VERSION 5.8 ;
BUSBITCHARS "[]" ;
DIVIDERCHAR "/" ;
UNITS
    DATABASE MICRONS 1000 ;
END UNITS

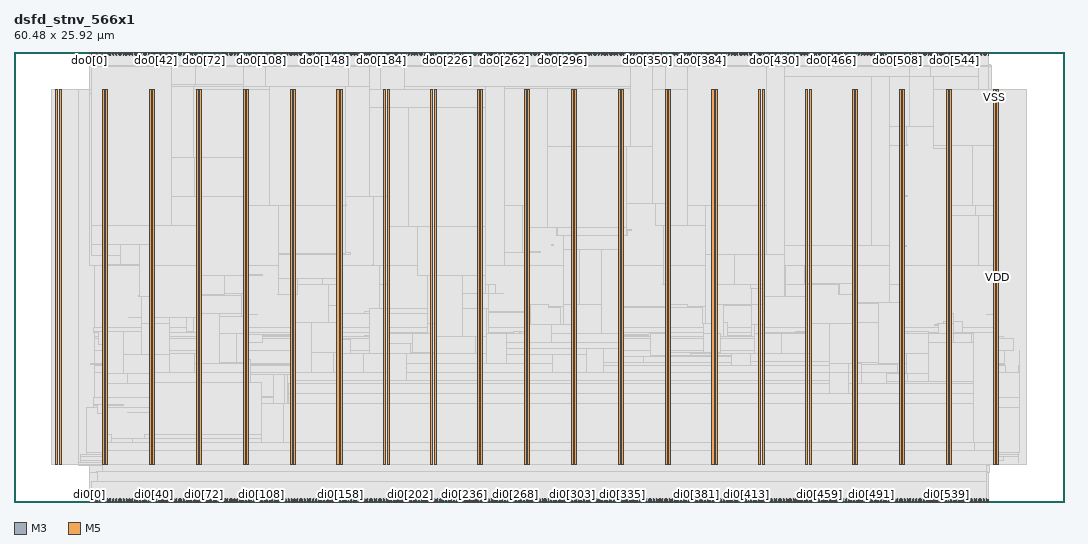
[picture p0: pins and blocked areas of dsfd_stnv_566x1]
MACRO dsfd_stnv_566x1
  FOREIGN dsfd_stnv_566x1 0 0 ;
  CLASS BLOCK ;
  SIZE 60.48 BY 25.92 ;
  PIN di0[0]
    DIRECTION INPUT ;
    USE SIGNAL ;
    PORT
      LAYER M3 ;
        RECT  4.356 0 4.374 0.144 ;
    END
  END di0[0]
  PIN di0[100]
    DIRECTION INPUT ;
    USE SIGNAL ;
    PORT
      LAYER M3 ;
        RECT  13.5 0 13.518 0.144 ;
    END
  END di0[100]
  PIN di0[101]
    DIRECTION INPUT ;
    USE SIGNAL ;
    PORT
      LAYER M5 ;
        RECT  13.584 0 13.608 0.192 ;
    END
  END di0[101]
  PIN di0[102]
    DIRECTION INPUT ;
    USE SIGNAL ;
    PORT
      LAYER M3 ;
        RECT  13.68 0 13.698 0.144 ;
    END
  END di0[102]
  PIN di0[103]
    DIRECTION INPUT ;
    USE SIGNAL ;
    PORT
      LAYER M5 ;
        RECT  13.776 0 13.8 0.192 ;
    END
  END di0[103]
  PIN di0[104]
    DIRECTION INPUT ;
    USE SIGNAL ;
    PORT
      LAYER M3 ;
        RECT  13.86 0 13.878 0.144 ;
    END
  END di0[104]
  PIN di0[105]
    DIRECTION INPUT ;
    USE SIGNAL ;
    PORT
      LAYER M5 ;
        RECT  13.968 0 13.992 0.192 ;
    END
  END di0[105]
  PIN di0[106]
    DIRECTION INPUT ;
    USE SIGNAL ;
    PORT
      LAYER M3 ;
        RECT  14.04 0 14.058 0.144 ;
    END
  END di0[106]
  PIN di0[107]
    DIRECTION INPUT ;
    USE SIGNAL ;
    PORT
      LAYER M5 ;
        RECT  14.16 0 14.184 0.192 ;
    END
  END di0[107]
  PIN di0[108]
    DIRECTION INPUT ;
    USE SIGNAL ;
    PORT
      LAYER M3 ;
        RECT  14.22 0 14.238 0.144 ;
    END
  END di0[108]
  PIN di0[109]
    DIRECTION INPUT ;
    USE SIGNAL ;
    PORT
      LAYER M5 ;
        RECT  14.304 0 14.328 0.192 ;
    END
  END di0[109]
  PIN di0[10]
    DIRECTION INPUT ;
    USE SIGNAL ;
    PORT
      LAYER M3 ;
        RECT  5.256 0 5.274 0.144 ;
    END
  END di0[10]
  PIN di0[110]
    DIRECTION INPUT ;
    USE SIGNAL ;
    PORT
      LAYER M3 ;
        RECT  14.4 0 14.418 0.144 ;
    END
  END di0[110]
  PIN di0[111]
    DIRECTION INPUT ;
    USE SIGNAL ;
    PORT
      LAYER M5 ;
        RECT  14.496 0 14.52 0.192 ;
    END
  END di0[111]
  PIN di0[112]
    DIRECTION INPUT ;
    USE SIGNAL ;
    PORT
      LAYER M3 ;
        RECT  14.58 0 14.598 0.144 ;
    END
  END di0[112]
  PIN di0[113]
    DIRECTION INPUT ;
    USE SIGNAL ;
    PORT
      LAYER M5 ;
        RECT  14.688 0 14.712 0.192 ;
    END
  END di0[113]
  PIN di0[114]
    DIRECTION INPUT ;
    USE SIGNAL ;
    PORT
      LAYER M3 ;
        RECT  14.796 0 14.814 0.144 ;
    END
  END di0[114]
  PIN di0[115]
    DIRECTION INPUT ;
    USE SIGNAL ;
    PORT
      LAYER M5 ;
        RECT  14.88 0 14.904 0.192 ;
    END
  END di0[115]
  PIN di0[116]
    DIRECTION INPUT ;
    USE SIGNAL ;
    PORT
      LAYER M3 ;
        RECT  14.976 0 14.994 0.144 ;
    END
  END di0[116]
  PIN di0[117]
    DIRECTION INPUT ;
    USE SIGNAL ;
    PORT
      LAYER M5 ;
        RECT  15.072 0 15.096 0.192 ;
    END
  END di0[117]
  PIN di0[118]
    DIRECTION INPUT ;
    USE SIGNAL ;
    PORT
      LAYER M3 ;
        RECT  15.156 0 15.174 0.144 ;
    END
  END di0[118]
  PIN di0[119]
    DIRECTION INPUT ;
    USE SIGNAL ;
    PORT
      LAYER M5 ;
        RECT  15.216 0 15.24 0.192 ;
    END
  END di0[119]
  PIN di0[11]
    DIRECTION INPUT ;
    USE SIGNAL ;
    PORT
      LAYER M5 ;
        RECT  5.376 0 5.4 0.192 ;
    END
  END di0[11]
  PIN di0[120]
    DIRECTION INPUT ;
    USE SIGNAL ;
    PORT
      LAYER M3 ;
        RECT  15.336 0 15.354 0.144 ;
    END
  END di0[120]
  PIN di0[121]
    DIRECTION INPUT ;
    USE SIGNAL ;
    PORT
      LAYER M5 ;
        RECT  15.408 0 15.432 0.192 ;
    END
  END di0[121]
  PIN di0[122]
    DIRECTION INPUT ;
    USE SIGNAL ;
    PORT
      LAYER M3 ;
        RECT  15.516 0 15.534 0.144 ;
    END
  END di0[122]
  PIN di0[123]
    DIRECTION INPUT ;
    USE SIGNAL ;
    PORT
      LAYER M5 ;
        RECT  15.6 0 15.624 0.192 ;
    END
  END di0[123]
  PIN di0[124]
    DIRECTION INPUT ;
    USE SIGNAL ;
    PORT
      LAYER M3 ;
        RECT  15.696 0 15.714 0.144 ;
    END
  END di0[124]
  PIN di0[125]
    DIRECTION INPUT ;
    USE SIGNAL ;
    PORT
      LAYER M5 ;
        RECT  15.792 0 15.816 0.192 ;
    END
  END di0[125]
  PIN di0[126]
    DIRECTION INPUT ;
    USE SIGNAL ;
    PORT
      LAYER M3 ;
        RECT  15.876 0 15.894 0.144 ;
    END
  END di0[126]
  PIN di0[127]
    DIRECTION INPUT ;
    USE SIGNAL ;
    PORT
      LAYER M5 ;
        RECT  15.984 0 16.008 0.192 ;
    END
  END di0[127]
  PIN di0[128]
    DIRECTION INPUT ;
    USE SIGNAL ;
    PORT
      LAYER M3 ;
        RECT  16.056 0 16.074 0.144 ;
    END
  END di0[128]
  PIN di0[129]
    DIRECTION INPUT ;
    USE SIGNAL ;
    PORT
      LAYER M5 ;
        RECT  16.128 0 16.152 0.192 ;
    END
  END di0[129]
  PIN di0[12]
    DIRECTION INPUT ;
    USE SIGNAL ;
    PORT
      LAYER M3 ;
        RECT  5.436 0 5.454 0.144 ;
    END
  END di0[12]
  PIN di0[130]
    DIRECTION INPUT ;
    USE SIGNAL ;
    PORT
      LAYER M3 ;
        RECT  16.236 0 16.254 0.144 ;
    END
  END di0[130]
  PIN di0[131]
    DIRECTION INPUT ;
    USE SIGNAL ;
    PORT
      LAYER M5 ;
        RECT  16.32 0 16.344 0.192 ;
    END
  END di0[131]
  PIN di0[132]
    DIRECTION INPUT ;
    USE SIGNAL ;
    PORT
      LAYER M3 ;
        RECT  16.416 0 16.434 0.144 ;
    END
  END di0[132]
  PIN di0[133]
    DIRECTION INPUT ;
    USE SIGNAL ;
    PORT
      LAYER M5 ;
        RECT  16.512 0 16.536 0.192 ;
    END
  END di0[133]
  PIN di0[134]
    DIRECTION INPUT ;
    USE SIGNAL ;
    PORT
      LAYER M3 ;
        RECT  16.596 0 16.614 0.144 ;
    END
  END di0[134]
  PIN di0[135]
    DIRECTION INPUT ;
    USE SIGNAL ;
    PORT
      LAYER M5 ;
        RECT  16.704 0 16.728 0.192 ;
    END
  END di0[135]
  PIN di0[136]
    DIRECTION INPUT ;
    USE SIGNAL ;
    PORT
      LAYER M3 ;
        RECT  16.776 0 16.794 0.144 ;
    END
  END di0[136]
  PIN di0[137]
    DIRECTION INPUT ;
    USE SIGNAL ;
    PORT
      LAYER M5 ;
        RECT  16.896 0 16.92 0.192 ;
    END
  END di0[137]
  PIN di0[138]
    DIRECTION INPUT ;
    USE SIGNAL ;
    PORT
      LAYER M3 ;
        RECT  16.956 0 16.974 0.144 ;
    END
  END di0[138]
  PIN di0[139]
    DIRECTION INPUT ;
    USE SIGNAL ;
    PORT
      LAYER M5 ;
        RECT  17.04 0 17.064 0.192 ;
    END
  END di0[139]
  PIN di0[13]
    DIRECTION INPUT ;
    USE SIGNAL ;
    PORT
      LAYER M5 ;
        RECT  5.52 0 5.544 0.192 ;
    END
  END di0[13]
  PIN di0[140]
    DIRECTION INPUT ;
    USE SIGNAL ;
    PORT
      LAYER M3 ;
        RECT  17.172 0 17.19 0.144 ;
    END
  END di0[140]
  PIN di0[141]
    DIRECTION INPUT ;
    USE SIGNAL ;
    PORT
      LAYER M5 ;
        RECT  17.232 0 17.256 0.192 ;
    END
  END di0[141]
  PIN di0[142]
    DIRECTION INPUT ;
    USE SIGNAL ;
    PORT
      LAYER M3 ;
        RECT  17.352 0 17.37 0.144 ;
    END
  END di0[142]
  PIN di0[143]
    DIRECTION INPUT ;
    USE SIGNAL ;
    PORT
      LAYER M5 ;
        RECT  17.424 0 17.448 0.192 ;
    END
  END di0[143]
  PIN di0[144]
    DIRECTION INPUT ;
    USE SIGNAL ;
    PORT
      LAYER M3 ;
        RECT  17.532 0 17.55 0.144 ;
    END
  END di0[144]
  PIN di0[145]
    DIRECTION INPUT ;
    USE SIGNAL ;
    PORT
      LAYER M5 ;
        RECT  17.616 0 17.64 0.192 ;
    END
  END di0[145]
  PIN di0[146]
    DIRECTION INPUT ;
    USE SIGNAL ;
    PORT
      LAYER M3 ;
        RECT  17.712 0 17.73 0.144 ;
    END
  END di0[146]
  PIN di0[147]
    DIRECTION INPUT ;
    USE SIGNAL ;
    PORT
      LAYER M5 ;
        RECT  17.808 0 17.832 0.192 ;
    END
  END di0[147]
  PIN di0[148]
    DIRECTION INPUT ;
    USE SIGNAL ;
    PORT
      LAYER M3 ;
        RECT  17.892 0 17.91 0.144 ;
    END
  END di0[148]
  PIN di0[149]
    DIRECTION INPUT ;
    USE SIGNAL ;
    PORT
      LAYER M5 ;
        RECT  18 0 18.024 0.192 ;
    END
  END di0[149]
  PIN di0[14]
    DIRECTION INPUT ;
    USE SIGNAL ;
    PORT
      LAYER M3 ;
        RECT  5.652 0 5.67 0.144 ;
    END
  END di0[14]
  PIN di0[150]
    DIRECTION INPUT ;
    USE SIGNAL ;
    PORT
      LAYER M3 ;
        RECT  18.072 0 18.09 0.144 ;
    END
  END di0[150]
  PIN di0[151]
    DIRECTION INPUT ;
    USE SIGNAL ;
    PORT
      LAYER M5 ;
        RECT  18.144 0 18.168 0.192 ;
    END
  END di0[151]
  PIN di0[152]
    DIRECTION INPUT ;
    USE SIGNAL ;
    PORT
      LAYER M3 ;
        RECT  18.252 0 18.27 0.144 ;
    END
  END di0[152]
  PIN di0[153]
    DIRECTION INPUT ;
    USE SIGNAL ;
    PORT
      LAYER M5 ;
        RECT  18.336 0 18.36 0.192 ;
    END
  END di0[153]
  PIN di0[154]
    DIRECTION INPUT ;
    USE SIGNAL ;
    PORT
      LAYER M3 ;
        RECT  18.432 0 18.45 0.144 ;
    END
  END di0[154]
  PIN di0[155]
    DIRECTION INPUT ;
    USE SIGNAL ;
    PORT
      LAYER M5 ;
        RECT  18.528 0 18.552 0.192 ;
    END
  END di0[155]
  PIN di0[156]
    DIRECTION INPUT ;
    USE SIGNAL ;
    PORT
      LAYER M3 ;
        RECT  18.612 0 18.63 0.144 ;
    END
  END di0[156]
  PIN di0[157]
    DIRECTION INPUT ;
    USE SIGNAL ;
    PORT
      LAYER M5 ;
        RECT  18.72 0 18.744 0.192 ;
    END
  END di0[157]
  PIN di0[158]
    DIRECTION INPUT ;
    USE SIGNAL ;
    PORT
      LAYER M3 ;
        RECT  18.792 0 18.81 0.144 ;
    END
  END di0[158]
  PIN di0[159]
    DIRECTION INPUT ;
    USE SIGNAL ;
    PORT
      LAYER M5 ;
        RECT  18.912 0 18.936 0.192 ;
    END
  END di0[159]
  PIN di0[15]
    DIRECTION INPUT ;
    USE SIGNAL ;
    PORT
      LAYER M5 ;
        RECT  5.712 0 5.736 0.192 ;
    END
  END di0[15]
  PIN di0[160]
    DIRECTION INPUT ;
    USE SIGNAL ;
    PORT
      LAYER M3 ;
        RECT  18.972 0 18.99 0.144 ;
    END
  END di0[160]
  PIN di0[161]
    DIRECTION INPUT ;
    USE SIGNAL ;
    PORT
      LAYER M5 ;
        RECT  19.056 0 19.08 0.192 ;
    END
  END di0[161]
  PIN di0[162]
    DIRECTION INPUT ;
    USE SIGNAL ;
    PORT
      LAYER M3 ;
        RECT  19.152 0 19.17 0.144 ;
    END
  END di0[162]
  PIN di0[163]
    DIRECTION INPUT ;
    USE SIGNAL ;
    PORT
      LAYER M5 ;
        RECT  19.248 0 19.272 0.192 ;
    END
  END di0[163]
  PIN di0[164]
    DIRECTION INPUT ;
    USE SIGNAL ;
    PORT
      LAYER M3 ;
        RECT  19.368 0 19.386 0.144 ;
    END
  END di0[164]
  PIN di0[165]
    DIRECTION INPUT ;
    USE SIGNAL ;
    PORT
      LAYER M5 ;
        RECT  19.44 0 19.464 0.192 ;
    END
  END di0[165]
  PIN di0[166]
    DIRECTION INPUT ;
    USE SIGNAL ;
    PORT
      LAYER M3 ;
        RECT  19.548 0 19.566 0.144 ;
    END
  END di0[166]
  PIN di0[167]
    DIRECTION INPUT ;
    USE SIGNAL ;
    PORT
      LAYER M5 ;
        RECT  19.632 0 19.656 0.192 ;
    END
  END di0[167]
  PIN di0[168]
    DIRECTION INPUT ;
    USE SIGNAL ;
    PORT
      LAYER M3 ;
        RECT  19.728 0 19.746 0.144 ;
    END
  END di0[168]
  PIN di0[169]
    DIRECTION INPUT ;
    USE SIGNAL ;
    PORT
      LAYER M5 ;
        RECT  19.824 0 19.848 0.192 ;
    END
  END di0[169]
  PIN di0[16]
    DIRECTION INPUT ;
    USE SIGNAL ;
    PORT
      LAYER M3 ;
        RECT  5.832 0 5.85 0.144 ;
    END
  END di0[16]
  PIN di0[170]
    DIRECTION INPUT ;
    USE SIGNAL ;
    PORT
      LAYER M3 ;
        RECT  19.908 0 19.926 0.144 ;
    END
  END di0[170]
  PIN di0[171]
    DIRECTION INPUT ;
    USE SIGNAL ;
    PORT
      LAYER M5 ;
        RECT  19.968 0 19.992 0.192 ;
    END
  END di0[171]
  PIN di0[172]
    DIRECTION INPUT ;
    USE SIGNAL ;
    PORT
      LAYER M3 ;
        RECT  20.088 0 20.106 0.144 ;
    END
  END di0[172]
  PIN di0[173]
    DIRECTION INPUT ;
    USE SIGNAL ;
    PORT
      LAYER M5 ;
        RECT  20.16 0 20.184 0.192 ;
    END
  END di0[173]
  PIN di0[174]
    DIRECTION INPUT ;
    USE SIGNAL ;
    PORT
      LAYER M3 ;
        RECT  20.268 0 20.286 0.144 ;
    END
  END di0[174]
  PIN di0[175]
    DIRECTION INPUT ;
    USE SIGNAL ;
    PORT
      LAYER M5 ;
        RECT  20.352 0 20.376 0.192 ;
    END
  END di0[175]
  PIN di0[176]
    DIRECTION INPUT ;
    USE SIGNAL ;
    PORT
      LAYER M3 ;
        RECT  20.448 0 20.466 0.144 ;
    END
  END di0[176]
  PIN di0[177]
    DIRECTION INPUT ;
    USE SIGNAL ;
    PORT
      LAYER M5 ;
        RECT  20.544 0 20.568 0.192 ;
    END
  END di0[177]
  PIN di0[178]
    DIRECTION INPUT ;
    USE SIGNAL ;
    PORT
      LAYER M3 ;
        RECT  20.628 0 20.646 0.144 ;
    END
  END di0[178]
  PIN di0[179]
    DIRECTION INPUT ;
    USE SIGNAL ;
    PORT
      LAYER M5 ;
        RECT  20.736 0 20.76 0.192 ;
    END
  END di0[179]
  PIN di0[17]
    DIRECTION INPUT ;
    USE SIGNAL ;
    PORT
      LAYER M5 ;
        RECT  5.904 0 5.928 0.192 ;
    END
  END di0[17]
  PIN di0[180]
    DIRECTION INPUT ;
    USE SIGNAL ;
    PORT
      LAYER M3 ;
        RECT  20.808 0 20.826 0.144 ;
    END
  END di0[180]
  PIN di0[181]
    DIRECTION INPUT ;
    USE SIGNAL ;
    PORT
      LAYER M5 ;
        RECT  20.88 0 20.904 0.192 ;
    END
  END di0[181]
  PIN di0[182]
    DIRECTION INPUT ;
    USE SIGNAL ;
    PORT
      LAYER M3 ;
        RECT  20.988 0 21.006 0.144 ;
    END
  END di0[182]
  PIN di0[183]
    DIRECTION INPUT ;
    USE SIGNAL ;
    PORT
      LAYER M5 ;
        RECT  21.072 0 21.096 0.192 ;
    END
  END di0[183]
  PIN di0[184]
    DIRECTION INPUT ;
    USE SIGNAL ;
    PORT
      LAYER M3 ;
        RECT  21.168 0 21.186 0.144 ;
    END
  END di0[184]
  PIN di0[185]
    DIRECTION INPUT ;
    USE SIGNAL ;
    PORT
      LAYER M5 ;
        RECT  21.264 0 21.288 0.192 ;
    END
  END di0[185]
  PIN di0[186]
    DIRECTION INPUT ;
    USE SIGNAL ;
    PORT
      LAYER M3 ;
        RECT  21.348 0 21.366 0.144 ;
    END
  END di0[186]
  PIN di0[187]
    DIRECTION INPUT ;
    USE SIGNAL ;
    PORT
      LAYER M5 ;
        RECT  21.456 0 21.48 0.192 ;
    END
  END di0[187]
  PIN di0[188]
    DIRECTION INPUT ;
    USE SIGNAL ;
    PORT
      LAYER M3 ;
        RECT  21.528 0 21.546 0.144 ;
    END
  END di0[188]
  PIN di0[189]
    DIRECTION INPUT ;
    USE SIGNAL ;
    PORT
      LAYER M5 ;
        RECT  21.648 0 21.672 0.192 ;
    END
  END di0[189]
  PIN di0[18]
    DIRECTION INPUT ;
    USE SIGNAL ;
    PORT
      LAYER M3 ;
        RECT  6.012 0 6.03 0.144 ;
    END
  END di0[18]
  PIN di0[190]
    DIRECTION INPUT ;
    USE SIGNAL ;
    PORT
      LAYER M3 ;
        RECT  21.744 0 21.762 0.144 ;
    END
  END di0[190]
  PIN di0[191]
    DIRECTION INPUT ;
    USE SIGNAL ;
    PORT
      LAYER M5 ;
        RECT  21.84 0 21.864 0.192 ;
    END
  END di0[191]
  PIN di0[192]
    DIRECTION INPUT ;
    USE SIGNAL ;
    PORT
      LAYER M3 ;
        RECT  21.924 0 21.942 0.144 ;
    END
  END di0[192]
  PIN di0[193]
    DIRECTION INPUT ;
    USE SIGNAL ;
    PORT
      LAYER M5 ;
        RECT  21.984 0 22.008 0.192 ;
    END
  END di0[193]
  PIN di0[194]
    DIRECTION INPUT ;
    USE SIGNAL ;
    PORT
      LAYER M3 ;
        RECT  22.104 0 22.122 0.144 ;
    END
  END di0[194]
  PIN di0[195]
    DIRECTION INPUT ;
    USE SIGNAL ;
    PORT
      LAYER M5 ;
        RECT  22.176 0 22.2 0.192 ;
    END
  END di0[195]
  PIN di0[196]
    DIRECTION INPUT ;
    USE SIGNAL ;
    PORT
      LAYER M3 ;
        RECT  22.284 0 22.302 0.144 ;
    END
  END di0[196]
  PIN di0[197]
    DIRECTION INPUT ;
    USE SIGNAL ;
    PORT
      LAYER M5 ;
        RECT  22.368 0 22.392 0.192 ;
    END
  END di0[197]
  PIN di0[198]
    DIRECTION INPUT ;
    USE SIGNAL ;
    PORT
      LAYER M3 ;
        RECT  22.464 0 22.482 0.144 ;
    END
  END di0[198]
  PIN di0[199]
    DIRECTION INPUT ;
    USE SIGNAL ;
    PORT
      LAYER M5 ;
        RECT  22.56 0 22.584 0.192 ;
    END
  END di0[199]
  PIN di0[19]
    DIRECTION INPUT ;
    USE SIGNAL ;
    PORT
      LAYER M5 ;
        RECT  6.096 0 6.12 0.192 ;
    END
  END di0[19]
  PIN di0[1]
    DIRECTION INPUT ;
    USE SIGNAL ;
    PORT
      LAYER M5 ;
        RECT  4.464 0 4.488 0.192 ;
    END
  END di0[1]
  PIN di0[200]
    DIRECTION INPUT ;
    USE SIGNAL ;
    PORT
      LAYER M3 ;
        RECT  22.644 0 22.662 0.144 ;
    END
  END di0[200]
  PIN di0[201]
    DIRECTION INPUT ;
    USE SIGNAL ;
    PORT
      LAYER M5 ;
        RECT  22.752 0 22.776 0.192 ;
    END
  END di0[201]
  PIN di0[202]
    DIRECTION INPUT ;
    USE SIGNAL ;
    PORT
      LAYER M3 ;
        RECT  22.824 0 22.842 0.144 ;
    END
  END di0[202]
  PIN di0[203]
    DIRECTION INPUT ;
    USE SIGNAL ;
    PORT
      LAYER M5 ;
        RECT  22.896 0 22.92 0.192 ;
    END
  END di0[203]
  PIN di0[204]
    DIRECTION INPUT ;
    USE SIGNAL ;
    PORT
      LAYER M3 ;
        RECT  23.004 0 23.022 0.144 ;
    END
  END di0[204]
  PIN di0[205]
    DIRECTION INPUT ;
    USE SIGNAL ;
    PORT
      LAYER M5 ;
        RECT  23.088 0 23.112 0.192 ;
    END
  END di0[205]
  PIN di0[206]
    DIRECTION INPUT ;
    USE SIGNAL ;
    PORT
      LAYER M3 ;
        RECT  23.184 0 23.202 0.144 ;
    END
  END di0[206]
  PIN di0[207]
    DIRECTION INPUT ;
    USE SIGNAL ;
    PORT
      LAYER M5 ;
        RECT  23.28 0 23.304 0.192 ;
    END
  END di0[207]
  PIN di0[208]
    DIRECTION INPUT ;
    USE SIGNAL ;
    PORT
      LAYER M3 ;
        RECT  23.364 0 23.382 0.144 ;
    END
  END di0[208]
  PIN di0[209]
    DIRECTION INPUT ;
    USE SIGNAL ;
    PORT
      LAYER M5 ;
        RECT  23.472 0 23.496 0.192 ;
    END
  END di0[209]
  PIN di0[20]
    DIRECTION INPUT ;
    USE SIGNAL ;
    PORT
      LAYER M3 ;
        RECT  6.192 0 6.21 0.144 ;
    END
  END di0[20]
  PIN di0[210]
    DIRECTION INPUT ;
    USE SIGNAL ;
    PORT
      LAYER M3 ;
        RECT  23.544 0 23.562 0.144 ;
    END
  END di0[210]
  PIN di0[211]
    DIRECTION INPUT ;
    USE SIGNAL ;
    PORT
      LAYER M5 ;
        RECT  23.664 0 23.688 0.192 ;
    END
  END di0[211]
  PIN di0[212]
    DIRECTION INPUT ;
    USE SIGNAL ;
    PORT
      LAYER M3 ;
        RECT  23.724 0 23.742 0.144 ;
    END
  END di0[212]
  PIN di0[213]
    DIRECTION INPUT ;
    USE SIGNAL ;
    PORT
      LAYER M5 ;
        RECT  23.808 0 23.832 0.192 ;
    END
  END di0[213]
  PIN di0[214]
    DIRECTION INPUT ;
    USE SIGNAL ;
    PORT
      LAYER M3 ;
        RECT  23.94 0 23.958 0.144 ;
    END
  END di0[214]
  PIN di0[215]
    DIRECTION INPUT ;
    USE SIGNAL ;
    PORT
      LAYER M5 ;
        RECT  24 0 24.024 0.192 ;
    END
  END di0[215]
  PIN di0[216]
    DIRECTION INPUT ;
    USE SIGNAL ;
    PORT
      LAYER M3 ;
        RECT  24.12 0 24.138 0.144 ;
    END
  END di0[216]
  PIN di0[217]
    DIRECTION INPUT ;
    USE SIGNAL ;
    PORT
      LAYER M5 ;
        RECT  24.192 0 24.216 0.192 ;
    END
  END di0[217]
  PIN di0[218]
    DIRECTION INPUT ;
    USE SIGNAL ;
    PORT
      LAYER M3 ;
        RECT  24.3 0 24.318 0.144 ;
    END
  END di0[218]
  PIN di0[219]
    DIRECTION INPUT ;
    USE SIGNAL ;
    PORT
      LAYER M5 ;
        RECT  24.384 0 24.408 0.192 ;
    END
  END di0[219]
  PIN di0[21]
    DIRECTION INPUT ;
    USE SIGNAL ;
    PORT
      LAYER M5 ;
        RECT  6.288 0 6.312 0.192 ;
    END
  END di0[21]
  PIN di0[220]
    DIRECTION INPUT ;
    USE SIGNAL ;
    PORT
      LAYER M3 ;
        RECT  24.48 0 24.498 0.144 ;
    END
  END di0[220]
  PIN di0[221]
    DIRECTION INPUT ;
    USE SIGNAL ;
    PORT
      LAYER M5 ;
        RECT  24.576 0 24.6 0.192 ;
    END
  END di0[221]
  PIN di0[222]
    DIRECTION INPUT ;
    USE SIGNAL ;
    PORT
      LAYER M3 ;
        RECT  24.66 0 24.678 0.144 ;
    END
  END di0[222]
  PIN di0[223]
    DIRECTION INPUT ;
    USE SIGNAL ;
    PORT
      LAYER M5 ;
        RECT  24.72 0 24.744 0.192 ;
    END
  END di0[223]
  PIN di0[224]
    DIRECTION INPUT ;
    USE SIGNAL ;
    PORT
      LAYER M3 ;
        RECT  24.84 0 24.858 0.144 ;
    END
  END di0[224]
  PIN di0[225]
    DIRECTION INPUT ;
    USE SIGNAL ;
    PORT
      LAYER M5 ;
        RECT  24.912 0 24.936 0.192 ;
    END
  END di0[225]
  PIN di0[226]
    DIRECTION INPUT ;
    USE SIGNAL ;
    PORT
      LAYER M3 ;
        RECT  25.02 0 25.038 0.144 ;
    END
  END di0[226]
  PIN di0[227]
    DIRECTION INPUT ;
    USE SIGNAL ;
    PORT
      LAYER M5 ;
        RECT  25.104 0 25.128 0.192 ;
    END
  END di0[227]
  PIN di0[228]
    DIRECTION INPUT ;
    USE SIGNAL ;
    PORT
      LAYER M3 ;
        RECT  25.2 0 25.218 0.144 ;
    END
  END di0[228]
  PIN di0[229]
    DIRECTION INPUT ;
    USE SIGNAL ;
    PORT
      LAYER M5 ;
        RECT  25.296 0 25.32 0.192 ;
    END
  END di0[229]
  PIN di0[22]
    DIRECTION INPUT ;
    USE SIGNAL ;
    PORT
      LAYER M3 ;
        RECT  6.372 0 6.39 0.144 ;
    END
  END di0[22]
  PIN di0[230]
    DIRECTION INPUT ;
    USE SIGNAL ;
    PORT
      LAYER M3 ;
        RECT  25.38 0 25.398 0.144 ;
    END
  END di0[230]
  PIN di0[231]
    DIRECTION INPUT ;
    USE SIGNAL ;
    PORT
      LAYER M5 ;
        RECT  25.488 0 25.512 0.192 ;
    END
  END di0[231]
  PIN di0[232]
    DIRECTION INPUT ;
    USE SIGNAL ;
    PORT
      LAYER M3 ;
        RECT  25.56 0 25.578 0.144 ;
    END
  END di0[232]
  PIN di0[233]
    DIRECTION INPUT ;
    USE SIGNAL ;
    PORT
      LAYER M5 ;
        RECT  25.68 0 25.704 0.192 ;
    END
  END di0[233]
  PIN di0[234]
    DIRECTION INPUT ;
    USE SIGNAL ;
    PORT
      LAYER M3 ;
        RECT  25.74 0 25.758 0.144 ;
    END
  END di0[234]
  PIN di0[235]
    DIRECTION INPUT ;
    USE SIGNAL ;
    PORT
      LAYER M5 ;
        RECT  25.824 0 25.848 0.192 ;
    END
  END di0[235]
  PIN di0[236]
    DIRECTION INPUT ;
    USE SIGNAL ;
    PORT
      LAYER M3 ;
        RECT  25.92 0 25.938 0.144 ;
    END
  END di0[236]
  PIN di0[237]
    DIRECTION INPUT ;
    USE SIGNAL ;
    PORT
      LAYER M5 ;
        RECT  26.016 0 26.04 0.192 ;
    END
  END di0[237]
  PIN di0[238]
    DIRECTION INPUT ;
    USE SIGNAL ;
    PORT
      LAYER M3 ;
        RECT  26.1 0 26.118 0.144 ;
    END
  END di0[238]
  PIN di0[239]
    DIRECTION INPUT ;
    USE SIGNAL ;
    PORT
      LAYER M5 ;
        RECT  26.208 0 26.232 0.192 ;
    END
  END di0[239]
  PIN di0[23]
    DIRECTION INPUT ;
    USE SIGNAL ;
    PORT
      LAYER M5 ;
        RECT  6.48 0 6.504 0.192 ;
    END
  END di0[23]
  PIN di0[240]
    DIRECTION INPUT ;
    USE SIGNAL ;
    PORT
      LAYER M3 ;
        RECT  26.316 0 26.334 0.144 ;
    END
  END di0[240]
  PIN di0[241]
    DIRECTION INPUT ;
    USE SIGNAL ;
    PORT
      LAYER M5 ;
        RECT  26.4 0 26.424 0.192 ;
    END
  END di0[241]
  PIN di0[242]
    DIRECTION INPUT ;
    USE SIGNAL ;
    PORT
      LAYER M3 ;
        RECT  26.496 0 26.514 0.144 ;
    END
  END di0[242]
  PIN di0[243]
    DIRECTION INPUT ;
    USE SIGNAL ;
    PORT
      LAYER M5 ;
        RECT  26.592 0 26.616 0.192 ;
    END
  END di0[243]
  PIN di0[244]
    DIRECTION INPUT ;
    USE SIGNAL ;
    PORT
      LAYER M3 ;
        RECT  26.676 0 26.694 0.144 ;
    END
  END di0[244]
  PIN di0[245]
    DIRECTION INPUT ;
    USE SIGNAL ;
    PORT
      LAYER M5 ;
        RECT  26.736 0 26.76 0.192 ;
    END
  END di0[245]
  PIN di0[246]
    DIRECTION INPUT ;
    USE SIGNAL ;
    PORT
      LAYER M3 ;
        RECT  26.856 0 26.874 0.144 ;
    END
  END di0[246]
  PIN di0[247]
    DIRECTION INPUT ;
    USE SIGNAL ;
    PORT
      LAYER M5 ;
        RECT  26.928 0 26.952 0.192 ;
    END
  END di0[247]
  PIN di0[248]
    DIRECTION INPUT ;
    USE SIGNAL ;
    PORT
      LAYER M3 ;
        RECT  27.036 0 27.054 0.144 ;
    END
  END di0[248]
  PIN di0[249]
    DIRECTION INPUT ;
    USE SIGNAL ;
    PORT
      LAYER M5 ;
        RECT  27.12 0 27.144 0.192 ;
    END
  END di0[249]
  PIN di0[24]
    DIRECTION INPUT ;
    USE SIGNAL ;
    PORT
      LAYER M3 ;
        RECT  6.552 0 6.57 0.144 ;
    END
  END di0[24]
  PIN di0[250]
    DIRECTION INPUT ;
    USE SIGNAL ;
    PORT
      LAYER M3 ;
        RECT  27.216 0 27.234 0.144 ;
    END
  END di0[250]
  PIN di0[251]
    DIRECTION INPUT ;
    USE SIGNAL ;
    PORT
      LAYER M5 ;
        RECT  27.312 0 27.336 0.192 ;
    END
  END di0[251]
  PIN di0[252]
    DIRECTION INPUT ;
    USE SIGNAL ;
    PORT
      LAYER M3 ;
        RECT  27.396 0 27.414 0.144 ;
    END
  END di0[252]
  PIN di0[253]
    DIRECTION INPUT ;
    USE SIGNAL ;
    PORT
      LAYER M5 ;
        RECT  27.504 0 27.528 0.192 ;
    END
  END di0[253]
  PIN di0[254]
    DIRECTION INPUT ;
    USE SIGNAL ;
    PORT
      LAYER M3 ;
        RECT  27.576 0 27.594 0.144 ;
    END
  END di0[254]
  PIN di0[255]
    DIRECTION INPUT ;
    USE SIGNAL ;
    PORT
      LAYER M5 ;
        RECT  27.648 0 27.672 0.192 ;
    END
  END di0[255]
  PIN di0[256]
    DIRECTION INPUT ;
    USE SIGNAL ;
    PORT
      LAYER M3 ;
        RECT  27.756 0 27.774 0.144 ;
    END
  END di0[256]
  PIN di0[257]
    DIRECTION INPUT ;
    USE SIGNAL ;
    PORT
      LAYER M5 ;
        RECT  27.84 0 27.864 0.192 ;
    END
  END di0[257]
  PIN di0[258]
    DIRECTION INPUT ;
    USE SIGNAL ;
    PORT
      LAYER M3 ;
        RECT  27.936 0 27.954 0.144 ;
    END
  END di0[258]
  PIN di0[259]
    DIRECTION INPUT ;
    USE SIGNAL ;
    PORT
      LAYER M5 ;
        RECT  28.032 0 28.056 0.192 ;
    END
  END di0[259]
  PIN di0[25]
    DIRECTION INPUT ;
    USE SIGNAL ;
    PORT
      LAYER M5 ;
        RECT  6.624 0 6.648 0.192 ;
    END
  END di0[25]
  PIN di0[260]
    DIRECTION INPUT ;
    USE SIGNAL ;
    PORT
      LAYER M3 ;
        RECT  28.116 0 28.134 0.144 ;
    END
  END di0[260]
  PIN di0[261]
    DIRECTION INPUT ;
    USE SIGNAL ;
    PORT
      LAYER M5 ;
        RECT  28.224 0 28.248 0.192 ;
    END
  END di0[261]
  PIN di0[262]
    DIRECTION INPUT ;
    USE SIGNAL ;
    PORT
      LAYER M3 ;
        RECT  28.296 0 28.314 0.144 ;
    END
  END di0[262]
  PIN di0[263]
    DIRECTION INPUT ;
    USE SIGNAL ;
    PORT
      LAYER M5 ;
        RECT  28.416 0 28.44 0.192 ;
    END
  END di0[263]
  PIN di0[264]
    DIRECTION INPUT ;
    USE SIGNAL ;
    PORT
      LAYER M3 ;
        RECT  28.476 0 28.494 0.144 ;
    END
  END di0[264]
  PIN di0[265]
    DIRECTION INPUT ;
    USE SIGNAL ;
    PORT
      LAYER M5 ;
        RECT  28.56 0 28.584 0.192 ;
    END
  END di0[265]
  PIN di0[266]
    DIRECTION INPUT ;
    USE SIGNAL ;
    PORT
      LAYER M3 ;
        RECT  28.692 0 28.71 0.144 ;
    END
  END di0[266]
  PIN di0[267]
    DIRECTION INPUT ;
    USE SIGNAL ;
    PORT
      LAYER M5 ;
        RECT  28.752 0 28.776 0.192 ;
    END
  END di0[267]
  PIN di0[268]
    DIRECTION INPUT ;
    USE SIGNAL ;
    PORT
      LAYER M3 ;
        RECT  28.872 0 28.89 0.144 ;
    END
  END di0[268]
  PIN di0[269]
    DIRECTION INPUT ;
    USE SIGNAL ;
    PORT
      LAYER M5 ;
        RECT  28.944 0 28.968 0.192 ;
    END
  END di0[269]
  PIN di0[26]
    DIRECTION INPUT ;
    USE SIGNAL ;
    PORT
      LAYER M3 ;
        RECT  6.732 0 6.75 0.144 ;
    END
  END di0[26]
  PIN di0[270]
    DIRECTION INPUT ;
    USE SIGNAL ;
    PORT
      LAYER M3 ;
        RECT  29.052 0 29.07 0.144 ;
    END
  END di0[270]
  PIN di0[271]
    DIRECTION INPUT ;
    USE SIGNAL ;
    PORT
      LAYER M5 ;
        RECT  29.136 0 29.16 0.192 ;
    END
  END di0[271]
  PIN di0[272]
    DIRECTION INPUT ;
    USE SIGNAL ;
    PORT
      LAYER M3 ;
        RECT  29.232 0 29.25 0.144 ;
    END
  END di0[272]
  PIN di0[273]
    DIRECTION INPUT ;
    USE SIGNAL ;
    PORT
      LAYER M5 ;
        RECT  29.328 0 29.352 0.192 ;
    END
  END di0[273]
  PIN di0[274]
    DIRECTION INPUT ;
    USE SIGNAL ;
    PORT
      LAYER M3 ;
        RECT  29.412 0 29.43 0.144 ;
    END
  END di0[274]
  PIN di0[275]
    DIRECTION INPUT ;
    USE SIGNAL ;
    PORT
      LAYER M5 ;
        RECT  29.52 0 29.544 0.192 ;
    END
  END di0[275]
  PIN di0[276]
    DIRECTION INPUT ;
    USE SIGNAL ;
    PORT
      LAYER M3 ;
        RECT  29.592 0 29.61 0.144 ;
    END
  END di0[276]
  PIN di0[277]
    DIRECTION INPUT ;
    USE SIGNAL ;
    PORT
      LAYER M5 ;
        RECT  29.664 0 29.688 0.192 ;
    END
  END di0[277]
  PIN di0[278]
    DIRECTION INPUT ;
    USE SIGNAL ;
    PORT
      LAYER M3 ;
        RECT  29.772 0 29.79 0.144 ;
    END
  END di0[278]
  PIN di0[279]
    DIRECTION INPUT ;
    USE SIGNAL ;
    PORT
      LAYER M5 ;
        RECT  29.856 0 29.88 0.192 ;
    END
  END di0[279]
  PIN di0[27]
    DIRECTION INPUT ;
    USE SIGNAL ;
    PORT
      LAYER M5 ;
        RECT  6.816 0 6.84 0.192 ;
    END
  END di0[27]
  PIN di0[280]
    DIRECTION INPUT ;
    USE SIGNAL ;
    PORT
      LAYER M3 ;
        RECT  29.952 0 29.97 0.144 ;
    END
  END di0[280]
  PIN di0[281]
    DIRECTION INPUT ;
    USE SIGNAL ;
    PORT
      LAYER M5 ;
        RECT  30.048 0 30.072 0.192 ;
    END
  END di0[281]
  PIN di0[282]
    DIRECTION INPUT ;
    USE SIGNAL ;
    PORT
      LAYER M3 ;
        RECT  30.132 0 30.15 0.144 ;
    END
  END di0[282]
  PIN di0[283]
    DIRECTION INPUT ;
    USE SIGNAL ;
    PORT
      LAYER M3 ;
        RECT  30.312 0 30.33 0.144 ;
    END
  END di0[283]
  PIN di0[284]
    DIRECTION INPUT ;
    USE SIGNAL ;
    PORT
      LAYER M5 ;
        RECT  30.432 0 30.456 0.192 ;
    END
  END di0[284]
  PIN di0[285]
    DIRECTION INPUT ;
    USE SIGNAL ;
    PORT
      LAYER M3 ;
        RECT  30.492 0 30.51 0.144 ;
    END
  END di0[285]
  PIN di0[286]
    DIRECTION INPUT ;
    USE SIGNAL ;
    PORT
      LAYER M5 ;
        RECT  30.576 0 30.6 0.192 ;
    END
  END di0[286]
  PIN di0[287]
    DIRECTION INPUT ;
    USE SIGNAL ;
    PORT
      LAYER M3 ;
        RECT  30.672 0 30.69 0.144 ;
    END
  END di0[287]
  PIN di0[288]
    DIRECTION INPUT ;
    USE SIGNAL ;
    PORT
      LAYER M5 ;
        RECT  30.768 0 30.792 0.192 ;
    END
  END di0[288]
  PIN di0[289]
    DIRECTION INPUT ;
    USE SIGNAL ;
    PORT
      LAYER M3 ;
        RECT  30.888 0 30.906 0.144 ;
    END
  END di0[289]
  PIN di0[28]
    DIRECTION INPUT ;
    USE SIGNAL ;
    PORT
      LAYER M3 ;
        RECT  6.912 0 6.93 0.144 ;
    END
  END di0[28]
  PIN di0[290]
    DIRECTION INPUT ;
    USE SIGNAL ;
    PORT
      LAYER M5 ;
        RECT  30.96 0 30.984 0.192 ;
    END
  END di0[290]
  PIN di0[291]
    DIRECTION INPUT ;
    USE SIGNAL ;
    PORT
      LAYER M3 ;
        RECT  31.068 0 31.086 0.144 ;
    END
  END di0[291]
  PIN di0[292]
    DIRECTION INPUT ;
    USE SIGNAL ;
    PORT
      LAYER M5 ;
        RECT  31.152 0 31.176 0.192 ;
    END
  END di0[292]
  PIN di0[293]
    DIRECTION INPUT ;
    USE SIGNAL ;
    PORT
      LAYER M3 ;
        RECT  31.248 0 31.266 0.144 ;
    END
  END di0[293]
  PIN di0[294]
    DIRECTION INPUT ;
    USE SIGNAL ;
    PORT
      LAYER M5 ;
        RECT  31.344 0 31.368 0.192 ;
    END
  END di0[294]
  PIN di0[295]
    DIRECTION INPUT ;
    USE SIGNAL ;
    PORT
      LAYER M3 ;
        RECT  31.428 0 31.446 0.144 ;
    END
  END di0[295]
  PIN di0[296]
    DIRECTION INPUT ;
    USE SIGNAL ;
    PORT
      LAYER M5 ;
        RECT  31.488 0 31.512 0.192 ;
    END
  END di0[296]
  PIN di0[297]
    DIRECTION INPUT ;
    USE SIGNAL ;
    PORT
      LAYER M3 ;
        RECT  31.608 0 31.626 0.144 ;
    END
  END di0[297]
  PIN di0[298]
    DIRECTION INPUT ;
    USE SIGNAL ;
    PORT
      LAYER M5 ;
        RECT  31.68 0 31.704 0.192 ;
    END
  END di0[298]
  PIN di0[299]
    DIRECTION INPUT ;
    USE SIGNAL ;
    PORT
      LAYER M3 ;
        RECT  31.788 0 31.806 0.144 ;
    END
  END di0[299]
  PIN di0[29]
    DIRECTION INPUT ;
    USE SIGNAL ;
    PORT
      LAYER M5 ;
        RECT  7.008 0 7.032 0.192 ;
    END
  END di0[29]
  PIN di0[2]
    DIRECTION INPUT ;
    USE SIGNAL ;
    PORT
      LAYER M3 ;
        RECT  4.536 0 4.554 0.144 ;
    END
  END di0[2]
  PIN di0[300]
    DIRECTION INPUT ;
    USE SIGNAL ;
    PORT
      LAYER M5 ;
        RECT  31.872 0 31.896 0.192 ;
    END
  END di0[300]
  PIN di0[301]
    DIRECTION INPUT ;
    USE SIGNAL ;
    PORT
      LAYER M3 ;
        RECT  31.968 0 31.986 0.144 ;
    END
  END di0[301]
  PIN di0[302]
    DIRECTION INPUT ;
    USE SIGNAL ;
    PORT
      LAYER M5 ;
        RECT  32.064 0 32.088 0.192 ;
    END
  END di0[302]
  PIN di0[303]
    DIRECTION INPUT ;
    USE SIGNAL ;
    PORT
      LAYER M3 ;
        RECT  32.148 0 32.166 0.144 ;
    END
  END di0[303]
  PIN di0[304]
    DIRECTION INPUT ;
    USE SIGNAL ;
    PORT
      LAYER M5 ;
        RECT  32.256 0 32.28 0.192 ;
    END
  END di0[304]
  PIN di0[305]
    DIRECTION INPUT ;
    USE SIGNAL ;
    PORT
      LAYER M3 ;
        RECT  32.328 0 32.346 0.144 ;
    END
  END di0[305]
  PIN di0[306]
    DIRECTION INPUT ;
    USE SIGNAL ;
    PORT
      LAYER M5 ;
        RECT  32.4 0 32.424 0.192 ;
    END
  END di0[306]
  PIN di0[307]
    DIRECTION INPUT ;
    USE SIGNAL ;
    PORT
      LAYER M3 ;
        RECT  32.508 0 32.526 0.144 ;
    END
  END di0[307]
  PIN di0[308]
    DIRECTION INPUT ;
    USE SIGNAL ;
    PORT
      LAYER M5 ;
        RECT  32.592 0 32.616 0.192 ;
    END
  END di0[308]
  PIN di0[309]
    DIRECTION INPUT ;
    USE SIGNAL ;
    PORT
      LAYER M3 ;
        RECT  32.688 0 32.706 0.144 ;
    END
  END di0[309]
  PIN di0[30]
    DIRECTION INPUT ;
    USE SIGNAL ;
    PORT
      LAYER M3 ;
        RECT  7.092 0 7.11 0.144 ;
    END
  END di0[30]
  PIN di0[310]
    DIRECTION INPUT ;
    USE SIGNAL ;
    PORT
      LAYER M5 ;
        RECT  32.784 0 32.808 0.192 ;
    END
  END di0[310]
  PIN di0[311]
    DIRECTION INPUT ;
    USE SIGNAL ;
    PORT
      LAYER M3 ;
        RECT  32.868 0 32.886 0.144 ;
    END
  END di0[311]
  PIN di0[312]
    DIRECTION INPUT ;
    USE SIGNAL ;
    PORT
      LAYER M5 ;
        RECT  32.976 0 33 0.192 ;
    END
  END di0[312]
  PIN di0[313]
    DIRECTION INPUT ;
    USE SIGNAL ;
    PORT
      LAYER M3 ;
        RECT  33.048 0 33.066 0.144 ;
    END
  END di0[313]
  PIN di0[314]
    DIRECTION INPUT ;
    USE SIGNAL ;
    PORT
      LAYER M5 ;
        RECT  33.168 0 33.192 0.192 ;
    END
  END di0[314]
  PIN di0[315]
    DIRECTION INPUT ;
    USE SIGNAL ;
    PORT
      LAYER M3 ;
        RECT  33.264 0 33.282 0.144 ;
    END
  END di0[315]
  PIN di0[316]
    DIRECTION INPUT ;
    USE SIGNAL ;
    PORT
      LAYER M5 ;
        RECT  33.36 0 33.384 0.192 ;
    END
  END di0[316]
  PIN di0[317]
    DIRECTION INPUT ;
    USE SIGNAL ;
    PORT
      LAYER M3 ;
        RECT  33.444 0 33.462 0.144 ;
    END
  END di0[317]
  PIN di0[318]
    DIRECTION INPUT ;
    USE SIGNAL ;
    PORT
      LAYER M5 ;
        RECT  33.504 0 33.528 0.192 ;
    END
  END di0[318]
  PIN di0[319]
    DIRECTION INPUT ;
    USE SIGNAL ;
    PORT
      LAYER M3 ;
        RECT  33.624 0 33.642 0.144 ;
    END
  END di0[319]
  PIN di0[31]
    DIRECTION INPUT ;
    USE SIGNAL ;
    PORT
      LAYER M5 ;
        RECT  7.2 0 7.224 0.192 ;
    END
  END di0[31]
  PIN di0[320]
    DIRECTION INPUT ;
    USE SIGNAL ;
    PORT
      LAYER M5 ;
        RECT  33.696 0 33.72 0.192 ;
    END
  END di0[320]
  PIN di0[321]
    DIRECTION INPUT ;
    USE SIGNAL ;
    PORT
      LAYER M3 ;
        RECT  33.804 0 33.822 0.144 ;
    END
  END di0[321]
  PIN di0[322]
    DIRECTION INPUT ;
    USE SIGNAL ;
    PORT
      LAYER M5 ;
        RECT  33.888 0 33.912 0.192 ;
    END
  END di0[322]
  PIN di0[323]
    DIRECTION INPUT ;
    USE SIGNAL ;
    PORT
      LAYER M3 ;
        RECT  33.984 0 34.002 0.144 ;
    END
  END di0[323]
  PIN di0[324]
    DIRECTION INPUT ;
    USE SIGNAL ;
    PORT
      LAYER M5 ;
        RECT  34.08 0 34.104 0.192 ;
    END
  END di0[324]
  PIN di0[325]
    DIRECTION INPUT ;
    USE SIGNAL ;
    PORT
      LAYER M3 ;
        RECT  34.164 0 34.182 0.144 ;
    END
  END di0[325]
  PIN di0[326]
    DIRECTION INPUT ;
    USE SIGNAL ;
    PORT
      LAYER M5 ;
        RECT  34.272 0 34.296 0.192 ;
    END
  END di0[326]
  PIN di0[327]
    DIRECTION INPUT ;
    USE SIGNAL ;
    PORT
      LAYER M3 ;
        RECT  34.344 0 34.362 0.144 ;
    END
  END di0[327]
  PIN di0[328]
    DIRECTION INPUT ;
    USE SIGNAL ;
    PORT
      LAYER M5 ;
        RECT  34.416 0 34.44 0.192 ;
    END
  END di0[328]
  PIN di0[329]
    DIRECTION INPUT ;
    USE SIGNAL ;
    PORT
      LAYER M3 ;
        RECT  34.524 0 34.542 0.144 ;
    END
  END di0[329]
  PIN di0[32]
    DIRECTION INPUT ;
    USE SIGNAL ;
    PORT
      LAYER M3 ;
        RECT  7.272 0 7.29 0.144 ;
    END
  END di0[32]
  PIN di0[330]
    DIRECTION INPUT ;
    USE SIGNAL ;
    PORT
      LAYER M5 ;
        RECT  34.608 0 34.632 0.192 ;
    END
  END di0[330]
  PIN di0[331]
    DIRECTION INPUT ;
    USE SIGNAL ;
    PORT
      LAYER M3 ;
        RECT  34.704 0 34.722 0.144 ;
    END
  END di0[331]
  PIN di0[332]
    DIRECTION INPUT ;
    USE SIGNAL ;
    PORT
      LAYER M5 ;
        RECT  34.8 0 34.824 0.192 ;
    END
  END di0[332]
  PIN di0[333]
    DIRECTION INPUT ;
    USE SIGNAL ;
    PORT
      LAYER M3 ;
        RECT  34.884 0 34.902 0.144 ;
    END
  END di0[333]
  PIN di0[334]
    DIRECTION INPUT ;
    USE SIGNAL ;
    PORT
      LAYER M5 ;
        RECT  34.992 0 35.016 0.192 ;
    END
  END di0[334]
  PIN di0[335]
    DIRECTION INPUT ;
    USE SIGNAL ;
    PORT
      LAYER M3 ;
        RECT  35.064 0 35.082 0.144 ;
    END
  END di0[335]
  PIN di0[336]
    DIRECTION INPUT ;
    USE SIGNAL ;
    PORT
      LAYER M5 ;
        RECT  35.184 0 35.208 0.192 ;
    END
  END di0[336]
  PIN di0[337]
    DIRECTION INPUT ;
    USE SIGNAL ;
    PORT
      LAYER M3 ;
        RECT  35.244 0 35.262 0.144 ;
    END
  END di0[337]
  PIN di0[338]
    DIRECTION INPUT ;
    USE SIGNAL ;
    PORT
      LAYER M5 ;
        RECT  35.328 0 35.352 0.192 ;
    END
  END di0[338]
  PIN di0[339]
    DIRECTION INPUT ;
    USE SIGNAL ;
    PORT
      LAYER M3 ;
        RECT  35.46 0 35.478 0.144 ;
    END
  END di0[339]
  PIN di0[33]
    DIRECTION INPUT ;
    USE SIGNAL ;
    PORT
      LAYER M5 ;
        RECT  7.392 0 7.416 0.192 ;
    END
  END di0[33]
  PIN di0[340]
    DIRECTION INPUT ;
    USE SIGNAL ;
    PORT
      LAYER M5 ;
        RECT  35.52 0 35.544 0.192 ;
    END
  END di0[340]
  PIN di0[341]
    DIRECTION INPUT ;
    USE SIGNAL ;
    PORT
      LAYER M3 ;
        RECT  35.64 0 35.658 0.144 ;
    END
  END di0[341]
  PIN di0[342]
    DIRECTION INPUT ;
    USE SIGNAL ;
    PORT
      LAYER M5 ;
        RECT  35.712 0 35.736 0.192 ;
    END
  END di0[342]
  PIN di0[343]
    DIRECTION INPUT ;
    USE SIGNAL ;
    PORT
      LAYER M3 ;
        RECT  35.82 0 35.838 0.144 ;
    END
  END di0[343]
  PIN di0[344]
    DIRECTION INPUT ;
    USE SIGNAL ;
    PORT
      LAYER M5 ;
        RECT  35.904 0 35.928 0.192 ;
    END
  END di0[344]
  PIN di0[345]
    DIRECTION INPUT ;
    USE SIGNAL ;
    PORT
      LAYER M3 ;
        RECT  36 0 36.018 0.144 ;
    END
  END di0[345]
  PIN di0[346]
    DIRECTION INPUT ;
    USE SIGNAL ;
    PORT
      LAYER M5 ;
        RECT  36.096 0 36.12 0.192 ;
    END
  END di0[346]
  PIN di0[347]
    DIRECTION INPUT ;
    USE SIGNAL ;
    PORT
      LAYER M3 ;
        RECT  36.18 0 36.198 0.144 ;
    END
  END di0[347]
  PIN di0[348]
    DIRECTION INPUT ;
    USE SIGNAL ;
    PORT
      LAYER M5 ;
        RECT  36.24 0 36.264 0.192 ;
    END
  END di0[348]
  PIN di0[349]
    DIRECTION INPUT ;
    USE SIGNAL ;
    PORT
      LAYER M3 ;
        RECT  36.36 0 36.378 0.144 ;
    END
  END di0[349]
  PIN di0[34]
    DIRECTION INPUT ;
    USE SIGNAL ;
    PORT
      LAYER M3 ;
        RECT  7.452 0 7.47 0.144 ;
    END
  END di0[34]
  PIN di0[350]
    DIRECTION INPUT ;
    USE SIGNAL ;
    PORT
      LAYER M5 ;
        RECT  36.432 0 36.456 0.192 ;
    END
  END di0[350]
  PIN di0[351]
    DIRECTION INPUT ;
    USE SIGNAL ;
    PORT
      LAYER M3 ;
        RECT  36.54 0 36.558 0.144 ;
    END
  END di0[351]
  PIN di0[352]
    DIRECTION INPUT ;
    USE SIGNAL ;
    PORT
      LAYER M5 ;
        RECT  36.624 0 36.648 0.192 ;
    END
  END di0[352]
  PIN di0[353]
    DIRECTION INPUT ;
    USE SIGNAL ;
    PORT
      LAYER M3 ;
        RECT  36.72 0 36.738 0.144 ;
    END
  END di0[353]
  PIN di0[354]
    DIRECTION INPUT ;
    USE SIGNAL ;
    PORT
      LAYER M5 ;
        RECT  36.816 0 36.84 0.192 ;
    END
  END di0[354]
  PIN di0[355]
    DIRECTION INPUT ;
    USE SIGNAL ;
    PORT
      LAYER M3 ;
        RECT  36.9 0 36.918 0.144 ;
    END
  END di0[355]
  PIN di0[356]
    DIRECTION INPUT ;
    USE SIGNAL ;
    PORT
      LAYER M5 ;
        RECT  37.008 0 37.032 0.192 ;
    END
  END di0[356]
  PIN di0[357]
    DIRECTION INPUT ;
    USE SIGNAL ;
    PORT
      LAYER M3 ;
        RECT  37.08 0 37.098 0.144 ;
    END
  END di0[357]
  PIN di0[358]
    DIRECTION INPUT ;
    USE SIGNAL ;
    PORT
      LAYER M5 ;
        RECT  37.2 0 37.224 0.192 ;
    END
  END di0[358]
  PIN di0[359]
    DIRECTION INPUT ;
    USE SIGNAL ;
    PORT
      LAYER M3 ;
        RECT  37.26 0 37.278 0.144 ;
    END
  END di0[359]
  PIN di0[35]
    DIRECTION INPUT ;
    USE SIGNAL ;
    PORT
      LAYER M5 ;
        RECT  7.536 0 7.56 0.192 ;
    END
  END di0[35]
  PIN di0[360]
    DIRECTION INPUT ;
    USE SIGNAL ;
    PORT
      LAYER M5 ;
        RECT  37.344 0 37.368 0.192 ;
    END
  END di0[360]
  PIN di0[361]
    DIRECTION INPUT ;
    USE SIGNAL ;
    PORT
      LAYER M3 ;
        RECT  37.44 0 37.458 0.144 ;
    END
  END di0[361]
  PIN di0[362]
    DIRECTION INPUT ;
    USE SIGNAL ;
    PORT
      LAYER M5 ;
        RECT  37.536 0 37.56 0.192 ;
    END
  END di0[362]
  PIN di0[363]
    DIRECTION INPUT ;
    USE SIGNAL ;
    PORT
      LAYER M3 ;
        RECT  37.62 0 37.638 0.144 ;
    END
  END di0[363]
  PIN di0[364]
    DIRECTION INPUT ;
    USE SIGNAL ;
    PORT
      LAYER M5 ;
        RECT  37.728 0 37.752 0.192 ;
    END
  END di0[364]
  PIN di0[365]
    DIRECTION INPUT ;
    USE SIGNAL ;
    PORT
      LAYER M3 ;
        RECT  37.836 0 37.854 0.144 ;
    END
  END di0[365]
  PIN di0[366]
    DIRECTION INPUT ;
    USE SIGNAL ;
    PORT
      LAYER M5 ;
        RECT  37.92 0 37.944 0.192 ;
    END
  END di0[366]
  PIN di0[367]
    DIRECTION INPUT ;
    USE SIGNAL ;
    PORT
      LAYER M3 ;
        RECT  38.016 0 38.034 0.144 ;
    END
  END di0[367]
  PIN di0[368]
    DIRECTION INPUT ;
    USE SIGNAL ;
    PORT
      LAYER M5 ;
        RECT  38.112 0 38.136 0.192 ;
    END
  END di0[368]
  PIN di0[369]
    DIRECTION INPUT ;
    USE SIGNAL ;
    PORT
      LAYER M3 ;
        RECT  38.196 0 38.214 0.144 ;
    END
  END di0[369]
  PIN di0[36]
    DIRECTION INPUT ;
    USE SIGNAL ;
    PORT
      LAYER M3 ;
        RECT  7.632 0 7.65 0.144 ;
    END
  END di0[36]
  PIN di0[370]
    DIRECTION INPUT ;
    USE SIGNAL ;
    PORT
      LAYER M5 ;
        RECT  38.256 0 38.28 0.192 ;
    END
  END di0[370]
  PIN di0[371]
    DIRECTION INPUT ;
    USE SIGNAL ;
    PORT
      LAYER M3 ;
        RECT  38.376 0 38.394 0.144 ;
    END
  END di0[371]
  PIN di0[372]
    DIRECTION INPUT ;
    USE SIGNAL ;
    PORT
      LAYER M5 ;
        RECT  38.448 0 38.472 0.192 ;
    END
  END di0[372]
  PIN di0[373]
    DIRECTION INPUT ;
    USE SIGNAL ;
    PORT
      LAYER M3 ;
        RECT  38.556 0 38.574 0.144 ;
    END
  END di0[373]
  PIN di0[374]
    DIRECTION INPUT ;
    USE SIGNAL ;
    PORT
      LAYER M5 ;
        RECT  38.64 0 38.664 0.192 ;
    END
  END di0[374]
  PIN di0[375]
    DIRECTION INPUT ;
    USE SIGNAL ;
    PORT
      LAYER M3 ;
        RECT  38.736 0 38.754 0.144 ;
    END
  END di0[375]
  PIN di0[376]
    DIRECTION INPUT ;
    USE SIGNAL ;
    PORT
      LAYER M5 ;
        RECT  38.832 0 38.856 0.192 ;
    END
  END di0[376]
  PIN di0[377]
    DIRECTION INPUT ;
    USE SIGNAL ;
    PORT
      LAYER M3 ;
        RECT  38.916 0 38.934 0.144 ;
    END
  END di0[377]
  PIN di0[378]
    DIRECTION INPUT ;
    USE SIGNAL ;
    PORT
      LAYER M5 ;
        RECT  39.024 0 39.048 0.192 ;
    END
  END di0[378]
  PIN di0[379]
    DIRECTION INPUT ;
    USE SIGNAL ;
    PORT
      LAYER M3 ;
        RECT  39.096 0 39.114 0.144 ;
    END
  END di0[379]
  PIN di0[37]
    DIRECTION INPUT ;
    USE SIGNAL ;
    PORT
      LAYER M5 ;
        RECT  7.728 0 7.752 0.192 ;
    END
  END di0[37]
  PIN di0[380]
    DIRECTION INPUT ;
    USE SIGNAL ;
    PORT
      LAYER M5 ;
        RECT  39.168 0 39.192 0.192 ;
    END
  END di0[380]
  PIN di0[381]
    DIRECTION INPUT ;
    USE SIGNAL ;
    PORT
      LAYER M3 ;
        RECT  39.276 0 39.294 0.144 ;
    END
  END di0[381]
  PIN di0[382]
    DIRECTION INPUT ;
    USE SIGNAL ;
    PORT
      LAYER M5 ;
        RECT  39.36 0 39.384 0.192 ;
    END
  END di0[382]
  PIN di0[383]
    DIRECTION INPUT ;
    USE SIGNAL ;
    PORT
      LAYER M3 ;
        RECT  39.456 0 39.474 0.144 ;
    END
  END di0[383]
  PIN di0[384]
    DIRECTION INPUT ;
    USE SIGNAL ;
    PORT
      LAYER M5 ;
        RECT  39.552 0 39.576 0.192 ;
    END
  END di0[384]
  PIN di0[385]
    DIRECTION INPUT ;
    USE SIGNAL ;
    PORT
      LAYER M3 ;
        RECT  39.636 0 39.654 0.144 ;
    END
  END di0[385]
  PIN di0[386]
    DIRECTION INPUT ;
    USE SIGNAL ;
    PORT
      LAYER M5 ;
        RECT  39.744 0 39.768 0.192 ;
    END
  END di0[386]
  PIN di0[387]
    DIRECTION INPUT ;
    USE SIGNAL ;
    PORT
      LAYER M3 ;
        RECT  39.816 0 39.834 0.144 ;
    END
  END di0[387]
  PIN di0[388]
    DIRECTION INPUT ;
    USE SIGNAL ;
    PORT
      LAYER M5 ;
        RECT  39.936 0 39.96 0.192 ;
    END
  END di0[388]
  PIN di0[389]
    DIRECTION INPUT ;
    USE SIGNAL ;
    PORT
      LAYER M3 ;
        RECT  39.996 0 40.014 0.144 ;
    END
  END di0[389]
  PIN di0[38]
    DIRECTION INPUT ;
    USE SIGNAL ;
    PORT
      LAYER M3 ;
        RECT  7.848 0 7.866 0.144 ;
    END
  END di0[38]
  PIN di0[390]
    DIRECTION INPUT ;
    USE SIGNAL ;
    PORT
      LAYER M5 ;
        RECT  40.08 0 40.104 0.192 ;
    END
  END di0[390]
  PIN di0[391]
    DIRECTION INPUT ;
    USE SIGNAL ;
    PORT
      LAYER M3 ;
        RECT  40.212 0 40.23 0.144 ;
    END
  END di0[391]
  PIN di0[392]
    DIRECTION INPUT ;
    USE SIGNAL ;
    PORT
      LAYER M5 ;
        RECT  40.272 0 40.296 0.192 ;
    END
  END di0[392]
  PIN di0[393]
    DIRECTION INPUT ;
    USE SIGNAL ;
    PORT
      LAYER M3 ;
        RECT  40.392 0 40.41 0.144 ;
    END
  END di0[393]
  PIN di0[394]
    DIRECTION INPUT ;
    USE SIGNAL ;
    PORT
      LAYER M5 ;
        RECT  40.464 0 40.488 0.192 ;
    END
  END di0[394]
  PIN di0[395]
    DIRECTION INPUT ;
    USE SIGNAL ;
    PORT
      LAYER M3 ;
        RECT  40.572 0 40.59 0.144 ;
    END
  END di0[395]
  PIN di0[396]
    DIRECTION INPUT ;
    USE SIGNAL ;
    PORT
      LAYER M5 ;
        RECT  40.656 0 40.68 0.192 ;
    END
  END di0[396]
  PIN di0[397]
    DIRECTION INPUT ;
    USE SIGNAL ;
    PORT
      LAYER M3 ;
        RECT  40.752 0 40.77 0.144 ;
    END
  END di0[397]
  PIN di0[398]
    DIRECTION INPUT ;
    USE SIGNAL ;
    PORT
      LAYER M5 ;
        RECT  40.848 0 40.872 0.192 ;
    END
  END di0[398]
  PIN di0[399]
    DIRECTION INPUT ;
    USE SIGNAL ;
    PORT
      LAYER M3 ;
        RECT  40.932 0 40.95 0.144 ;
    END
  END di0[399]
  PIN di0[39]
    DIRECTION INPUT ;
    USE SIGNAL ;
    PORT
      LAYER M5 ;
        RECT  7.92 0 7.944 0.192 ;
    END
  END di0[39]
  PIN di0[3]
    DIRECTION INPUT ;
    USE SIGNAL ;
    PORT
      LAYER M5 ;
        RECT  4.608 0 4.632 0.192 ;
    END
  END di0[3]
  PIN di0[400]
    DIRECTION INPUT ;
    USE SIGNAL ;
    PORT
      LAYER M5 ;
        RECT  41.04 0 41.064 0.192 ;
    END
  END di0[400]
  PIN di0[401]
    DIRECTION INPUT ;
    USE SIGNAL ;
    PORT
      LAYER M3 ;
        RECT  41.112 0 41.13 0.144 ;
    END
  END di0[401]
  PIN di0[402]
    DIRECTION INPUT ;
    USE SIGNAL ;
    PORT
      LAYER M5 ;
        RECT  41.184 0 41.208 0.192 ;
    END
  END di0[402]
  PIN di0[403]
    DIRECTION INPUT ;
    USE SIGNAL ;
    PORT
      LAYER M3 ;
        RECT  41.292 0 41.31 0.144 ;
    END
  END di0[403]
  PIN di0[404]
    DIRECTION INPUT ;
    USE SIGNAL ;
    PORT
      LAYER M5 ;
        RECT  41.376 0 41.4 0.192 ;
    END
  END di0[404]
  PIN di0[405]
    DIRECTION INPUT ;
    USE SIGNAL ;
    PORT
      LAYER M3 ;
        RECT  41.472 0 41.49 0.144 ;
    END
  END di0[405]
  PIN di0[406]
    DIRECTION INPUT ;
    USE SIGNAL ;
    PORT
      LAYER M5 ;
        RECT  41.568 0 41.592 0.192 ;
    END
  END di0[406]
  PIN di0[407]
    DIRECTION INPUT ;
    USE SIGNAL ;
    PORT
      LAYER M3 ;
        RECT  41.652 0 41.67 0.144 ;
    END
  END di0[407]
  PIN di0[408]
    DIRECTION INPUT ;
    USE SIGNAL ;
    PORT
      LAYER M5 ;
        RECT  41.76 0 41.784 0.192 ;
    END
  END di0[408]
  PIN di0[409]
    DIRECTION INPUT ;
    USE SIGNAL ;
    PORT
      LAYER M3 ;
        RECT  41.832 0 41.85 0.144 ;
    END
  END di0[409]
  PIN di0[40]
    DIRECTION INPUT ;
    USE SIGNAL ;
    PORT
      LAYER M3 ;
        RECT  8.028 0 8.046 0.144 ;
    END
  END di0[40]
  PIN di0[410]
    DIRECTION INPUT ;
    USE SIGNAL ;
    PORT
      LAYER M5 ;
        RECT  41.952 0 41.976 0.192 ;
    END
  END di0[410]
  PIN di0[411]
    DIRECTION INPUT ;
    USE SIGNAL ;
    PORT
      LAYER M3 ;
        RECT  42.012 0 42.03 0.144 ;
    END
  END di0[411]
  PIN di0[412]
    DIRECTION INPUT ;
    USE SIGNAL ;
    PORT
      LAYER M5 ;
        RECT  42.096 0 42.12 0.192 ;
    END
  END di0[412]
  PIN di0[413]
    DIRECTION INPUT ;
    USE SIGNAL ;
    PORT
      LAYER M3 ;
        RECT  42.192 0 42.21 0.144 ;
    END
  END di0[413]
  PIN di0[414]
    DIRECTION INPUT ;
    USE SIGNAL ;
    PORT
      LAYER M5 ;
        RECT  42.288 0 42.312 0.192 ;
    END
  END di0[414]
  PIN di0[415]
    DIRECTION INPUT ;
    USE SIGNAL ;
    PORT
      LAYER M3 ;
        RECT  42.408 0 42.426 0.144 ;
    END
  END di0[415]
  PIN di0[416]
    DIRECTION INPUT ;
    USE SIGNAL ;
    PORT
      LAYER M5 ;
        RECT  42.48 0 42.504 0.192 ;
    END
  END di0[416]
  PIN di0[417]
    DIRECTION INPUT ;
    USE SIGNAL ;
    PORT
      LAYER M3 ;
        RECT  42.588 0 42.606 0.144 ;
    END
  END di0[417]
  PIN di0[418]
    DIRECTION INPUT ;
    USE SIGNAL ;
    PORT
      LAYER M5 ;
        RECT  42.672 0 42.696 0.192 ;
    END
  END di0[418]
  PIN di0[419]
    DIRECTION INPUT ;
    USE SIGNAL ;
    PORT
      LAYER M3 ;
        RECT  42.768 0 42.786 0.144 ;
    END
  END di0[419]
  PIN di0[41]
    DIRECTION INPUT ;
    USE SIGNAL ;
    PORT
      LAYER M5 ;
        RECT  8.112 0 8.136 0.192 ;
    END
  END di0[41]
  PIN di0[420]
    DIRECTION INPUT ;
    USE SIGNAL ;
    PORT
      LAYER M5 ;
        RECT  42.864 0 42.888 0.192 ;
    END
  END di0[420]
  PIN di0[421]
    DIRECTION INPUT ;
    USE SIGNAL ;
    PORT
      LAYER M3 ;
        RECT  42.948 0 42.966 0.144 ;
    END
  END di0[421]
  PIN di0[422]
    DIRECTION INPUT ;
    USE SIGNAL ;
    PORT
      LAYER M5 ;
        RECT  43.008 0 43.032 0.192 ;
    END
  END di0[422]
  PIN di0[423]
    DIRECTION INPUT ;
    USE SIGNAL ;
    PORT
      LAYER M3 ;
        RECT  43.128 0 43.146 0.144 ;
    END
  END di0[423]
  PIN di0[424]
    DIRECTION INPUT ;
    USE SIGNAL ;
    PORT
      LAYER M5 ;
        RECT  43.2 0 43.224 0.192 ;
    END
  END di0[424]
  PIN di0[425]
    DIRECTION INPUT ;
    USE SIGNAL ;
    PORT
      LAYER M3 ;
        RECT  43.308 0 43.326 0.144 ;
    END
  END di0[425]
  PIN di0[426]
    DIRECTION INPUT ;
    USE SIGNAL ;
    PORT
      LAYER M5 ;
        RECT  43.392 0 43.416 0.192 ;
    END
  END di0[426]
  PIN di0[427]
    DIRECTION INPUT ;
    USE SIGNAL ;
    PORT
      LAYER M3 ;
        RECT  43.488 0 43.506 0.144 ;
    END
  END di0[427]
  PIN di0[428]
    DIRECTION INPUT ;
    USE SIGNAL ;
    PORT
      LAYER M5 ;
        RECT  43.584 0 43.608 0.192 ;
    END
  END di0[428]
  PIN di0[429]
    DIRECTION INPUT ;
    USE SIGNAL ;
    PORT
      LAYER M3 ;
        RECT  43.668 0 43.686 0.144 ;
    END
  END di0[429]
  PIN di0[42]
    DIRECTION INPUT ;
    USE SIGNAL ;
    PORT
      LAYER M3 ;
        RECT  8.208 0 8.226 0.144 ;
    END
  END di0[42]
  PIN di0[430]
    DIRECTION INPUT ;
    USE SIGNAL ;
    PORT
      LAYER M5 ;
        RECT  43.776 0 43.8 0.192 ;
    END
  END di0[430]
  PIN di0[431]
    DIRECTION INPUT ;
    USE SIGNAL ;
    PORT
      LAYER M3 ;
        RECT  43.848 0 43.866 0.144 ;
    END
  END di0[431]
  PIN di0[432]
    DIRECTION INPUT ;
    USE SIGNAL ;
    PORT
      LAYER M5 ;
        RECT  43.92 0 43.944 0.192 ;
    END
  END di0[432]
  PIN di0[433]
    DIRECTION INPUT ;
    USE SIGNAL ;
    PORT
      LAYER M3 ;
        RECT  44.028 0 44.046 0.144 ;
    END
  END di0[433]
  PIN di0[434]
    DIRECTION INPUT ;
    USE SIGNAL ;
    PORT
      LAYER M5 ;
        RECT  44.112 0 44.136 0.192 ;
    END
  END di0[434]
  PIN di0[435]
    DIRECTION INPUT ;
    USE SIGNAL ;
    PORT
      LAYER M3 ;
        RECT  44.208 0 44.226 0.144 ;
    END
  END di0[435]
  PIN di0[436]
    DIRECTION INPUT ;
    USE SIGNAL ;
    PORT
      LAYER M5 ;
        RECT  44.304 0 44.328 0.192 ;
    END
  END di0[436]
  PIN di0[437]
    DIRECTION INPUT ;
    USE SIGNAL ;
    PORT
      LAYER M3 ;
        RECT  44.388 0 44.406 0.144 ;
    END
  END di0[437]
  PIN di0[438]
    DIRECTION INPUT ;
    USE SIGNAL ;
    PORT
      LAYER M5 ;
        RECT  44.496 0 44.52 0.192 ;
    END
  END di0[438]
  PIN di0[439]
    DIRECTION INPUT ;
    USE SIGNAL ;
    PORT
      LAYER M3 ;
        RECT  44.568 0 44.586 0.144 ;
    END
  END di0[439]
  PIN di0[43]
    DIRECTION INPUT ;
    USE SIGNAL ;
    PORT
      LAYER M5 ;
        RECT  8.304 0 8.328 0.192 ;
    END
  END di0[43]
  PIN di0[440]
    DIRECTION INPUT ;
    USE SIGNAL ;
    PORT
      LAYER M5 ;
        RECT  44.688 0 44.712 0.192 ;
    END
  END di0[440]
  PIN di0[441]
    DIRECTION INPUT ;
    USE SIGNAL ;
    PORT
      LAYER M3 ;
        RECT  44.784 0 44.802 0.144 ;
    END
  END di0[441]
  PIN di0[442]
    DIRECTION INPUT ;
    USE SIGNAL ;
    PORT
      LAYER M5 ;
        RECT  44.88 0 44.904 0.192 ;
    END
  END di0[442]
  PIN di0[443]
    DIRECTION INPUT ;
    USE SIGNAL ;
    PORT
      LAYER M3 ;
        RECT  44.964 0 44.982 0.144 ;
    END
  END di0[443]
  PIN di0[444]
    DIRECTION INPUT ;
    USE SIGNAL ;
    PORT
      LAYER M5 ;
        RECT  45.024 0 45.048 0.192 ;
    END
  END di0[444]
  PIN di0[445]
    DIRECTION INPUT ;
    USE SIGNAL ;
    PORT
      LAYER M3 ;
        RECT  45.144 0 45.162 0.144 ;
    END
  END di0[445]
  PIN di0[446]
    DIRECTION INPUT ;
    USE SIGNAL ;
    PORT
      LAYER M5 ;
        RECT  45.216 0 45.24 0.192 ;
    END
  END di0[446]
  PIN di0[447]
    DIRECTION INPUT ;
    USE SIGNAL ;
    PORT
      LAYER M3 ;
        RECT  45.324 0 45.342 0.144 ;
    END
  END di0[447]
  PIN di0[448]
    DIRECTION INPUT ;
    USE SIGNAL ;
    PORT
      LAYER M5 ;
        RECT  45.408 0 45.432 0.192 ;
    END
  END di0[448]
  PIN di0[449]
    DIRECTION INPUT ;
    USE SIGNAL ;
    PORT
      LAYER M3 ;
        RECT  45.504 0 45.522 0.144 ;
    END
  END di0[449]
  PIN di0[44]
    DIRECTION INPUT ;
    USE SIGNAL ;
    PORT
      LAYER M3 ;
        RECT  8.388 0 8.406 0.144 ;
    END
  END di0[44]
  PIN di0[450]
    DIRECTION INPUT ;
    USE SIGNAL ;
    PORT
      LAYER M5 ;
        RECT  45.6 0 45.624 0.192 ;
    END
  END di0[450]
  PIN di0[451]
    DIRECTION INPUT ;
    USE SIGNAL ;
    PORT
      LAYER M3 ;
        RECT  45.684 0 45.702 0.144 ;
    END
  END di0[451]
  PIN di0[452]
    DIRECTION INPUT ;
    USE SIGNAL ;
    PORT
      LAYER M5 ;
        RECT  45.792 0 45.816 0.192 ;
    END
  END di0[452]
  PIN di0[453]
    DIRECTION INPUT ;
    USE SIGNAL ;
    PORT
      LAYER M3 ;
        RECT  45.864 0 45.882 0.144 ;
    END
  END di0[453]
  PIN di0[454]
    DIRECTION INPUT ;
    USE SIGNAL ;
    PORT
      LAYER M5 ;
        RECT  45.936 0 45.96 0.192 ;
    END
  END di0[454]
  PIN di0[455]
    DIRECTION INPUT ;
    USE SIGNAL ;
    PORT
      LAYER M3 ;
        RECT  46.044 0 46.062 0.144 ;
    END
  END di0[455]
  PIN di0[456]
    DIRECTION INPUT ;
    USE SIGNAL ;
    PORT
      LAYER M5 ;
        RECT  46.128 0 46.152 0.192 ;
    END
  END di0[456]
  PIN di0[457]
    DIRECTION INPUT ;
    USE SIGNAL ;
    PORT
      LAYER M3 ;
        RECT  46.224 0 46.242 0.144 ;
    END
  END di0[457]
  PIN di0[458]
    DIRECTION INPUT ;
    USE SIGNAL ;
    PORT
      LAYER M5 ;
        RECT  46.32 0 46.344 0.192 ;
    END
  END di0[458]
  PIN di0[459]
    DIRECTION INPUT ;
    USE SIGNAL ;
    PORT
      LAYER M3 ;
        RECT  46.404 0 46.422 0.144 ;
    END
  END di0[459]
  PIN di0[45]
    DIRECTION INPUT ;
    USE SIGNAL ;
    PORT
      LAYER M5 ;
        RECT  8.448 0 8.472 0.192 ;
    END
  END di0[45]
  PIN di0[460]
    DIRECTION INPUT ;
    USE SIGNAL ;
    PORT
      LAYER M5 ;
        RECT  46.512 0 46.536 0.192 ;
    END
  END di0[460]
  PIN di0[461]
    DIRECTION INPUT ;
    USE SIGNAL ;
    PORT
      LAYER M3 ;
        RECT  46.584 0 46.602 0.144 ;
    END
  END di0[461]
  PIN di0[462]
    DIRECTION INPUT ;
    USE SIGNAL ;
    PORT
      LAYER M5 ;
        RECT  46.704 0 46.728 0.192 ;
    END
  END di0[462]
  PIN di0[463]
    DIRECTION INPUT ;
    USE SIGNAL ;
    PORT
      LAYER M3 ;
        RECT  46.764 0 46.782 0.144 ;
    END
  END di0[463]
  PIN di0[464]
    DIRECTION INPUT ;
    USE SIGNAL ;
    PORT
      LAYER M5 ;
        RECT  46.848 0 46.872 0.192 ;
    END
  END di0[464]
  PIN di0[465]
    DIRECTION INPUT ;
    USE SIGNAL ;
    PORT
      LAYER M3 ;
        RECT  46.98 0 46.998 0.144 ;
    END
  END di0[465]
  PIN di0[466]
    DIRECTION INPUT ;
    USE SIGNAL ;
    PORT
      LAYER M5 ;
        RECT  47.04 0 47.064 0.192 ;
    END
  END di0[466]
  PIN di0[467]
    DIRECTION INPUT ;
    USE SIGNAL ;
    PORT
      LAYER M3 ;
        RECT  47.16 0 47.178 0.144 ;
    END
  END di0[467]
  PIN di0[468]
    DIRECTION INPUT ;
    USE SIGNAL ;
    PORT
      LAYER M5 ;
        RECT  47.232 0 47.256 0.192 ;
    END
  END di0[468]
  PIN di0[469]
    DIRECTION INPUT ;
    USE SIGNAL ;
    PORT
      LAYER M3 ;
        RECT  47.34 0 47.358 0.144 ;
    END
  END di0[469]
  PIN di0[46]
    DIRECTION INPUT ;
    USE SIGNAL ;
    PORT
      LAYER M3 ;
        RECT  8.568 0 8.586 0.144 ;
    END
  END di0[46]
  PIN di0[470]
    DIRECTION INPUT ;
    USE SIGNAL ;
    PORT
      LAYER M5 ;
        RECT  47.424 0 47.448 0.192 ;
    END
  END di0[470]
  PIN di0[471]
    DIRECTION INPUT ;
    USE SIGNAL ;
    PORT
      LAYER M3 ;
        RECT  47.52 0 47.538 0.144 ;
    END
  END di0[471]
  PIN di0[472]
    DIRECTION INPUT ;
    USE SIGNAL ;
    PORT
      LAYER M5 ;
        RECT  47.616 0 47.64 0.192 ;
    END
  END di0[472]
  PIN di0[473]
    DIRECTION INPUT ;
    USE SIGNAL ;
    PORT
      LAYER M3 ;
        RECT  47.7 0 47.718 0.144 ;
    END
  END di0[473]
  PIN di0[474]
    DIRECTION INPUT ;
    USE SIGNAL ;
    PORT
      LAYER M5 ;
        RECT  47.76 0 47.784 0.192 ;
    END
  END di0[474]
  PIN di0[475]
    DIRECTION INPUT ;
    USE SIGNAL ;
    PORT
      LAYER M3 ;
        RECT  47.88 0 47.898 0.144 ;
    END
  END di0[475]
  PIN di0[476]
    DIRECTION INPUT ;
    USE SIGNAL ;
    PORT
      LAYER M5 ;
        RECT  47.952 0 47.976 0.192 ;
    END
  END di0[476]
  PIN di0[477]
    DIRECTION INPUT ;
    USE SIGNAL ;
    PORT
      LAYER M3 ;
        RECT  48.06 0 48.078 0.144 ;
    END
  END di0[477]
  PIN di0[478]
    DIRECTION INPUT ;
    USE SIGNAL ;
    PORT
      LAYER M5 ;
        RECT  48.144 0 48.168 0.192 ;
    END
  END di0[478]
  PIN di0[479]
    DIRECTION INPUT ;
    USE SIGNAL ;
    PORT
      LAYER M3 ;
        RECT  48.24 0 48.258 0.144 ;
    END
  END di0[479]
  PIN di0[47]
    DIRECTION INPUT ;
    USE SIGNAL ;
    PORT
      LAYER M5 ;
        RECT  8.64 0 8.664 0.192 ;
    END
  END di0[47]
  PIN di0[480]
    DIRECTION INPUT ;
    USE SIGNAL ;
    PORT
      LAYER M5 ;
        RECT  48.336 0 48.36 0.192 ;
    END
  END di0[480]
  PIN di0[481]
    DIRECTION INPUT ;
    USE SIGNAL ;
    PORT
      LAYER M3 ;
        RECT  48.42 0 48.438 0.144 ;
    END
  END di0[481]
  PIN di0[482]
    DIRECTION INPUT ;
    USE SIGNAL ;
    PORT
      LAYER M5 ;
        RECT  48.528 0 48.552 0.192 ;
    END
  END di0[482]
  PIN di0[483]
    DIRECTION INPUT ;
    USE SIGNAL ;
    PORT
      LAYER M3 ;
        RECT  48.6 0 48.618 0.144 ;
    END
  END di0[483]
  PIN di0[484]
    DIRECTION INPUT ;
    USE SIGNAL ;
    PORT
      LAYER M5 ;
        RECT  48.72 0 48.744 0.192 ;
    END
  END di0[484]
  PIN di0[485]
    DIRECTION INPUT ;
    USE SIGNAL ;
    PORT
      LAYER M3 ;
        RECT  48.78 0 48.798 0.144 ;
    END
  END di0[485]
  PIN di0[486]
    DIRECTION INPUT ;
    USE SIGNAL ;
    PORT
      LAYER M5 ;
        RECT  48.864 0 48.888 0.192 ;
    END
  END di0[486]
  PIN di0[487]
    DIRECTION INPUT ;
    USE SIGNAL ;
    PORT
      LAYER M3 ;
        RECT  48.96 0 48.978 0.144 ;
    END
  END di0[487]
  PIN di0[488]
    DIRECTION INPUT ;
    USE SIGNAL ;
    PORT
      LAYER M5 ;
        RECT  49.056 0 49.08 0.192 ;
    END
  END di0[488]
  PIN di0[489]
    DIRECTION INPUT ;
    USE SIGNAL ;
    PORT
      LAYER M3 ;
        RECT  49.14 0 49.158 0.144 ;
    END
  END di0[489]
  PIN di0[48]
    DIRECTION INPUT ;
    USE SIGNAL ;
    PORT
      LAYER M3 ;
        RECT  8.748 0 8.766 0.144 ;
    END
  END di0[48]
  PIN di0[490]
    DIRECTION INPUT ;
    USE SIGNAL ;
    PORT
      LAYER M5 ;
        RECT  49.248 0 49.272 0.192 ;
    END
  END di0[490]
  PIN di0[491]
    DIRECTION INPUT ;
    USE SIGNAL ;
    PORT
      LAYER M3 ;
        RECT  49.356 0 49.374 0.144 ;
    END
  END di0[491]
  PIN di0[492]
    DIRECTION INPUT ;
    USE SIGNAL ;
    PORT
      LAYER M5 ;
        RECT  49.44 0 49.464 0.192 ;
    END
  END di0[492]
  PIN di0[493]
    DIRECTION INPUT ;
    USE SIGNAL ;
    PORT
      LAYER M3 ;
        RECT  49.536 0 49.554 0.144 ;
    END
  END di0[493]
  PIN di0[494]
    DIRECTION INPUT ;
    USE SIGNAL ;
    PORT
      LAYER M5 ;
        RECT  49.632 0 49.656 0.192 ;
    END
  END di0[494]
  PIN di0[495]
    DIRECTION INPUT ;
    USE SIGNAL ;
    PORT
      LAYER M3 ;
        RECT  49.716 0 49.734 0.144 ;
    END
  END di0[495]
  PIN di0[496]
    DIRECTION INPUT ;
    USE SIGNAL ;
    PORT
      LAYER M5 ;
        RECT  49.776 0 49.8 0.192 ;
    END
  END di0[496]
  PIN di0[497]
    DIRECTION INPUT ;
    USE SIGNAL ;
    PORT
      LAYER M3 ;
        RECT  49.896 0 49.914 0.144 ;
    END
  END di0[497]
  PIN di0[498]
    DIRECTION INPUT ;
    USE SIGNAL ;
    PORT
      LAYER M5 ;
        RECT  49.968 0 49.992 0.192 ;
    END
  END di0[498]
  PIN di0[499]
    DIRECTION INPUT ;
    USE SIGNAL ;
    PORT
      LAYER M3 ;
        RECT  50.076 0 50.094 0.144 ;
    END
  END di0[499]
  PIN di0[49]
    DIRECTION INPUT ;
    USE SIGNAL ;
    PORT
      LAYER M5 ;
        RECT  8.832 0 8.856 0.192 ;
    END
  END di0[49]
  PIN di0[4]
    DIRECTION INPUT ;
    USE SIGNAL ;
    PORT
      LAYER M3 ;
        RECT  4.716 0 4.734 0.144 ;
    END
  END di0[4]
  PIN di0[500]
    DIRECTION INPUT ;
    USE SIGNAL ;
    PORT
      LAYER M5 ;
        RECT  50.16 0 50.184 0.192 ;
    END
  END di0[500]
  PIN di0[501]
    DIRECTION INPUT ;
    USE SIGNAL ;
    PORT
      LAYER M3 ;
        RECT  50.256 0 50.274 0.144 ;
    END
  END di0[501]
  PIN di0[502]
    DIRECTION INPUT ;
    USE SIGNAL ;
    PORT
      LAYER M5 ;
        RECT  50.352 0 50.376 0.192 ;
    END
  END di0[502]
  PIN di0[503]
    DIRECTION INPUT ;
    USE SIGNAL ;
    PORT
      LAYER M3 ;
        RECT  50.436 0 50.454 0.144 ;
    END
  END di0[503]
  PIN di0[504]
    DIRECTION INPUT ;
    USE SIGNAL ;
    PORT
      LAYER M5 ;
        RECT  50.544 0 50.568 0.192 ;
    END
  END di0[504]
  PIN di0[505]
    DIRECTION INPUT ;
    USE SIGNAL ;
    PORT
      LAYER M3 ;
        RECT  50.616 0 50.634 0.144 ;
    END
  END di0[505]
  PIN di0[506]
    DIRECTION INPUT ;
    USE SIGNAL ;
    PORT
      LAYER M5 ;
        RECT  50.688 0 50.712 0.192 ;
    END
  END di0[506]
  PIN di0[507]
    DIRECTION INPUT ;
    USE SIGNAL ;
    PORT
      LAYER M3 ;
        RECT  50.796 0 50.814 0.144 ;
    END
  END di0[507]
  PIN di0[508]
    DIRECTION INPUT ;
    USE SIGNAL ;
    PORT
      LAYER M5 ;
        RECT  50.88 0 50.904 0.192 ;
    END
  END di0[508]
  PIN di0[509]
    DIRECTION INPUT ;
    USE SIGNAL ;
    PORT
      LAYER M3 ;
        RECT  50.976 0 50.994 0.144 ;
    END
  END di0[509]
  PIN di0[50]
    DIRECTION INPUT ;
    USE SIGNAL ;
    PORT
      LAYER M3 ;
        RECT  8.928 0 8.946 0.144 ;
    END
  END di0[50]
  PIN di0[510]
    DIRECTION INPUT ;
    USE SIGNAL ;
    PORT
      LAYER M5 ;
        RECT  51.072 0 51.096 0.192 ;
    END
  END di0[510]
  PIN di0[511]
    DIRECTION INPUT ;
    USE SIGNAL ;
    PORT
      LAYER M3 ;
        RECT  51.156 0 51.174 0.144 ;
    END
  END di0[511]
  PIN di0[512]
    DIRECTION INPUT ;
    USE SIGNAL ;
    PORT
      LAYER M5 ;
        RECT  51.264 0 51.288 0.192 ;
    END
  END di0[512]
  PIN di0[513]
    DIRECTION INPUT ;
    USE SIGNAL ;
    PORT
      LAYER M3 ;
        RECT  51.336 0 51.354 0.144 ;
    END
  END di0[513]
  PIN di0[514]
    DIRECTION INPUT ;
    USE SIGNAL ;
    PORT
      LAYER M5 ;
        RECT  51.456 0 51.48 0.192 ;
    END
  END di0[514]
  PIN di0[515]
    DIRECTION INPUT ;
    USE SIGNAL ;
    PORT
      LAYER M3 ;
        RECT  51.516 0 51.534 0.144 ;
    END
  END di0[515]
  PIN di0[516]
    DIRECTION INPUT ;
    USE SIGNAL ;
    PORT
      LAYER M5 ;
        RECT  51.6 0 51.624 0.192 ;
    END
  END di0[516]
  PIN di0[517]
    DIRECTION INPUT ;
    USE SIGNAL ;
    PORT
      LAYER M3 ;
        RECT  51.732 0 51.75 0.144 ;
    END
  END di0[517]
  PIN di0[518]
    DIRECTION INPUT ;
    USE SIGNAL ;
    PORT
      LAYER M5 ;
        RECT  51.792 0 51.816 0.192 ;
    END
  END di0[518]
  PIN di0[519]
    DIRECTION INPUT ;
    USE SIGNAL ;
    PORT
      LAYER M3 ;
        RECT  51.912 0 51.93 0.144 ;
    END
  END di0[519]
  PIN di0[51]
    DIRECTION INPUT ;
    USE SIGNAL ;
    PORT
      LAYER M5 ;
        RECT  9.024 0 9.048 0.192 ;
    END
  END di0[51]
  PIN di0[520]
    DIRECTION INPUT ;
    USE SIGNAL ;
    PORT
      LAYER M5 ;
        RECT  51.984 0 52.008 0.192 ;
    END
  END di0[520]
  PIN di0[521]
    DIRECTION INPUT ;
    USE SIGNAL ;
    PORT
      LAYER M3 ;
        RECT  52.092 0 52.11 0.144 ;
    END
  END di0[521]
  PIN di0[522]
    DIRECTION INPUT ;
    USE SIGNAL ;
    PORT
      LAYER M5 ;
        RECT  52.176 0 52.2 0.192 ;
    END
  END di0[522]
  PIN di0[523]
    DIRECTION INPUT ;
    USE SIGNAL ;
    PORT
      LAYER M3 ;
        RECT  52.272 0 52.29 0.144 ;
    END
  END di0[523]
  PIN di0[524]
    DIRECTION INPUT ;
    USE SIGNAL ;
    PORT
      LAYER M5 ;
        RECT  52.368 0 52.392 0.192 ;
    END
  END di0[524]
  PIN di0[525]
    DIRECTION INPUT ;
    USE SIGNAL ;
    PORT
      LAYER M3 ;
        RECT  52.452 0 52.47 0.144 ;
    END
  END di0[525]
  PIN di0[526]
    DIRECTION INPUT ;
    USE SIGNAL ;
    PORT
      LAYER M5 ;
        RECT  52.56 0 52.584 0.192 ;
    END
  END di0[526]
  PIN di0[527]
    DIRECTION INPUT ;
    USE SIGNAL ;
    PORT
      LAYER M3 ;
        RECT  52.632 0 52.65 0.144 ;
    END
  END di0[527]
  PIN di0[528]
    DIRECTION INPUT ;
    USE SIGNAL ;
    PORT
      LAYER M5 ;
        RECT  52.704 0 52.728 0.192 ;
    END
  END di0[528]
  PIN di0[529]
    DIRECTION INPUT ;
    USE SIGNAL ;
    PORT
      LAYER M3 ;
        RECT  52.812 0 52.83 0.144 ;
    END
  END di0[529]
  PIN di0[52]
    DIRECTION INPUT ;
    USE SIGNAL ;
    PORT
      LAYER M3 ;
        RECT  9.108 0 9.126 0.144 ;
    END
  END di0[52]
  PIN di0[530]
    DIRECTION INPUT ;
    USE SIGNAL ;
    PORT
      LAYER M5 ;
        RECT  52.896 0 52.92 0.192 ;
    END
  END di0[530]
  PIN di0[531]
    DIRECTION INPUT ;
    USE SIGNAL ;
    PORT
      LAYER M3 ;
        RECT  52.992 0 53.01 0.144 ;
    END
  END di0[531]
  PIN di0[532]
    DIRECTION INPUT ;
    USE SIGNAL ;
    PORT
      LAYER M5 ;
        RECT  53.088 0 53.112 0.192 ;
    END
  END di0[532]
  PIN di0[533]
    DIRECTION INPUT ;
    USE SIGNAL ;
    PORT
      LAYER M3 ;
        RECT  53.172 0 53.19 0.144 ;
    END
  END di0[533]
  PIN di0[534]
    DIRECTION INPUT ;
    USE SIGNAL ;
    PORT
      LAYER M5 ;
        RECT  53.28 0 53.304 0.192 ;
    END
  END di0[534]
  PIN di0[535]
    DIRECTION INPUT ;
    USE SIGNAL ;
    PORT
      LAYER M3 ;
        RECT  53.352 0 53.37 0.144 ;
    END
  END di0[535]
  PIN di0[536]
    DIRECTION INPUT ;
    USE SIGNAL ;
    PORT
      LAYER M5 ;
        RECT  53.472 0 53.496 0.192 ;
    END
  END di0[536]
  PIN di0[537]
    DIRECTION INPUT ;
    USE SIGNAL ;
    PORT
      LAYER M3 ;
        RECT  53.532 0 53.55 0.144 ;
    END
  END di0[537]
  PIN di0[538]
    DIRECTION INPUT ;
    USE SIGNAL ;
    PORT
      LAYER M5 ;
        RECT  53.616 0 53.64 0.192 ;
    END
  END di0[538]
  PIN di0[539]
    DIRECTION INPUT ;
    USE SIGNAL ;
    PORT
      LAYER M3 ;
        RECT  53.712 0 53.73 0.144 ;
    END
  END di0[539]
  PIN di0[53]
    DIRECTION INPUT ;
    USE SIGNAL ;
    PORT
      LAYER M5 ;
        RECT  9.216 0 9.24 0.192 ;
    END
  END di0[53]
  PIN di0[540]
    DIRECTION INPUT ;
    USE SIGNAL ;
    PORT
      LAYER M5 ;
        RECT  53.808 0 53.832 0.192 ;
    END
  END di0[540]
  PIN di0[541]
    DIRECTION INPUT ;
    USE SIGNAL ;
    PORT
      LAYER M3 ;
        RECT  53.928 0 53.946 0.144 ;
    END
  END di0[541]
  PIN di0[542]
    DIRECTION INPUT ;
    USE SIGNAL ;
    PORT
      LAYER M5 ;
        RECT  54 0 54.024 0.192 ;
    END
  END di0[542]
  PIN di0[543]
    DIRECTION INPUT ;
    USE SIGNAL ;
    PORT
      LAYER M3 ;
        RECT  54.108 0 54.126 0.144 ;
    END
  END di0[543]
  PIN di0[544]
    DIRECTION INPUT ;
    USE SIGNAL ;
    PORT
      LAYER M5 ;
        RECT  54.192 0 54.216 0.192 ;
    END
  END di0[544]
  PIN di0[545]
    DIRECTION INPUT ;
    USE SIGNAL ;
    PORT
      LAYER M3 ;
        RECT  54.288 0 54.306 0.144 ;
    END
  END di0[545]
  PIN di0[546]
    DIRECTION INPUT ;
    USE SIGNAL ;
    PORT
      LAYER M5 ;
        RECT  54.384 0 54.408 0.192 ;
    END
  END di0[546]
  PIN di0[547]
    DIRECTION INPUT ;
    USE SIGNAL ;
    PORT
      LAYER M3 ;
        RECT  54.468 0 54.486 0.144 ;
    END
  END di0[547]
  PIN di0[548]
    DIRECTION INPUT ;
    USE SIGNAL ;
    PORT
      LAYER M5 ;
        RECT  54.528 0 54.552 0.192 ;
    END
  END di0[548]
  PIN di0[549]
    DIRECTION INPUT ;
    USE SIGNAL ;
    PORT
      LAYER M3 ;
        RECT  54.648 0 54.666 0.144 ;
    END
  END di0[549]
  PIN di0[54]
    DIRECTION INPUT ;
    USE SIGNAL ;
    PORT
      LAYER M3 ;
        RECT  9.288 0 9.306 0.144 ;
    END
  END di0[54]
  PIN di0[550]
    DIRECTION INPUT ;
    USE SIGNAL ;
    PORT
      LAYER M5 ;
        RECT  54.72 0 54.744 0.192 ;
    END
  END di0[550]
  PIN di0[551]
    DIRECTION INPUT ;
    USE SIGNAL ;
    PORT
      LAYER M3 ;
        RECT  54.828 0 54.846 0.144 ;
    END
  END di0[551]
  PIN di0[552]
    DIRECTION INPUT ;
    USE SIGNAL ;
    PORT
      LAYER M5 ;
        RECT  54.912 0 54.936 0.192 ;
    END
  END di0[552]
  PIN di0[553]
    DIRECTION INPUT ;
    USE SIGNAL ;
    PORT
      LAYER M3 ;
        RECT  55.008 0 55.026 0.144 ;
    END
  END di0[553]
  PIN di0[554]
    DIRECTION INPUT ;
    USE SIGNAL ;
    PORT
      LAYER M5 ;
        RECT  55.104 0 55.128 0.192 ;
    END
  END di0[554]
  PIN di0[555]
    DIRECTION INPUT ;
    USE SIGNAL ;
    PORT
      LAYER M3 ;
        RECT  55.188 0 55.206 0.144 ;
    END
  END di0[555]
  PIN di0[556]
    DIRECTION INPUT ;
    USE SIGNAL ;
    PORT
      LAYER M5 ;
        RECT  55.296 0 55.32 0.192 ;
    END
  END di0[556]
  PIN di0[557]
    DIRECTION INPUT ;
    USE SIGNAL ;
    PORT
      LAYER M3 ;
        RECT  55.368 0 55.386 0.144 ;
    END
  END di0[557]
  PIN di0[558]
    DIRECTION INPUT ;
    USE SIGNAL ;
    PORT
      LAYER M5 ;
        RECT  55.44 0 55.464 0.192 ;
    END
  END di0[558]
  PIN di0[559]
    DIRECTION INPUT ;
    USE SIGNAL ;
    PORT
      LAYER M3 ;
        RECT  55.548 0 55.566 0.144 ;
    END
  END di0[559]
  PIN di0[55]
    DIRECTION INPUT ;
    USE SIGNAL ;
    PORT
      LAYER M5 ;
        RECT  9.36 0 9.384 0.192 ;
    END
  END di0[55]
  PIN di0[560]
    DIRECTION INPUT ;
    USE SIGNAL ;
    PORT
      LAYER M5 ;
        RECT  55.632 0 55.656 0.192 ;
    END
  END di0[560]
  PIN di0[561]
    DIRECTION INPUT ;
    USE SIGNAL ;
    PORT
      LAYER M3 ;
        RECT  55.728 0 55.746 0.144 ;
    END
  END di0[561]
  PIN di0[562]
    DIRECTION INPUT ;
    USE SIGNAL ;
    PORT
      LAYER M5 ;
        RECT  55.824 0 55.848 0.192 ;
    END
  END di0[562]
  PIN di0[563]
    DIRECTION INPUT ;
    USE SIGNAL ;
    PORT
      LAYER M3 ;
        RECT  55.908 0 55.926 0.144 ;
    END
  END di0[563]
  PIN di0[564]
    DIRECTION INPUT ;
    USE SIGNAL ;
    PORT
      LAYER M5 ;
        RECT  56.016 0 56.04 0.192 ;
    END
  END di0[564]
  PIN di0[565]
    DIRECTION INPUT ;
    USE SIGNAL ;
    PORT
      LAYER M3 ;
        RECT  56.088 0 56.106 0.144 ;
    END
  END di0[565]
  PIN di0[56]
    DIRECTION INPUT ;
    USE SIGNAL ;
    PORT
      LAYER M3 ;
        RECT  9.468 0 9.486 0.144 ;
    END
  END di0[56]
  PIN di0[57]
    DIRECTION INPUT ;
    USE SIGNAL ;
    PORT
      LAYER M5 ;
        RECT  9.552 0 9.576 0.192 ;
    END
  END di0[57]
  PIN di0[58]
    DIRECTION INPUT ;
    USE SIGNAL ;
    PORT
      LAYER M3 ;
        RECT  9.648 0 9.666 0.144 ;
    END
  END di0[58]
  PIN di0[59]
    DIRECTION INPUT ;
    USE SIGNAL ;
    PORT
      LAYER M5 ;
        RECT  9.744 0 9.768 0.192 ;
    END
  END di0[59]
  PIN di0[5]
    DIRECTION INPUT ;
    USE SIGNAL ;
    PORT
      LAYER M5 ;
        RECT  4.8 0 4.824 0.192 ;
    END
  END di0[5]
  PIN di0[60]
    DIRECTION INPUT ;
    USE SIGNAL ;
    PORT
      LAYER M3 ;
        RECT  9.828 0 9.846 0.144 ;
    END
  END di0[60]
  PIN di0[61]
    DIRECTION INPUT ;
    USE SIGNAL ;
    PORT
      LAYER M5 ;
        RECT  9.936 0 9.96 0.192 ;
    END
  END di0[61]
  PIN di0[62]
    DIRECTION INPUT ;
    USE SIGNAL ;
    PORT
      LAYER M3 ;
        RECT  10.008 0 10.026 0.144 ;
    END
  END di0[62]
  PIN di0[63]
    DIRECTION INPUT ;
    USE SIGNAL ;
    PORT
      LAYER M5 ;
        RECT  10.128 0 10.152 0.192 ;
    END
  END di0[63]
  PIN di0[64]
    DIRECTION INPUT ;
    USE SIGNAL ;
    PORT
      LAYER M3 ;
        RECT  10.224 0 10.242 0.144 ;
    END
  END di0[64]
  PIN di0[65]
    DIRECTION INPUT ;
    USE SIGNAL ;
    PORT
      LAYER M5 ;
        RECT  10.32 0 10.344 0.192 ;
    END
  END di0[65]
  PIN di0[66]
    DIRECTION INPUT ;
    USE SIGNAL ;
    PORT
      LAYER M3 ;
        RECT  10.404 0 10.422 0.144 ;
    END
  END di0[66]
  PIN di0[67]
    DIRECTION INPUT ;
    USE SIGNAL ;
    PORT
      LAYER M5 ;
        RECT  10.464 0 10.488 0.192 ;
    END
  END di0[67]
  PIN di0[68]
    DIRECTION INPUT ;
    USE SIGNAL ;
    PORT
      LAYER M3 ;
        RECT  10.584 0 10.602 0.144 ;
    END
  END di0[68]
  PIN di0[69]
    DIRECTION INPUT ;
    USE SIGNAL ;
    PORT
      LAYER M5 ;
        RECT  10.656 0 10.68 0.192 ;
    END
  END di0[69]
  PIN di0[6]
    DIRECTION INPUT ;
    USE SIGNAL ;
    PORT
      LAYER M3 ;
        RECT  4.896 0 4.914 0.144 ;
    END
  END di0[6]
  PIN di0[70]
    DIRECTION INPUT ;
    USE SIGNAL ;
    PORT
      LAYER M3 ;
        RECT  10.764 0 10.782 0.144 ;
    END
  END di0[70]
  PIN di0[71]
    DIRECTION INPUT ;
    USE SIGNAL ;
    PORT
      LAYER M5 ;
        RECT  10.848 0 10.872 0.192 ;
    END
  END di0[71]
  PIN di0[72]
    DIRECTION INPUT ;
    USE SIGNAL ;
    PORT
      LAYER M3 ;
        RECT  10.944 0 10.962 0.144 ;
    END
  END di0[72]
  PIN di0[73]
    DIRECTION INPUT ;
    USE SIGNAL ;
    PORT
      LAYER M5 ;
        RECT  11.04 0 11.064 0.192 ;
    END
  END di0[73]
  PIN di0[74]
    DIRECTION INPUT ;
    USE SIGNAL ;
    PORT
      LAYER M3 ;
        RECT  11.124 0 11.142 0.144 ;
    END
  END di0[74]
  PIN di0[75]
    DIRECTION INPUT ;
    USE SIGNAL ;
    PORT
      LAYER M5 ;
        RECT  11.232 0 11.256 0.192 ;
    END
  END di0[75]
  PIN di0[76]
    DIRECTION INPUT ;
    USE SIGNAL ;
    PORT
      LAYER M3 ;
        RECT  11.304 0 11.322 0.144 ;
    END
  END di0[76]
  PIN di0[77]
    DIRECTION INPUT ;
    USE SIGNAL ;
    PORT
      LAYER M5 ;
        RECT  11.376 0 11.4 0.192 ;
    END
  END di0[77]
  PIN di0[78]
    DIRECTION INPUT ;
    USE SIGNAL ;
    PORT
      LAYER M3 ;
        RECT  11.484 0 11.502 0.144 ;
    END
  END di0[78]
  PIN di0[79]
    DIRECTION INPUT ;
    USE SIGNAL ;
    PORT
      LAYER M5 ;
        RECT  11.568 0 11.592 0.192 ;
    END
  END di0[79]
  PIN di0[7]
    DIRECTION INPUT ;
    USE SIGNAL ;
    PORT
      LAYER M5 ;
        RECT  4.992 0 5.016 0.192 ;
    END
  END di0[7]
  PIN di0[80]
    DIRECTION INPUT ;
    USE SIGNAL ;
    PORT
      LAYER M3 ;
        RECT  11.664 0 11.682 0.144 ;
    END
  END di0[80]
  PIN di0[81]
    DIRECTION INPUT ;
    USE SIGNAL ;
    PORT
      LAYER M5 ;
        RECT  11.76 0 11.784 0.192 ;
    END
  END di0[81]
  PIN di0[82]
    DIRECTION INPUT ;
    USE SIGNAL ;
    PORT
      LAYER M3 ;
        RECT  11.844 0 11.862 0.144 ;
    END
  END di0[82]
  PIN di0[83]
    DIRECTION INPUT ;
    USE SIGNAL ;
    PORT
      LAYER M5 ;
        RECT  11.952 0 11.976 0.192 ;
    END
  END di0[83]
  PIN di0[84]
    DIRECTION INPUT ;
    USE SIGNAL ;
    PORT
      LAYER M3 ;
        RECT  12.024 0 12.042 0.144 ;
    END
  END di0[84]
  PIN di0[85]
    DIRECTION INPUT ;
    USE SIGNAL ;
    PORT
      LAYER M5 ;
        RECT  12.144 0 12.168 0.192 ;
    END
  END di0[85]
  PIN di0[86]
    DIRECTION INPUT ;
    USE SIGNAL ;
    PORT
      LAYER M3 ;
        RECT  12.204 0 12.222 0.144 ;
    END
  END di0[86]
  PIN di0[87]
    DIRECTION INPUT ;
    USE SIGNAL ;
    PORT
      LAYER M5 ;
        RECT  12.288 0 12.312 0.192 ;
    END
  END di0[87]
  PIN di0[88]
    DIRECTION INPUT ;
    USE SIGNAL ;
    PORT
      LAYER M3 ;
        RECT  12.42 0 12.438 0.144 ;
    END
  END di0[88]
  PIN di0[89]
    DIRECTION INPUT ;
    USE SIGNAL ;
    PORT
      LAYER M5 ;
        RECT  12.48 0 12.504 0.192 ;
    END
  END di0[89]
  PIN di0[8]
    DIRECTION INPUT ;
    USE SIGNAL ;
    PORT
      LAYER M3 ;
        RECT  5.076 0 5.094 0.144 ;
    END
  END di0[8]
  PIN di0[90]
    DIRECTION INPUT ;
    USE SIGNAL ;
    PORT
      LAYER M3 ;
        RECT  12.6 0 12.618 0.144 ;
    END
  END di0[90]
  PIN di0[91]
    DIRECTION INPUT ;
    USE SIGNAL ;
    PORT
      LAYER M5 ;
        RECT  12.672 0 12.696 0.192 ;
    END
  END di0[91]
  PIN di0[92]
    DIRECTION INPUT ;
    USE SIGNAL ;
    PORT
      LAYER M3 ;
        RECT  12.78 0 12.798 0.144 ;
    END
  END di0[92]
  PIN di0[93]
    DIRECTION INPUT ;
    USE SIGNAL ;
    PORT
      LAYER M5 ;
        RECT  12.864 0 12.888 0.192 ;
    END
  END di0[93]
  PIN di0[94]
    DIRECTION INPUT ;
    USE SIGNAL ;
    PORT
      LAYER M3 ;
        RECT  12.96 0 12.978 0.144 ;
    END
  END di0[94]
  PIN di0[95]
    DIRECTION INPUT ;
    USE SIGNAL ;
    PORT
      LAYER M5 ;
        RECT  13.056 0 13.08 0.192 ;
    END
  END di0[95]
  PIN di0[96]
    DIRECTION INPUT ;
    USE SIGNAL ;
    PORT
      LAYER M3 ;
        RECT  13.14 0 13.158 0.144 ;
    END
  END di0[96]
  PIN di0[97]
    DIRECTION INPUT ;
    USE SIGNAL ;
    PORT
      LAYER M5 ;
        RECT  13.2 0 13.224 0.192 ;
    END
  END di0[97]
  PIN di0[98]
    DIRECTION INPUT ;
    USE SIGNAL ;
    PORT
      LAYER M3 ;
        RECT  13.32 0 13.338 0.144 ;
    END
  END di0[98]
  PIN di0[99]
    DIRECTION INPUT ;
    USE SIGNAL ;
    PORT
      LAYER M5 ;
        RECT  13.392 0 13.416 0.192 ;
    END
  END di0[99]
  PIN di0[9]
    DIRECTION INPUT ;
    USE SIGNAL ;
    PORT
      LAYER M5 ;
        RECT  5.184 0 5.208 0.192 ;
    END
  END di0[9]
  PIN do0[0]
    DIRECTION OUTPUT ;
    USE SIGNAL ;
    PORT
      LAYER M3 ;
        RECT  4.356 25.776 4.374 25.92 ;
    END
  END do0[0]
  PIN do0[100]
    DIRECTION OUTPUT ;
    USE SIGNAL ;
    PORT
      LAYER M3 ;
        RECT  13.5 25.776 13.518 25.92 ;
    END
  END do0[100]
  PIN do0[101]
    DIRECTION OUTPUT ;
    USE SIGNAL ;
    PORT
      LAYER M5 ;
        RECT  13.584 25.728 13.608 25.92 ;
    END
  END do0[101]
  PIN do0[102]
    DIRECTION OUTPUT ;
    USE SIGNAL ;
    PORT
      LAYER M3 ;
        RECT  13.68 25.776 13.698 25.92 ;
    END
  END do0[102]
  PIN do0[103]
    DIRECTION OUTPUT ;
    USE SIGNAL ;
    PORT
      LAYER M5 ;
        RECT  13.776 25.728 13.8 25.92 ;
    END
  END do0[103]
  PIN do0[104]
    DIRECTION OUTPUT ;
    USE SIGNAL ;
    PORT
      LAYER M3 ;
        RECT  13.86 25.776 13.878 25.92 ;
    END
  END do0[104]
  PIN do0[105]
    DIRECTION OUTPUT ;
    USE SIGNAL ;
    PORT
      LAYER M5 ;
        RECT  13.92 25.728 13.944 25.92 ;
    END
  END do0[105]
  PIN do0[106]
    DIRECTION OUTPUT ;
    USE SIGNAL ;
    PORT
      LAYER M3 ;
        RECT  14.04 25.776 14.058 25.92 ;
    END
  END do0[106]
  PIN do0[107]
    DIRECTION OUTPUT ;
    USE SIGNAL ;
    PORT
      LAYER M5 ;
        RECT  14.112 25.728 14.136 25.92 ;
    END
  END do0[107]
  PIN do0[108]
    DIRECTION OUTPUT ;
    USE SIGNAL ;
    PORT
      LAYER M3 ;
        RECT  14.22 25.776 14.238 25.92 ;
    END
  END do0[108]
  PIN do0[109]
    DIRECTION OUTPUT ;
    USE SIGNAL ;
    PORT
      LAYER M5 ;
        RECT  14.304 25.728 14.328 25.92 ;
    END
  END do0[109]
  PIN do0[10]
    DIRECTION OUTPUT ;
    USE SIGNAL ;
    PORT
      LAYER M3 ;
        RECT  5.256 25.776 5.274 25.92 ;
    END
  END do0[10]
  PIN do0[110]
    DIRECTION OUTPUT ;
    USE SIGNAL ;
    PORT
      LAYER M3 ;
        RECT  14.4 25.776 14.418 25.92 ;
    END
  END do0[110]
  PIN do0[111]
    DIRECTION OUTPUT ;
    USE SIGNAL ;
    PORT
      LAYER M5 ;
        RECT  14.496 25.728 14.52 25.92 ;
    END
  END do0[111]
  PIN do0[112]
    DIRECTION OUTPUT ;
    USE SIGNAL ;
    PORT
      LAYER M3 ;
        RECT  14.58 25.776 14.598 25.92 ;
    END
  END do0[112]
  PIN do0[113]
    DIRECTION OUTPUT ;
    USE SIGNAL ;
    PORT
      LAYER M5 ;
        RECT  14.688 25.728 14.712 25.92 ;
    END
  END do0[113]
  PIN do0[114]
    DIRECTION OUTPUT ;
    USE SIGNAL ;
    PORT
      LAYER M3 ;
        RECT  14.76 25.776 14.778 25.92 ;
    END
  END do0[114]
  PIN do0[115]
    DIRECTION OUTPUT ;
    USE SIGNAL ;
    PORT
      LAYER M5 ;
        RECT  14.832 25.728 14.856 25.92 ;
    END
  END do0[115]
  PIN do0[116]
    DIRECTION OUTPUT ;
    USE SIGNAL ;
    PORT
      LAYER M3 ;
        RECT  14.94 25.776 14.958 25.92 ;
    END
  END do0[116]
  PIN do0[117]
    DIRECTION OUTPUT ;
    USE SIGNAL ;
    PORT
      LAYER M5 ;
        RECT  15.024 25.728 15.048 25.92 ;
    END
  END do0[117]
  PIN do0[118]
    DIRECTION OUTPUT ;
    USE SIGNAL ;
    PORT
      LAYER M3 ;
        RECT  15.12 25.776 15.138 25.92 ;
    END
  END do0[118]
  PIN do0[119]
    DIRECTION OUTPUT ;
    USE SIGNAL ;
    PORT
      LAYER M5 ;
        RECT  15.216 25.728 15.24 25.92 ;
    END
  END do0[119]
  PIN do0[11]
    DIRECTION OUTPUT ;
    USE SIGNAL ;
    PORT
      LAYER M5 ;
        RECT  5.376 25.728 5.4 25.92 ;
    END
  END do0[11]
  PIN do0[120]
    DIRECTION OUTPUT ;
    USE SIGNAL ;
    PORT
      LAYER M3 ;
        RECT  15.3 25.776 15.318 25.92 ;
    END
    PORT
      LAYER M3 ;
        RECT  15.228 25.788 15.354 25.853 ;
    END
  END do0[120]
  PIN do0[121]
    DIRECTION OUTPUT ;
    USE SIGNAL ;
    PORT
      LAYER M5 ;
        RECT  15.408 25.728 15.432 25.92 ;
    END
  END do0[121]
  PIN do0[122]
    DIRECTION OUTPUT ;
    USE SIGNAL ;
    PORT
      LAYER M3 ;
        RECT  15.48 25.776 15.498 25.92 ;
    END
  END do0[122]
  PIN do0[123]
    DIRECTION OUTPUT ;
    USE SIGNAL ;
    PORT
      LAYER M5 ;
        RECT  15.6 25.728 15.624 25.92 ;
    END
  END do0[123]
  PIN do0[124]
    DIRECTION OUTPUT ;
    USE SIGNAL ;
    PORT
      LAYER M3 ;
        RECT  15.66 25.776 15.678 25.92 ;
    END
  END do0[124]
  PIN do0[125]
    DIRECTION OUTPUT ;
    USE SIGNAL ;
    PORT
      LAYER M5 ;
        RECT  15.744 25.728 15.768 25.92 ;
    END
  END do0[125]
  PIN do0[126]
    DIRECTION OUTPUT ;
    USE SIGNAL ;
    PORT
      LAYER M3 ;
        RECT  15.84 25.776 15.858 25.92 ;
    END
  END do0[126]
  PIN do0[127]
    DIRECTION OUTPUT ;
    USE SIGNAL ;
    PORT
      LAYER M5 ;
        RECT  15.936 25.728 15.96 25.92 ;
    END
  END do0[127]
  PIN do0[128]
    DIRECTION OUTPUT ;
    USE SIGNAL ;
    PORT
      LAYER M3 ;
        RECT  16.056 25.776 16.074 25.92 ;
    END
  END do0[128]
  PIN do0[129]
    DIRECTION OUTPUT ;
    USE SIGNAL ;
    PORT
      LAYER M5 ;
        RECT  16.128 25.728 16.152 25.92 ;
    END
  END do0[129]
  PIN do0[12]
    DIRECTION OUTPUT ;
    USE SIGNAL ;
    PORT
      LAYER M3 ;
        RECT  5.436 25.776 5.454 25.92 ;
    END
  END do0[12]
  PIN do0[130]
    DIRECTION OUTPUT ;
    USE SIGNAL ;
    PORT
      LAYER M3 ;
        RECT  16.236 25.776 16.254 25.92 ;
    END
  END do0[130]
  PIN do0[131]
    DIRECTION OUTPUT ;
    USE SIGNAL ;
    PORT
      LAYER M5 ;
        RECT  16.32 25.728 16.344 25.92 ;
    END
  END do0[131]
  PIN do0[132]
    DIRECTION OUTPUT ;
    USE SIGNAL ;
    PORT
      LAYER M3 ;
        RECT  16.416 25.776 16.434 25.92 ;
    END
  END do0[132]
  PIN do0[133]
    DIRECTION OUTPUT ;
    USE SIGNAL ;
    PORT
      LAYER M5 ;
        RECT  16.512 25.728 16.536 25.92 ;
    END
  END do0[133]
  PIN do0[134]
    DIRECTION OUTPUT ;
    USE SIGNAL ;
    PORT
      LAYER M3 ;
        RECT  16.596 25.776 16.614 25.92 ;
    END
  END do0[134]
  PIN do0[135]
    DIRECTION OUTPUT ;
    USE SIGNAL ;
    PORT
      LAYER M5 ;
        RECT  16.656 25.728 16.68 25.92 ;
    END
  END do0[135]
  PIN do0[136]
    DIRECTION OUTPUT ;
    USE SIGNAL ;
    PORT
      LAYER M3 ;
        RECT  16.776 25.776 16.794 25.92 ;
    END
  END do0[136]
  PIN do0[137]
    DIRECTION OUTPUT ;
    USE SIGNAL ;
    PORT
      LAYER M5 ;
        RECT  16.848 25.728 16.872 25.92 ;
    END
  END do0[137]
  PIN do0[138]
    DIRECTION OUTPUT ;
    USE SIGNAL ;
    PORT
      LAYER M3 ;
        RECT  16.956 25.776 16.974 25.92 ;
    END
  END do0[138]
  PIN do0[139]
    DIRECTION OUTPUT ;
    USE SIGNAL ;
    PORT
      LAYER M5 ;
        RECT  17.04 25.728 17.064 25.92 ;
    END
  END do0[139]
  PIN do0[13]
    DIRECTION OUTPUT ;
    USE SIGNAL ;
    PORT
      LAYER M5 ;
        RECT  5.52 25.728 5.544 25.92 ;
    END
  END do0[13]
  PIN do0[140]
    DIRECTION OUTPUT ;
    USE SIGNAL ;
    PORT
      LAYER M3 ;
        RECT  17.136 25.776 17.154 25.92 ;
    END
  END do0[140]
  PIN do0[141]
    DIRECTION OUTPUT ;
    USE SIGNAL ;
    PORT
      LAYER M5 ;
        RECT  17.232 25.728 17.256 25.92 ;
    END
  END do0[141]
  PIN do0[142]
    DIRECTION OUTPUT ;
    USE SIGNAL ;
    PORT
      LAYER M3 ;
        RECT  17.316 25.776 17.334 25.92 ;
    END
  END do0[142]
  PIN do0[143]
    DIRECTION OUTPUT ;
    USE SIGNAL ;
    PORT
      LAYER M5 ;
        RECT  17.424 25.728 17.448 25.92 ;
    END
  END do0[143]
  PIN do0[144]
    DIRECTION OUTPUT ;
    USE SIGNAL ;
    PORT
      LAYER M3 ;
        RECT  17.496 25.776 17.514 25.92 ;
    END
  END do0[144]
  PIN do0[145]
    DIRECTION OUTPUT ;
    USE SIGNAL ;
    PORT
      LAYER M5 ;
        RECT  17.568 25.728 17.592 25.92 ;
    END
  END do0[145]
  PIN do0[146]
    DIRECTION OUTPUT ;
    USE SIGNAL ;
    PORT
      LAYER M3 ;
        RECT  17.676 25.776 17.694 25.92 ;
    END
  END do0[146]
  PIN do0[147]
    DIRECTION OUTPUT ;
    USE SIGNAL ;
    PORT
      LAYER M5 ;
        RECT  17.76 25.728 17.784 25.92 ;
    END
  END do0[147]
  PIN do0[148]
    DIRECTION OUTPUT ;
    USE SIGNAL ;
    PORT
      LAYER M3 ;
        RECT  17.856 25.776 17.874 25.92 ;
    END
  END do0[148]
  PIN do0[149]
    DIRECTION OUTPUT ;
    USE SIGNAL ;
    PORT
      LAYER M5 ;
        RECT  17.952 25.728 17.976 25.92 ;
    END
  END do0[149]
  PIN do0[14]
    DIRECTION OUTPUT ;
    USE SIGNAL ;
    PORT
      LAYER M3 ;
        RECT  5.652 25.776 5.67 25.92 ;
    END
  END do0[14]
  PIN do0[150]
    DIRECTION OUTPUT ;
    USE SIGNAL ;
    PORT
      LAYER M3 ;
        RECT  18.036 25.776 18.054 25.92 ;
    END
  END do0[150]
  PIN do0[151]
    DIRECTION OUTPUT ;
    USE SIGNAL ;
    PORT
      LAYER M5 ;
        RECT  18.144 25.728 18.168 25.92 ;
    END
  END do0[151]
  PIN do0[152]
    DIRECTION OUTPUT ;
    USE SIGNAL ;
    PORT
      LAYER M3 ;
        RECT  18.216 25.776 18.234 25.92 ;
    END
  END do0[152]
  PIN do0[153]
    DIRECTION OUTPUT ;
    USE SIGNAL ;
    PORT
      LAYER M5 ;
        RECT  18.336 25.728 18.36 25.92 ;
    END
  END do0[153]
  PIN do0[154]
    DIRECTION OUTPUT ;
    USE SIGNAL ;
    PORT
      LAYER M3 ;
        RECT  18.396 25.776 18.414 25.92 ;
    END
  END do0[154]
  PIN do0[155]
    DIRECTION OUTPUT ;
    USE SIGNAL ;
    PORT
      LAYER M5 ;
        RECT  18.48 25.728 18.504 25.92 ;
    END
  END do0[155]
  PIN do0[156]
    DIRECTION OUTPUT ;
    USE SIGNAL ;
    PORT
      LAYER M3 ;
        RECT  18.612 25.776 18.63 25.92 ;
    END
  END do0[156]
  PIN do0[157]
    DIRECTION OUTPUT ;
    USE SIGNAL ;
    PORT
      LAYER M5 ;
        RECT  18.672 25.728 18.696 25.92 ;
    END
  END do0[157]
  PIN do0[158]
    DIRECTION OUTPUT ;
    USE SIGNAL ;
    PORT
      LAYER M3 ;
        RECT  18.792 25.776 18.81 25.92 ;
    END
  END do0[158]
  PIN do0[159]
    DIRECTION OUTPUT ;
    USE SIGNAL ;
    PORT
      LAYER M5 ;
        RECT  18.864 25.728 18.888 25.92 ;
    END
  END do0[159]
  PIN do0[15]
    DIRECTION OUTPUT ;
    USE SIGNAL ;
    PORT
      LAYER M5 ;
        RECT  5.712 25.728 5.736 25.92 ;
    END
  END do0[15]
  PIN do0[160]
    DIRECTION OUTPUT ;
    USE SIGNAL ;
    PORT
      LAYER M3 ;
        RECT  18.972 25.776 18.99 25.92 ;
    END
  END do0[160]
  PIN do0[161]
    DIRECTION OUTPUT ;
    USE SIGNAL ;
    PORT
      LAYER M5 ;
        RECT  19.056 25.728 19.08 25.92 ;
    END
  END do0[161]
  PIN do0[162]
    DIRECTION OUTPUT ;
    USE SIGNAL ;
    PORT
      LAYER M3 ;
        RECT  19.152 25.776 19.17 25.92 ;
    END
  END do0[162]
  PIN do0[163]
    DIRECTION OUTPUT ;
    USE SIGNAL ;
    PORT
      LAYER M5 ;
        RECT  19.248 25.728 19.272 25.92 ;
    END
  END do0[163]
  PIN do0[164]
    DIRECTION OUTPUT ;
    USE SIGNAL ;
    PORT
      LAYER M3 ;
        RECT  19.332 25.776 19.35 25.92 ;
    END
  END do0[164]
  PIN do0[165]
    DIRECTION OUTPUT ;
    USE SIGNAL ;
    PORT
      LAYER M5 ;
        RECT  19.392 25.728 19.416 25.92 ;
    END
  END do0[165]
  PIN do0[166]
    DIRECTION OUTPUT ;
    USE SIGNAL ;
    PORT
      LAYER M3 ;
        RECT  19.512 25.776 19.53 25.92 ;
    END
  END do0[166]
  PIN do0[167]
    DIRECTION OUTPUT ;
    USE SIGNAL ;
    PORT
      LAYER M5 ;
        RECT  19.584 25.728 19.608 25.92 ;
    END
  END do0[167]
  PIN do0[168]
    DIRECTION OUTPUT ;
    USE SIGNAL ;
    PORT
      LAYER M3 ;
        RECT  19.692 25.776 19.71 25.92 ;
    END
  END do0[168]
  PIN do0[169]
    DIRECTION OUTPUT ;
    USE SIGNAL ;
    PORT
      LAYER M5 ;
        RECT  19.776 25.728 19.8 25.92 ;
    END
  END do0[169]
  PIN do0[16]
    DIRECTION OUTPUT ;
    USE SIGNAL ;
    PORT
      LAYER M3 ;
        RECT  5.832 25.776 5.85 25.92 ;
    END
  END do0[16]
  PIN do0[170]
    DIRECTION OUTPUT ;
    USE SIGNAL ;
    PORT
      LAYER M3 ;
        RECT  19.872 25.776 19.89 25.92 ;
    END
  END do0[170]
  PIN do0[171]
    DIRECTION OUTPUT ;
    USE SIGNAL ;
    PORT
      LAYER M5 ;
        RECT  19.968 25.728 19.992 25.92 ;
    END
  END do0[171]
  PIN do0[172]
    DIRECTION OUTPUT ;
    USE SIGNAL ;
    PORT
      LAYER M3 ;
        RECT  20.052 25.776 20.07 25.92 ;
    END
  END do0[172]
  PIN do0[173]
    DIRECTION OUTPUT ;
    USE SIGNAL ;
    PORT
      LAYER M5 ;
        RECT  20.16 25.728 20.184 25.92 ;
    END
  END do0[173]
  PIN do0[174]
    DIRECTION OUTPUT ;
    USE SIGNAL ;
    PORT
      LAYER M3 ;
        RECT  20.232 25.776 20.25 25.92 ;
    END
  END do0[174]
  PIN do0[175]
    DIRECTION OUTPUT ;
    USE SIGNAL ;
    PORT
      LAYER M5 ;
        RECT  20.304 25.728 20.328 25.92 ;
    END
  END do0[175]
  PIN do0[176]
    DIRECTION OUTPUT ;
    USE SIGNAL ;
    PORT
      LAYER M3 ;
        RECT  20.412 25.776 20.43 25.92 ;
    END
    PORT
      LAYER M3 ;
        RECT  20.34 25.788 20.466 25.853 ;
    END
  END do0[176]
  PIN do0[177]
    DIRECTION OUTPUT ;
    USE SIGNAL ;
    PORT
      LAYER M5 ;
        RECT  20.496 25.728 20.52 25.92 ;
    END
  END do0[177]
  PIN do0[178]
    DIRECTION OUTPUT ;
    USE SIGNAL ;
    PORT
      LAYER M3 ;
        RECT  20.592 25.776 20.61 25.92 ;
    END
  END do0[178]
  PIN do0[179]
    DIRECTION OUTPUT ;
    USE SIGNAL ;
    PORT
      LAYER M5 ;
        RECT  20.688 25.728 20.712 25.92 ;
    END
  END do0[179]
  PIN do0[17]
    DIRECTION OUTPUT ;
    USE SIGNAL ;
    PORT
      LAYER M5 ;
        RECT  5.904 25.728 5.928 25.92 ;
    END
  END do0[17]
  PIN do0[180]
    DIRECTION OUTPUT ;
    USE SIGNAL ;
    PORT
      LAYER M3 ;
        RECT  20.772 25.776 20.79 25.92 ;
    END
  END do0[180]
  PIN do0[181]
    DIRECTION OUTPUT ;
    USE SIGNAL ;
    PORT
      LAYER M5 ;
        RECT  20.88 25.728 20.904 25.92 ;
    END
  END do0[181]
  PIN do0[182]
    DIRECTION OUTPUT ;
    USE SIGNAL ;
    PORT
      LAYER M3 ;
        RECT  20.952 25.776 20.97 25.92 ;
    END
  END do0[182]
  PIN do0[183]
    DIRECTION OUTPUT ;
    USE SIGNAL ;
    PORT
      LAYER M5 ;
        RECT  21.072 25.728 21.096 25.92 ;
    END
  END do0[183]
  PIN do0[184]
    DIRECTION OUTPUT ;
    USE SIGNAL ;
    PORT
      LAYER M3 ;
        RECT  21.132 25.776 21.15 25.92 ;
    END
  END do0[184]
  PIN do0[185]
    DIRECTION OUTPUT ;
    USE SIGNAL ;
    PORT
      LAYER M5 ;
        RECT  21.216 25.728 21.24 25.92 ;
    END
  END do0[185]
  PIN do0[186]
    DIRECTION OUTPUT ;
    USE SIGNAL ;
    PORT
      LAYER M3 ;
        RECT  21.348 25.776 21.366 25.92 ;
    END
  END do0[186]
  PIN do0[187]
    DIRECTION OUTPUT ;
    USE SIGNAL ;
    PORT
      LAYER M5 ;
        RECT  21.408 25.728 21.432 25.92 ;
    END
  END do0[187]
  PIN do0[188]
    DIRECTION OUTPUT ;
    USE SIGNAL ;
    PORT
      LAYER M3 ;
        RECT  21.528 25.776 21.546 25.92 ;
    END
  END do0[188]
  PIN do0[189]
    DIRECTION OUTPUT ;
    USE SIGNAL ;
    PORT
      LAYER M5 ;
        RECT  21.6 25.728 21.624 25.92 ;
    END
  END do0[189]
  PIN do0[18]
    DIRECTION OUTPUT ;
    USE SIGNAL ;
    PORT
      LAYER M3 ;
        RECT  6.012 25.776 6.03 25.92 ;
    END
  END do0[18]
  PIN do0[190]
    DIRECTION OUTPUT ;
    USE SIGNAL ;
    PORT
      LAYER M3 ;
        RECT  21.708 25.776 21.726 25.92 ;
    END
  END do0[190]
  PIN do0[191]
    DIRECTION OUTPUT ;
    USE SIGNAL ;
    PORT
      LAYER M5 ;
        RECT  21.792 25.728 21.816 25.92 ;
    END
  END do0[191]
  PIN do0[192]
    DIRECTION OUTPUT ;
    USE SIGNAL ;
    PORT
      LAYER M3 ;
        RECT  21.888 25.776 21.906 25.92 ;
    END
  END do0[192]
  PIN do0[193]
    DIRECTION OUTPUT ;
    USE SIGNAL ;
    PORT
      LAYER M5 ;
        RECT  21.984 25.728 22.008 25.92 ;
    END
  END do0[193]
  PIN do0[194]
    DIRECTION OUTPUT ;
    USE SIGNAL ;
    PORT
      LAYER M3 ;
        RECT  22.068 25.776 22.086 25.92 ;
    END
  END do0[194]
  PIN do0[195]
    DIRECTION OUTPUT ;
    USE SIGNAL ;
    PORT
      LAYER M5 ;
        RECT  22.128 25.728 22.152 25.92 ;
    END
  END do0[195]
  PIN do0[196]
    DIRECTION OUTPUT ;
    USE SIGNAL ;
    PORT
      LAYER M3 ;
        RECT  22.248 25.776 22.266 25.92 ;
    END
  END do0[196]
  PIN do0[197]
    DIRECTION OUTPUT ;
    USE SIGNAL ;
    PORT
      LAYER M5 ;
        RECT  22.32 25.728 22.344 25.92 ;
    END
  END do0[197]
  PIN do0[198]
    DIRECTION OUTPUT ;
    USE SIGNAL ;
    PORT
      LAYER M3 ;
        RECT  22.428 25.776 22.446 25.92 ;
    END
  END do0[198]
  PIN do0[199]
    DIRECTION OUTPUT ;
    USE SIGNAL ;
    PORT
      LAYER M5 ;
        RECT  22.512 25.728 22.536 25.92 ;
    END
  END do0[199]
  PIN do0[19]
    DIRECTION OUTPUT ;
    USE SIGNAL ;
    PORT
      LAYER M5 ;
        RECT  6.096 25.728 6.12 25.92 ;
    END
  END do0[19]
  PIN do0[1]
    DIRECTION OUTPUT ;
    USE SIGNAL ;
    PORT
      LAYER M5 ;
        RECT  4.464 25.728 4.488 25.92 ;
    END
  END do0[1]
  PIN do0[200]
    DIRECTION OUTPUT ;
    USE SIGNAL ;
    PORT
      LAYER M3 ;
        RECT  22.608 25.776 22.626 25.92 ;
    END
  END do0[200]
  PIN do0[201]
    DIRECTION OUTPUT ;
    USE SIGNAL ;
    PORT
      LAYER M5 ;
        RECT  22.704 25.728 22.728 25.92 ;
    END
  END do0[201]
  PIN do0[202]
    DIRECTION OUTPUT ;
    USE SIGNAL ;
    PORT
      LAYER M3 ;
        RECT  22.788 25.776 22.806 25.92 ;
    END
  END do0[202]
  PIN do0[203]
    DIRECTION OUTPUT ;
    USE SIGNAL ;
    PORT
      LAYER M5 ;
        RECT  22.896 25.728 22.92 25.92 ;
    END
  END do0[203]
  PIN do0[204]
    DIRECTION OUTPUT ;
    USE SIGNAL ;
    PORT
      LAYER M3 ;
        RECT  22.968 25.776 22.986 25.92 ;
    END
  END do0[204]
  PIN do0[205]
    DIRECTION OUTPUT ;
    USE SIGNAL ;
    PORT
      LAYER M5 ;
        RECT  23.04 25.728 23.064 25.92 ;
    END
  END do0[205]
  PIN do0[206]
    DIRECTION OUTPUT ;
    USE SIGNAL ;
    PORT
      LAYER M3 ;
        RECT  23.148 25.776 23.166 25.92 ;
    END
  END do0[206]
  PIN do0[207]
    DIRECTION OUTPUT ;
    USE SIGNAL ;
    PORT
      LAYER M5 ;
        RECT  23.232 25.728 23.256 25.92 ;
    END
  END do0[207]
  PIN do0[208]
    DIRECTION OUTPUT ;
    USE SIGNAL ;
    PORT
      LAYER M3 ;
        RECT  23.328 25.776 23.346 25.92 ;
    END
  END do0[208]
  PIN do0[209]
    DIRECTION OUTPUT ;
    USE SIGNAL ;
    PORT
      LAYER M5 ;
        RECT  23.424 25.728 23.448 25.92 ;
    END
  END do0[209]
  PIN do0[20]
    DIRECTION OUTPUT ;
    USE SIGNAL ;
    PORT
      LAYER M3 ;
        RECT  6.192 25.776 6.21 25.92 ;
    END
  END do0[20]
  PIN do0[210]
    DIRECTION OUTPUT ;
    USE SIGNAL ;
    PORT
      LAYER M3 ;
        RECT  23.508 25.776 23.526 25.92 ;
    END
  END do0[210]
  PIN do0[211]
    DIRECTION OUTPUT ;
    USE SIGNAL ;
    PORT
      LAYER M5 ;
        RECT  23.616 25.728 23.64 25.92 ;
    END
  END do0[211]
  PIN do0[212]
    DIRECTION OUTPUT ;
    USE SIGNAL ;
    PORT
      LAYER M3 ;
        RECT  23.688 25.776 23.706 25.92 ;
    END
  END do0[212]
  PIN do0[213]
    DIRECTION OUTPUT ;
    USE SIGNAL ;
    PORT
      LAYER M5 ;
        RECT  23.808 25.728 23.832 25.92 ;
    END
  END do0[213]
  PIN do0[214]
    DIRECTION OUTPUT ;
    USE SIGNAL ;
    PORT
      LAYER M3 ;
        RECT  23.904 25.776 23.922 25.92 ;
    END
  END do0[214]
  PIN do0[215]
    DIRECTION OUTPUT ;
    USE SIGNAL ;
    PORT
      LAYER M5 ;
        RECT  24 25.728 24.024 25.92 ;
    END
  END do0[215]
  PIN do0[216]
    DIRECTION OUTPUT ;
    USE SIGNAL ;
    PORT
      LAYER M3 ;
        RECT  24.084 25.776 24.102 25.92 ;
    END
  END do0[216]
  PIN do0[217]
    DIRECTION OUTPUT ;
    USE SIGNAL ;
    PORT
      LAYER M5 ;
        RECT  24.144 25.728 24.168 25.92 ;
    END
  END do0[217]
  PIN do0[218]
    DIRECTION OUTPUT ;
    USE SIGNAL ;
    PORT
      LAYER M3 ;
        RECT  24.264 25.776 24.282 25.92 ;
    END
  END do0[218]
  PIN do0[219]
    DIRECTION OUTPUT ;
    USE SIGNAL ;
    PORT
      LAYER M5 ;
        RECT  24.336 25.728 24.36 25.92 ;
    END
  END do0[219]
  PIN do0[21]
    DIRECTION OUTPUT ;
    USE SIGNAL ;
    PORT
      LAYER M5 ;
        RECT  6.288 25.728 6.312 25.92 ;
    END
  END do0[21]
  PIN do0[220]
    DIRECTION OUTPUT ;
    USE SIGNAL ;
    PORT
      LAYER M3 ;
        RECT  24.444 25.776 24.462 25.92 ;
    END
  END do0[220]
  PIN do0[221]
    DIRECTION OUTPUT ;
    USE SIGNAL ;
    PORT
      LAYER M5 ;
        RECT  24.528 25.728 24.552 25.92 ;
    END
  END do0[221]
  PIN do0[222]
    DIRECTION OUTPUT ;
    USE SIGNAL ;
    PORT
      LAYER M3 ;
        RECT  24.624 25.776 24.642 25.92 ;
    END
  END do0[222]
  PIN do0[223]
    DIRECTION OUTPUT ;
    USE SIGNAL ;
    PORT
      LAYER M5 ;
        RECT  24.72 25.728 24.744 25.92 ;
    END
  END do0[223]
  PIN do0[224]
    DIRECTION OUTPUT ;
    USE SIGNAL ;
    PORT
      LAYER M3 ;
        RECT  24.804 25.776 24.822 25.92 ;
    END
  END do0[224]
  PIN do0[225]
    DIRECTION OUTPUT ;
    USE SIGNAL ;
    PORT
      LAYER M5 ;
        RECT  24.912 25.728 24.936 25.92 ;
    END
  END do0[225]
  PIN do0[226]
    DIRECTION OUTPUT ;
    USE SIGNAL ;
    PORT
      LAYER M3 ;
        RECT  24.984 25.776 25.002 25.92 ;
    END
  END do0[226]
  PIN do0[227]
    DIRECTION OUTPUT ;
    USE SIGNAL ;
    PORT
      LAYER M5 ;
        RECT  25.056 25.728 25.08 25.92 ;
    END
  END do0[227]
  PIN do0[228]
    DIRECTION OUTPUT ;
    USE SIGNAL ;
    PORT
      LAYER M3 ;
        RECT  25.164 25.776 25.182 25.92 ;
    END
  END do0[228]
  PIN do0[229]
    DIRECTION OUTPUT ;
    USE SIGNAL ;
    PORT
      LAYER M5 ;
        RECT  25.248 25.728 25.272 25.92 ;
    END
  END do0[229]
  PIN do0[22]
    DIRECTION OUTPUT ;
    USE SIGNAL ;
    PORT
      LAYER M3 ;
        RECT  6.372 25.776 6.39 25.92 ;
    END
  END do0[22]
  PIN do0[230]
    DIRECTION OUTPUT ;
    USE SIGNAL ;
    PORT
      LAYER M3 ;
        RECT  25.344 25.776 25.362 25.92 ;
    END
  END do0[230]
  PIN do0[231]
    DIRECTION OUTPUT ;
    USE SIGNAL ;
    PORT
      LAYER M5 ;
        RECT  25.44 25.728 25.464 25.92 ;
    END
  END do0[231]
  PIN do0[232]
    DIRECTION OUTPUT ;
    USE SIGNAL ;
    PORT
      LAYER M3 ;
        RECT  25.524 25.776 25.542 25.92 ;
    END
  END do0[232]
  PIN do0[233]
    DIRECTION OUTPUT ;
    USE SIGNAL ;
    PORT
      LAYER M5 ;
        RECT  25.632 25.728 25.656 25.92 ;
    END
  END do0[233]
  PIN do0[234]
    DIRECTION OUTPUT ;
    USE SIGNAL ;
    PORT
      LAYER M3 ;
        RECT  25.704 25.776 25.722 25.92 ;
    END
  END do0[234]
  PIN do0[235]
    DIRECTION OUTPUT ;
    USE SIGNAL ;
    PORT
      LAYER M5 ;
        RECT  25.824 25.728 25.848 25.92 ;
    END
  END do0[235]
  PIN do0[236]
    DIRECTION OUTPUT ;
    USE SIGNAL ;
    PORT
      LAYER M3 ;
        RECT  25.884 25.776 25.902 25.92 ;
    END
  END do0[236]
  PIN do0[237]
    DIRECTION OUTPUT ;
    USE SIGNAL ;
    PORT
      LAYER M5 ;
        RECT  25.968 25.728 25.992 25.92 ;
    END
  END do0[237]
  PIN do0[238]
    DIRECTION OUTPUT ;
    USE SIGNAL ;
    PORT
      LAYER M3 ;
        RECT  26.064 25.776 26.082 25.92 ;
    END
  END do0[238]
  PIN do0[239]
    DIRECTION OUTPUT ;
    USE SIGNAL ;
    PORT
      LAYER M5 ;
        RECT  26.16 25.728 26.184 25.92 ;
    END
  END do0[239]
  PIN do0[23]
    DIRECTION OUTPUT ;
    USE SIGNAL ;
    PORT
      LAYER M5 ;
        RECT  6.432 25.728 6.456 25.92 ;
    END
  END do0[23]
  PIN do0[240]
    DIRECTION OUTPUT ;
    USE SIGNAL ;
    PORT
      LAYER M3 ;
        RECT  26.244 25.776 26.262 25.92 ;
    END
  END do0[240]
  PIN do0[241]
    DIRECTION OUTPUT ;
    USE SIGNAL ;
    PORT
      LAYER M5 ;
        RECT  26.352 25.728 26.376 25.92 ;
    END
  END do0[241]
  PIN do0[242]
    DIRECTION OUTPUT ;
    USE SIGNAL ;
    PORT
      LAYER M3 ;
        RECT  26.46 25.776 26.478 25.92 ;
    END
  END do0[242]
  PIN do0[243]
    DIRECTION OUTPUT ;
    USE SIGNAL ;
    PORT
      LAYER M5 ;
        RECT  26.544 25.728 26.568 25.92 ;
    END
  END do0[243]
  PIN do0[244]
    DIRECTION OUTPUT ;
    USE SIGNAL ;
    PORT
      LAYER M3 ;
        RECT  26.64 25.776 26.658 25.92 ;
    END
  END do0[244]
  PIN do0[245]
    DIRECTION OUTPUT ;
    USE SIGNAL ;
    PORT
      LAYER M5 ;
        RECT  26.736 25.728 26.76 25.92 ;
    END
  END do0[245]
  PIN do0[246]
    DIRECTION OUTPUT ;
    USE SIGNAL ;
    PORT
      LAYER M3 ;
        RECT  26.82 25.776 26.838 25.92 ;
    END
  END do0[246]
  PIN do0[247]
    DIRECTION OUTPUT ;
    USE SIGNAL ;
    PORT
      LAYER M5 ;
        RECT  26.88 25.728 26.904 25.92 ;
    END
  END do0[247]
  PIN do0[248]
    DIRECTION OUTPUT ;
    USE SIGNAL ;
    PORT
      LAYER M3 ;
        RECT  27 25.776 27.018 25.92 ;
    END
  END do0[248]
  PIN do0[249]
    DIRECTION OUTPUT ;
    USE SIGNAL ;
    PORT
      LAYER M5 ;
        RECT  27.072 25.728 27.096 25.92 ;
    END
  END do0[249]
  PIN do0[24]
    DIRECTION OUTPUT ;
    USE SIGNAL ;
    PORT
      LAYER M3 ;
        RECT  6.552 25.776 6.57 25.92 ;
    END
  END do0[24]
  PIN do0[250]
    DIRECTION OUTPUT ;
    USE SIGNAL ;
    PORT
      LAYER M3 ;
        RECT  27.18 25.776 27.198 25.92 ;
    END
  END do0[250]
  PIN do0[251]
    DIRECTION OUTPUT ;
    USE SIGNAL ;
    PORT
      LAYER M5 ;
        RECT  27.264 25.728 27.288 25.92 ;
    END
  END do0[251]
  PIN do0[252]
    DIRECTION OUTPUT ;
    USE SIGNAL ;
    PORT
      LAYER M3 ;
        RECT  27.36 25.776 27.378 25.92 ;
    END
  END do0[252]
  PIN do0[253]
    DIRECTION OUTPUT ;
    USE SIGNAL ;
    PORT
      LAYER M5 ;
        RECT  27.456 25.728 27.48 25.92 ;
    END
  END do0[253]
  PIN do0[254]
    DIRECTION OUTPUT ;
    USE SIGNAL ;
    PORT
      LAYER M3 ;
        RECT  27.54 25.776 27.558 25.92 ;
    END
  END do0[254]
  PIN do0[255]
    DIRECTION OUTPUT ;
    USE SIGNAL ;
    PORT
      LAYER M5 ;
        RECT  27.648 25.728 27.672 25.92 ;
    END
  END do0[255]
  PIN do0[256]
    DIRECTION OUTPUT ;
    USE SIGNAL ;
    PORT
      LAYER M3 ;
        RECT  27.72 25.776 27.738 25.92 ;
    END
  END do0[256]
  PIN do0[257]
    DIRECTION OUTPUT ;
    USE SIGNAL ;
    PORT
      LAYER M5 ;
        RECT  27.792 25.728 27.816 25.92 ;
    END
  END do0[257]
  PIN do0[258]
    DIRECTION OUTPUT ;
    USE SIGNAL ;
    PORT
      LAYER M3 ;
        RECT  27.9 25.776 27.918 25.92 ;
    END
  END do0[258]
  PIN do0[259]
    DIRECTION OUTPUT ;
    USE SIGNAL ;
    PORT
      LAYER M5 ;
        RECT  27.984 25.728 28.008 25.92 ;
    END
  END do0[259]
  PIN do0[25]
    DIRECTION OUTPUT ;
    USE SIGNAL ;
    PORT
      LAYER M5 ;
        RECT  6.624 25.728 6.648 25.92 ;
    END
  END do0[25]
  PIN do0[260]
    DIRECTION OUTPUT ;
    USE SIGNAL ;
    PORT
      LAYER M3 ;
        RECT  28.08 25.776 28.098 25.92 ;
    END
  END do0[260]
  PIN do0[261]
    DIRECTION OUTPUT ;
    USE SIGNAL ;
    PORT
      LAYER M5 ;
        RECT  28.176 25.728 28.2 25.92 ;
    END
  END do0[261]
  PIN do0[262]
    DIRECTION OUTPUT ;
    USE SIGNAL ;
    PORT
      LAYER M3 ;
        RECT  28.26 25.776 28.278 25.92 ;
    END
  END do0[262]
  PIN do0[263]
    DIRECTION OUTPUT ;
    USE SIGNAL ;
    PORT
      LAYER M5 ;
        RECT  28.368 25.728 28.392 25.92 ;
    END
  END do0[263]
  PIN do0[264]
    DIRECTION OUTPUT ;
    USE SIGNAL ;
    PORT
      LAYER M3 ;
        RECT  28.44 25.776 28.458 25.92 ;
    END
  END do0[264]
  PIN do0[265]
    DIRECTION OUTPUT ;
    USE SIGNAL ;
    PORT
      LAYER M5 ;
        RECT  28.56 25.728 28.584 25.92 ;
    END
  END do0[265]
  PIN do0[266]
    DIRECTION OUTPUT ;
    USE SIGNAL ;
    PORT
      LAYER M3 ;
        RECT  28.62 25.776 28.638 25.92 ;
    END
  END do0[266]
  PIN do0[267]
    DIRECTION OUTPUT ;
    USE SIGNAL ;
    PORT
      LAYER M5 ;
        RECT  28.704 25.728 28.728 25.92 ;
    END
  END do0[267]
  PIN do0[268]
    DIRECTION OUTPUT ;
    USE SIGNAL ;
    PORT
      LAYER M3 ;
        RECT  28.8 25.776 28.818 25.92 ;
    END
  END do0[268]
  PIN do0[269]
    DIRECTION OUTPUT ;
    USE SIGNAL ;
    PORT
      LAYER M5 ;
        RECT  28.896 25.728 28.92 25.92 ;
    END
  END do0[269]
  PIN do0[26]
    DIRECTION OUTPUT ;
    USE SIGNAL ;
    PORT
      LAYER M3 ;
        RECT  6.732 25.776 6.75 25.92 ;
    END
  END do0[26]
  PIN do0[270]
    DIRECTION OUTPUT ;
    USE SIGNAL ;
    PORT
      LAYER M3 ;
        RECT  29.016 25.776 29.034 25.92 ;
    END
  END do0[270]
  PIN do0[271]
    DIRECTION OUTPUT ;
    USE SIGNAL ;
    PORT
      LAYER M5 ;
        RECT  29.088 25.728 29.112 25.92 ;
    END
  END do0[271]
  PIN do0[272]
    DIRECTION OUTPUT ;
    USE SIGNAL ;
    PORT
      LAYER M3 ;
        RECT  29.196 25.776 29.214 25.92 ;
    END
  END do0[272]
  PIN do0[273]
    DIRECTION OUTPUT ;
    USE SIGNAL ;
    PORT
      LAYER M5 ;
        RECT  29.28 25.728 29.304 25.92 ;
    END
  END do0[273]
  PIN do0[274]
    DIRECTION OUTPUT ;
    USE SIGNAL ;
    PORT
      LAYER M3 ;
        RECT  29.376 25.776 29.394 25.92 ;
    END
  END do0[274]
  PIN do0[275]
    DIRECTION OUTPUT ;
    USE SIGNAL ;
    PORT
      LAYER M5 ;
        RECT  29.472 25.728 29.496 25.92 ;
    END
  END do0[275]
  PIN do0[276]
    DIRECTION OUTPUT ;
    USE SIGNAL ;
    PORT
      LAYER M3 ;
        RECT  29.556 25.776 29.574 25.92 ;
    END
  END do0[276]
  PIN do0[277]
    DIRECTION OUTPUT ;
    USE SIGNAL ;
    PORT
      LAYER M5 ;
        RECT  29.616 25.728 29.64 25.92 ;
    END
  END do0[277]
  PIN do0[278]
    DIRECTION OUTPUT ;
    USE SIGNAL ;
    PORT
      LAYER M3 ;
        RECT  29.736 25.776 29.754 25.92 ;
    END
  END do0[278]
  PIN do0[279]
    DIRECTION OUTPUT ;
    USE SIGNAL ;
    PORT
      LAYER M5 ;
        RECT  29.808 25.728 29.832 25.92 ;
    END
  END do0[279]
  PIN do0[27]
    DIRECTION OUTPUT ;
    USE SIGNAL ;
    PORT
      LAYER M5 ;
        RECT  6.816 25.728 6.84 25.92 ;
    END
  END do0[27]
  PIN do0[280]
    DIRECTION OUTPUT ;
    USE SIGNAL ;
    PORT
      LAYER M3 ;
        RECT  29.916 25.776 29.934 25.92 ;
    END
  END do0[280]
  PIN do0[281]
    DIRECTION OUTPUT ;
    USE SIGNAL ;
    PORT
      LAYER M5 ;
        RECT  30 25.728 30.024 25.92 ;
    END
  END do0[281]
  PIN do0[282]
    DIRECTION OUTPUT ;
    USE SIGNAL ;
    PORT
      LAYER M3 ;
        RECT  30.096 25.776 30.114 25.92 ;
    END
  END do0[282]
  PIN do0[283]
    DIRECTION OUTPUT ;
    USE SIGNAL ;
    PORT
      LAYER M5 ;
        RECT  30.384 25.728 30.408 25.92 ;
    END
  END do0[283]
  PIN do0[284]
    DIRECTION OUTPUT ;
    USE SIGNAL ;
    PORT
      LAYER M3 ;
        RECT  30.456 25.776 30.474 25.92 ;
    END
  END do0[284]
  PIN do0[285]
    DIRECTION OUTPUT ;
    USE SIGNAL ;
    PORT
      LAYER M5 ;
        RECT  30.528 25.728 30.552 25.92 ;
    END
  END do0[285]
  PIN do0[286]
    DIRECTION OUTPUT ;
    USE SIGNAL ;
    PORT
      LAYER M3 ;
        RECT  30.636 25.776 30.654 25.92 ;
    END
  END do0[286]
  PIN do0[287]
    DIRECTION OUTPUT ;
    USE SIGNAL ;
    PORT
      LAYER M5 ;
        RECT  30.72 25.728 30.744 25.92 ;
    END
  END do0[287]
  PIN do0[288]
    DIRECTION OUTPUT ;
    USE SIGNAL ;
    PORT
      LAYER M3 ;
        RECT  30.816 25.776 30.834 25.92 ;
    END
  END do0[288]
  PIN do0[289]
    DIRECTION OUTPUT ;
    USE SIGNAL ;
    PORT
      LAYER M5 ;
        RECT  30.912 25.728 30.936 25.92 ;
    END
  END do0[289]
  PIN do0[28]
    DIRECTION OUTPUT ;
    USE SIGNAL ;
    PORT
      LAYER M3 ;
        RECT  6.912 25.776 6.93 25.92 ;
    END
  END do0[28]
  PIN do0[290]
    DIRECTION OUTPUT ;
    USE SIGNAL ;
    PORT
      LAYER M3 ;
        RECT  30.996 25.776 31.014 25.92 ;
    END
  END do0[290]
  PIN do0[291]
    DIRECTION OUTPUT ;
    USE SIGNAL ;
    PORT
      LAYER M5 ;
        RECT  31.104 25.728 31.128 25.92 ;
    END
  END do0[291]
  PIN do0[292]
    DIRECTION OUTPUT ;
    USE SIGNAL ;
    PORT
      LAYER M3 ;
        RECT  31.176 25.776 31.194 25.92 ;
    END
  END do0[292]
  PIN do0[293]
    DIRECTION OUTPUT ;
    USE SIGNAL ;
    PORT
      LAYER M5 ;
        RECT  31.296 25.728 31.32 25.92 ;
    END
  END do0[293]
  PIN do0[294]
    DIRECTION OUTPUT ;
    USE SIGNAL ;
    PORT
      LAYER M3 ;
        RECT  31.356 25.776 31.374 25.92 ;
    END
  END do0[294]
  PIN do0[295]
    DIRECTION OUTPUT ;
    USE SIGNAL ;
    PORT
      LAYER M5 ;
        RECT  31.44 25.728 31.464 25.92 ;
    END
  END do0[295]
  PIN do0[296]
    DIRECTION OUTPUT ;
    USE SIGNAL ;
    PORT
      LAYER M3 ;
        RECT  31.572 25.776 31.59 25.92 ;
    END
  END do0[296]
  PIN do0[297]
    DIRECTION OUTPUT ;
    USE SIGNAL ;
    PORT
      LAYER M5 ;
        RECT  31.632 25.728 31.656 25.92 ;
    END
  END do0[297]
  PIN do0[298]
    DIRECTION OUTPUT ;
    USE SIGNAL ;
    PORT
      LAYER M3 ;
        RECT  31.752 25.776 31.77 25.92 ;
    END
  END do0[298]
  PIN do0[299]
    DIRECTION OUTPUT ;
    USE SIGNAL ;
    PORT
      LAYER M5 ;
        RECT  31.824 25.728 31.848 25.92 ;
    END
  END do0[299]
  PIN do0[29]
    DIRECTION OUTPUT ;
    USE SIGNAL ;
    PORT
      LAYER M5 ;
        RECT  7.008 25.728 7.032 25.92 ;
    END
  END do0[29]
  PIN do0[2]
    DIRECTION OUTPUT ;
    USE SIGNAL ;
    PORT
      LAYER M3 ;
        RECT  4.536 25.776 4.554 25.92 ;
    END
  END do0[2]
  PIN do0[300]
    DIRECTION OUTPUT ;
    USE SIGNAL ;
    PORT
      LAYER M3 ;
        RECT  31.932 25.776 31.95 25.92 ;
    END
  END do0[300]
  PIN do0[301]
    DIRECTION OUTPUT ;
    USE SIGNAL ;
    PORT
      LAYER M5 ;
        RECT  32.016 25.728 32.04 25.92 ;
    END
  END do0[301]
  PIN do0[302]
    DIRECTION OUTPUT ;
    USE SIGNAL ;
    PORT
      LAYER M3 ;
        RECT  32.112 25.776 32.13 25.92 ;
    END
  END do0[302]
  PIN do0[303]
    DIRECTION OUTPUT ;
    USE SIGNAL ;
    PORT
      LAYER M5 ;
        RECT  32.208 25.728 32.232 25.92 ;
    END
  END do0[303]
  PIN do0[304]
    DIRECTION OUTPUT ;
    USE SIGNAL ;
    PORT
      LAYER M3 ;
        RECT  32.292 25.776 32.31 25.92 ;
    END
  END do0[304]
  PIN do0[305]
    DIRECTION OUTPUT ;
    USE SIGNAL ;
    PORT
      LAYER M5 ;
        RECT  32.352 25.728 32.376 25.92 ;
    END
  END do0[305]
  PIN do0[306]
    DIRECTION OUTPUT ;
    USE SIGNAL ;
    PORT
      LAYER M3 ;
        RECT  32.472 25.776 32.49 25.92 ;
    END
  END do0[306]
  PIN do0[307]
    DIRECTION OUTPUT ;
    USE SIGNAL ;
    PORT
      LAYER M5 ;
        RECT  32.544 25.728 32.568 25.92 ;
    END
  END do0[307]
  PIN do0[308]
    DIRECTION OUTPUT ;
    USE SIGNAL ;
    PORT
      LAYER M3 ;
        RECT  32.652 25.776 32.67 25.92 ;
    END
  END do0[308]
  PIN do0[309]
    DIRECTION OUTPUT ;
    USE SIGNAL ;
    PORT
      LAYER M5 ;
        RECT  32.736 25.728 32.76 25.92 ;
    END
  END do0[309]
  PIN do0[30]
    DIRECTION OUTPUT ;
    USE SIGNAL ;
    PORT
      LAYER M3 ;
        RECT  7.092 25.776 7.11 25.92 ;
    END
  END do0[30]
  PIN do0[310]
    DIRECTION OUTPUT ;
    USE SIGNAL ;
    PORT
      LAYER M3 ;
        RECT  32.832 25.776 32.85 25.92 ;
    END
  END do0[310]
  PIN do0[311]
    DIRECTION OUTPUT ;
    USE SIGNAL ;
    PORT
      LAYER M5 ;
        RECT  32.928 25.728 32.952 25.92 ;
    END
  END do0[311]
  PIN do0[312]
    DIRECTION OUTPUT ;
    USE SIGNAL ;
    PORT
      LAYER M3 ;
        RECT  33.012 25.776 33.03 25.92 ;
    END
  END do0[312]
  PIN do0[313]
    DIRECTION OUTPUT ;
    USE SIGNAL ;
    PORT
      LAYER M5 ;
        RECT  33.12 25.728 33.144 25.92 ;
    END
  END do0[313]
  PIN do0[314]
    DIRECTION OUTPUT ;
    USE SIGNAL ;
    PORT
      LAYER M3 ;
        RECT  33.192 25.776 33.21 25.92 ;
    END
  END do0[314]
  PIN do0[315]
    DIRECTION OUTPUT ;
    USE SIGNAL ;
    PORT
      LAYER M5 ;
        RECT  33.264 25.728 33.288 25.92 ;
    END
  END do0[315]
  PIN do0[316]
    DIRECTION OUTPUT ;
    USE SIGNAL ;
    PORT
      LAYER M3 ;
        RECT  33.372 25.776 33.39 25.92 ;
    END
  END do0[316]
  PIN do0[317]
    DIRECTION OUTPUT ;
    USE SIGNAL ;
    PORT
      LAYER M5 ;
        RECT  33.456 25.728 33.48 25.92 ;
    END
  END do0[317]
  PIN do0[318]
    DIRECTION OUTPUT ;
    USE SIGNAL ;
    PORT
      LAYER M3 ;
        RECT  33.552 25.776 33.57 25.92 ;
    END
  END do0[318]
  PIN do0[319]
    DIRECTION OUTPUT ;
    USE SIGNAL ;
    PORT
      LAYER M5 ;
        RECT  33.648 25.728 33.672 25.92 ;
    END
  END do0[319]
  PIN do0[31]
    DIRECTION OUTPUT ;
    USE SIGNAL ;
    PORT
      LAYER M5 ;
        RECT  7.2 25.728 7.224 25.92 ;
    END
  END do0[31]
  PIN do0[320]
    DIRECTION OUTPUT ;
    USE SIGNAL ;
    PORT
      LAYER M3 ;
        RECT  33.732 25.776 33.75 25.92 ;
    END
  END do0[320]
  PIN do0[321]
    DIRECTION OUTPUT ;
    USE SIGNAL ;
    PORT
      LAYER M5 ;
        RECT  33.84 25.728 33.864 25.92 ;
    END
  END do0[321]
  PIN do0[322]
    DIRECTION OUTPUT ;
    USE SIGNAL ;
    PORT
      LAYER M3 ;
        RECT  33.912 25.776 33.93 25.92 ;
    END
  END do0[322]
  PIN do0[323]
    DIRECTION OUTPUT ;
    USE SIGNAL ;
    PORT
      LAYER M5 ;
        RECT  34.032 25.728 34.056 25.92 ;
    END
  END do0[323]
  PIN do0[324]
    DIRECTION OUTPUT ;
    USE SIGNAL ;
    PORT
      LAYER M3 ;
        RECT  34.092 25.776 34.11 25.92 ;
    END
  END do0[324]
  PIN do0[325]
    DIRECTION OUTPUT ;
    USE SIGNAL ;
    PORT
      LAYER M5 ;
        RECT  34.176 25.728 34.2 25.92 ;
    END
  END do0[325]
  PIN do0[326]
    DIRECTION OUTPUT ;
    USE SIGNAL ;
    PORT
      LAYER M3 ;
        RECT  34.308 25.776 34.326 25.92 ;
    END
  END do0[326]
  PIN do0[327]
    DIRECTION OUTPUT ;
    USE SIGNAL ;
    PORT
      LAYER M5 ;
        RECT  34.368 25.728 34.392 25.92 ;
    END
  END do0[327]
  PIN do0[328]
    DIRECTION OUTPUT ;
    USE SIGNAL ;
    PORT
      LAYER M3 ;
        RECT  34.488 25.776 34.506 25.92 ;
    END
  END do0[328]
  PIN do0[329]
    DIRECTION OUTPUT ;
    USE SIGNAL ;
    PORT
      LAYER M5 ;
        RECT  34.56 25.728 34.584 25.92 ;
    END
  END do0[329]
  PIN do0[32]
    DIRECTION OUTPUT ;
    USE SIGNAL ;
    PORT
      LAYER M3 ;
        RECT  7.272 25.776 7.29 25.92 ;
    END
  END do0[32]
  PIN do0[330]
    DIRECTION OUTPUT ;
    USE SIGNAL ;
    PORT
      LAYER M3 ;
        RECT  34.668 25.776 34.686 25.92 ;
    END
  END do0[330]
  PIN do0[331]
    DIRECTION OUTPUT ;
    USE SIGNAL ;
    PORT
      LAYER M5 ;
        RECT  34.752 25.728 34.776 25.92 ;
    END
  END do0[331]
  PIN do0[332]
    DIRECTION OUTPUT ;
    USE SIGNAL ;
    PORT
      LAYER M3 ;
        RECT  34.848 25.776 34.866 25.92 ;
    END
  END do0[332]
  PIN do0[333]
    DIRECTION OUTPUT ;
    USE SIGNAL ;
    PORT
      LAYER M5 ;
        RECT  34.944 25.728 34.968 25.92 ;
    END
  END do0[333]
  PIN do0[334]
    DIRECTION OUTPUT ;
    USE SIGNAL ;
    PORT
      LAYER M3 ;
        RECT  35.028 25.776 35.046 25.92 ;
    END
  END do0[334]
  PIN do0[335]
    DIRECTION OUTPUT ;
    USE SIGNAL ;
    PORT
      LAYER M5 ;
        RECT  35.088 25.728 35.112 25.92 ;
    END
  END do0[335]
  PIN do0[336]
    DIRECTION OUTPUT ;
    USE SIGNAL ;
    PORT
      LAYER M3 ;
        RECT  35.208 25.776 35.226 25.92 ;
    END
  END do0[336]
  PIN do0[337]
    DIRECTION OUTPUT ;
    USE SIGNAL ;
    PORT
      LAYER M5 ;
        RECT  35.28 25.728 35.304 25.92 ;
    END
  END do0[337]
  PIN do0[338]
    DIRECTION OUTPUT ;
    USE SIGNAL ;
    PORT
      LAYER M3 ;
        RECT  35.388 25.776 35.406 25.92 ;
    END
  END do0[338]
  PIN do0[339]
    DIRECTION OUTPUT ;
    USE SIGNAL ;
    PORT
      LAYER M5 ;
        RECT  35.472 25.728 35.496 25.92 ;
    END
  END do0[339]
  PIN do0[33]
    DIRECTION OUTPUT ;
    USE SIGNAL ;
    PORT
      LAYER M5 ;
        RECT  7.344 25.728 7.368 25.92 ;
    END
  END do0[33]
  PIN do0[340]
    DIRECTION OUTPUT ;
    USE SIGNAL ;
    PORT
      LAYER M3 ;
        RECT  35.568 25.776 35.586 25.92 ;
    END
  END do0[340]
  PIN do0[341]
    DIRECTION OUTPUT ;
    USE SIGNAL ;
    PORT
      LAYER M5 ;
        RECT  35.664 25.728 35.688 25.92 ;
    END
  END do0[341]
  PIN do0[342]
    DIRECTION OUTPUT ;
    USE SIGNAL ;
    PORT
      LAYER M3 ;
        RECT  35.748 25.776 35.766 25.92 ;
    END
  END do0[342]
  PIN do0[343]
    DIRECTION OUTPUT ;
    USE SIGNAL ;
    PORT
      LAYER M5 ;
        RECT  35.856 25.728 35.88 25.92 ;
    END
  END do0[343]
  PIN do0[344]
    DIRECTION OUTPUT ;
    USE SIGNAL ;
    PORT
      LAYER M3 ;
        RECT  35.928 25.776 35.946 25.92 ;
    END
  END do0[344]
  PIN do0[345]
    DIRECTION OUTPUT ;
    USE SIGNAL ;
    PORT
      LAYER M5 ;
        RECT  36 25.728 36.024 25.92 ;
    END
  END do0[345]
  PIN do0[346]
    DIRECTION OUTPUT ;
    USE SIGNAL ;
    PORT
      LAYER M3 ;
        RECT  36.108 25.776 36.126 25.92 ;
    END
  END do0[346]
  PIN do0[347]
    DIRECTION OUTPUT ;
    USE SIGNAL ;
    PORT
      LAYER M5 ;
        RECT  36.192 25.728 36.216 25.92 ;
    END
  END do0[347]
  PIN do0[348]
    DIRECTION OUTPUT ;
    USE SIGNAL ;
    PORT
      LAYER M3 ;
        RECT  36.288 25.776 36.306 25.92 ;
    END
  END do0[348]
  PIN do0[349]
    DIRECTION OUTPUT ;
    USE SIGNAL ;
    PORT
      LAYER M5 ;
        RECT  36.384 25.728 36.408 25.92 ;
    END
  END do0[349]
  PIN do0[34]
    DIRECTION OUTPUT ;
    USE SIGNAL ;
    PORT
      LAYER M3 ;
        RECT  7.452 25.776 7.47 25.92 ;
    END
  END do0[34]
  PIN do0[350]
    DIRECTION OUTPUT ;
    USE SIGNAL ;
    PORT
      LAYER M3 ;
        RECT  36.468 25.776 36.486 25.92 ;
    END
  END do0[350]
  PIN do0[351]
    DIRECTION OUTPUT ;
    USE SIGNAL ;
    PORT
      LAYER M5 ;
        RECT  36.576 25.728 36.6 25.92 ;
    END
  END do0[351]
  PIN do0[352]
    DIRECTION OUTPUT ;
    USE SIGNAL ;
    PORT
      LAYER M3 ;
        RECT  36.648 25.776 36.666 25.92 ;
    END
  END do0[352]
  PIN do0[353]
    DIRECTION OUTPUT ;
    USE SIGNAL ;
    PORT
      LAYER M5 ;
        RECT  36.768 25.728 36.792 25.92 ;
    END
  END do0[353]
  PIN do0[354]
    DIRECTION OUTPUT ;
    USE SIGNAL ;
    PORT
      LAYER M3 ;
        RECT  36.864 25.776 36.882 25.92 ;
    END
  END do0[354]
  PIN do0[355]
    DIRECTION OUTPUT ;
    USE SIGNAL ;
    PORT
      LAYER M5 ;
        RECT  36.96 25.728 36.984 25.92 ;
    END
  END do0[355]
  PIN do0[356]
    DIRECTION OUTPUT ;
    USE SIGNAL ;
    PORT
      LAYER M3 ;
        RECT  37.044 25.776 37.062 25.92 ;
    END
  END do0[356]
  PIN do0[357]
    DIRECTION OUTPUT ;
    USE SIGNAL ;
    PORT
      LAYER M5 ;
        RECT  37.104 25.728 37.128 25.92 ;
    END
  END do0[357]
  PIN do0[358]
    DIRECTION OUTPUT ;
    USE SIGNAL ;
    PORT
      LAYER M3 ;
        RECT  37.224 25.776 37.242 25.92 ;
    END
  END do0[358]
  PIN do0[359]
    DIRECTION OUTPUT ;
    USE SIGNAL ;
    PORT
      LAYER M5 ;
        RECT  37.296 25.728 37.32 25.92 ;
    END
  END do0[359]
  PIN do0[35]
    DIRECTION OUTPUT ;
    USE SIGNAL ;
    PORT
      LAYER M5 ;
        RECT  7.536 25.728 7.56 25.92 ;
    END
  END do0[35]
  PIN do0[360]
    DIRECTION OUTPUT ;
    USE SIGNAL ;
    PORT
      LAYER M3 ;
        RECT  37.404 25.776 37.422 25.92 ;
    END
  END do0[360]
  PIN do0[361]
    DIRECTION OUTPUT ;
    USE SIGNAL ;
    PORT
      LAYER M5 ;
        RECT  37.488 25.728 37.512 25.92 ;
    END
  END do0[361]
  PIN do0[362]
    DIRECTION OUTPUT ;
    USE SIGNAL ;
    PORT
      LAYER M3 ;
        RECT  37.584 25.776 37.602 25.92 ;
    END
  END do0[362]
  PIN do0[363]
    DIRECTION OUTPUT ;
    USE SIGNAL ;
    PORT
      LAYER M5 ;
        RECT  37.68 25.728 37.704 25.92 ;
    END
  END do0[363]
  PIN do0[364]
    DIRECTION OUTPUT ;
    USE SIGNAL ;
    PORT
      LAYER M3 ;
        RECT  37.764 25.776 37.782 25.92 ;
    END
  END do0[364]
  PIN do0[365]
    DIRECTION OUTPUT ;
    USE SIGNAL ;
    PORT
      LAYER M5 ;
        RECT  37.872 25.728 37.896 25.92 ;
    END
  END do0[365]
  PIN do0[366]
    DIRECTION OUTPUT ;
    USE SIGNAL ;
    PORT
      LAYER M3 ;
        RECT  37.944 25.776 37.962 25.92 ;
    END
  END do0[366]
  PIN do0[367]
    DIRECTION OUTPUT ;
    USE SIGNAL ;
    PORT
      LAYER M5 ;
        RECT  38.016 25.728 38.04 25.92 ;
    END
  END do0[367]
  PIN do0[368]
    DIRECTION OUTPUT ;
    USE SIGNAL ;
    PORT
      LAYER M3 ;
        RECT  38.124 25.776 38.142 25.92 ;
    END
  END do0[368]
  PIN do0[369]
    DIRECTION OUTPUT ;
    USE SIGNAL ;
    PORT
      LAYER M5 ;
        RECT  38.208 25.728 38.232 25.92 ;
    END
  END do0[369]
  PIN do0[36]
    DIRECTION OUTPUT ;
    USE SIGNAL ;
    PORT
      LAYER M3 ;
        RECT  7.632 25.776 7.65 25.92 ;
    END
  END do0[36]
  PIN do0[370]
    DIRECTION OUTPUT ;
    USE SIGNAL ;
    PORT
      LAYER M3 ;
        RECT  38.304 25.776 38.322 25.92 ;
    END
  END do0[370]
  PIN do0[371]
    DIRECTION OUTPUT ;
    USE SIGNAL ;
    PORT
      LAYER M5 ;
        RECT  38.4 25.728 38.424 25.92 ;
    END
  END do0[371]
  PIN do0[372]
    DIRECTION OUTPUT ;
    USE SIGNAL ;
    PORT
      LAYER M3 ;
        RECT  38.484 25.776 38.502 25.92 ;
    END
  END do0[372]
  PIN do0[373]
    DIRECTION OUTPUT ;
    USE SIGNAL ;
    PORT
      LAYER M5 ;
        RECT  38.592 25.728 38.616 25.92 ;
    END
  END do0[373]
  PIN do0[374]
    DIRECTION OUTPUT ;
    USE SIGNAL ;
    PORT
      LAYER M3 ;
        RECT  38.664 25.776 38.682 25.92 ;
    END
  END do0[374]
  PIN do0[375]
    DIRECTION OUTPUT ;
    USE SIGNAL ;
    PORT
      LAYER M5 ;
        RECT  38.784 25.728 38.808 25.92 ;
    END
  END do0[375]
  PIN do0[376]
    DIRECTION OUTPUT ;
    USE SIGNAL ;
    PORT
      LAYER M3 ;
        RECT  38.844 25.776 38.862 25.92 ;
    END
  END do0[376]
  PIN do0[377]
    DIRECTION OUTPUT ;
    USE SIGNAL ;
    PORT
      LAYER M5 ;
        RECT  38.928 25.728 38.952 25.92 ;
    END
  END do0[377]
  PIN do0[378]
    DIRECTION OUTPUT ;
    USE SIGNAL ;
    PORT
      LAYER M3 ;
        RECT  39.024 25.776 39.042 25.92 ;
    END
  END do0[378]
  PIN do0[379]
    DIRECTION OUTPUT ;
    USE SIGNAL ;
    PORT
      LAYER M5 ;
        RECT  39.12 25.728 39.144 25.92 ;
    END
  END do0[379]
  PIN do0[37]
    DIRECTION OUTPUT ;
    USE SIGNAL ;
    PORT
      LAYER M5 ;
        RECT  7.728 25.728 7.752 25.92 ;
    END
  END do0[37]
  PIN do0[380]
    DIRECTION OUTPUT ;
    USE SIGNAL ;
    PORT
      LAYER M3 ;
        RECT  39.204 25.776 39.222 25.92 ;
    END
  END do0[380]
  PIN do0[381]
    DIRECTION OUTPUT ;
    USE SIGNAL ;
    PORT
      LAYER M5 ;
        RECT  39.312 25.728 39.336 25.92 ;
    END
  END do0[381]
  PIN do0[382]
    DIRECTION OUTPUT ;
    USE SIGNAL ;
    PORT
      LAYER M3 ;
        RECT  39.42 25.776 39.438 25.92 ;
    END
  END do0[382]
  PIN do0[383]
    DIRECTION OUTPUT ;
    USE SIGNAL ;
    PORT
      LAYER M5 ;
        RECT  39.504 25.728 39.528 25.92 ;
    END
  END do0[383]
  PIN do0[384]
    DIRECTION OUTPUT ;
    USE SIGNAL ;
    PORT
      LAYER M3 ;
        RECT  39.6 25.776 39.618 25.92 ;
    END
  END do0[384]
  PIN do0[385]
    DIRECTION OUTPUT ;
    USE SIGNAL ;
    PORT
      LAYER M5 ;
        RECT  39.696 25.728 39.72 25.92 ;
    END
  END do0[385]
  PIN do0[386]
    DIRECTION OUTPUT ;
    USE SIGNAL ;
    PORT
      LAYER M3 ;
        RECT  39.78 25.776 39.798 25.92 ;
    END
  END do0[386]
  PIN do0[387]
    DIRECTION OUTPUT ;
    USE SIGNAL ;
    PORT
      LAYER M5 ;
        RECT  39.84 25.728 39.864 25.92 ;
    END
  END do0[387]
  PIN do0[388]
    DIRECTION OUTPUT ;
    USE SIGNAL ;
    PORT
      LAYER M3 ;
        RECT  39.96 25.776 39.978 25.92 ;
    END
  END do0[388]
  PIN do0[389]
    DIRECTION OUTPUT ;
    USE SIGNAL ;
    PORT
      LAYER M5 ;
        RECT  40.032 25.728 40.056 25.92 ;
    END
  END do0[389]
  PIN do0[38]
    DIRECTION OUTPUT ;
    USE SIGNAL ;
    PORT
      LAYER M3 ;
        RECT  7.812 25.776 7.83 25.92 ;
    END
  END do0[38]
  PIN do0[390]
    DIRECTION OUTPUT ;
    USE SIGNAL ;
    PORT
      LAYER M3 ;
        RECT  40.14 25.776 40.158 25.92 ;
    END
  END do0[390]
  PIN do0[391]
    DIRECTION OUTPUT ;
    USE SIGNAL ;
    PORT
      LAYER M5 ;
        RECT  40.224 25.728 40.248 25.92 ;
    END
  END do0[391]
  PIN do0[392]
    DIRECTION OUTPUT ;
    USE SIGNAL ;
    PORT
      LAYER M3 ;
        RECT  40.32 25.776 40.338 25.92 ;
    END
  END do0[392]
  PIN do0[393]
    DIRECTION OUTPUT ;
    USE SIGNAL ;
    PORT
      LAYER M5 ;
        RECT  40.416 25.728 40.44 25.92 ;
    END
  END do0[393]
  PIN do0[394]
    DIRECTION OUTPUT ;
    USE SIGNAL ;
    PORT
      LAYER M3 ;
        RECT  40.5 25.776 40.518 25.92 ;
    END
  END do0[394]
  PIN do0[395]
    DIRECTION OUTPUT ;
    USE SIGNAL ;
    PORT
      LAYER M5 ;
        RECT  40.608 25.728 40.632 25.92 ;
    END
  END do0[395]
  PIN do0[396]
    DIRECTION OUTPUT ;
    USE SIGNAL ;
    PORT
      LAYER M3 ;
        RECT  40.68 25.776 40.698 25.92 ;
    END
    PORT
      LAYER M3 ;
        RECT  40.644 25.788 40.77 25.853 ;
    END
  END do0[396]
  PIN do0[397]
    DIRECTION OUTPUT ;
    USE SIGNAL ;
    PORT
      LAYER M5 ;
        RECT  40.752 25.728 40.776 25.92 ;
    END
  END do0[397]
  PIN do0[398]
    DIRECTION OUTPUT ;
    USE SIGNAL ;
    PORT
      LAYER M3 ;
        RECT  40.86 25.776 40.878 25.92 ;
    END
  END do0[398]
  PIN do0[399]
    DIRECTION OUTPUT ;
    USE SIGNAL ;
    PORT
      LAYER M5 ;
        RECT  40.944 25.728 40.968 25.92 ;
    END
  END do0[399]
  PIN do0[39]
    DIRECTION OUTPUT ;
    USE SIGNAL ;
    PORT
      LAYER M5 ;
        RECT  7.92 25.728 7.944 25.92 ;
    END
  END do0[39]
  PIN do0[3]
    DIRECTION OUTPUT ;
    USE SIGNAL ;
    PORT
      LAYER M5 ;
        RECT  4.608 25.728 4.632 25.92 ;
    END
  END do0[3]
  PIN do0[400]
    DIRECTION OUTPUT ;
    USE SIGNAL ;
    PORT
      LAYER M3 ;
        RECT  41.04 25.776 41.058 25.92 ;
    END
  END do0[400]
  PIN do0[401]
    DIRECTION OUTPUT ;
    USE SIGNAL ;
    PORT
      LAYER M5 ;
        RECT  41.136 25.728 41.16 25.92 ;
    END
  END do0[401]
  PIN do0[402]
    DIRECTION OUTPUT ;
    USE SIGNAL ;
    PORT
      LAYER M3 ;
        RECT  41.22 25.776 41.238 25.92 ;
    END
  END do0[402]
  PIN do0[403]
    DIRECTION OUTPUT ;
    USE SIGNAL ;
    PORT
      LAYER M5 ;
        RECT  41.328 25.728 41.352 25.92 ;
    END
  END do0[403]
  PIN do0[404]
    DIRECTION OUTPUT ;
    USE SIGNAL ;
    PORT
      LAYER M3 ;
        RECT  41.4 25.776 41.418 25.92 ;
    END
  END do0[404]
  PIN do0[405]
    DIRECTION OUTPUT ;
    USE SIGNAL ;
    PORT
      LAYER M5 ;
        RECT  41.52 25.728 41.544 25.92 ;
    END
  END do0[405]
  PIN do0[406]
    DIRECTION OUTPUT ;
    USE SIGNAL ;
    PORT
      LAYER M3 ;
        RECT  41.58 25.776 41.598 25.92 ;
    END
  END do0[406]
  PIN do0[407]
    DIRECTION OUTPUT ;
    USE SIGNAL ;
    PORT
      LAYER M5 ;
        RECT  41.664 25.728 41.688 25.92 ;
    END
  END do0[407]
  PIN do0[408]
    DIRECTION OUTPUT ;
    USE SIGNAL ;
    PORT
      LAYER M3 ;
        RECT  41.76 25.776 41.778 25.92 ;
    END
  END do0[408]
  PIN do0[409]
    DIRECTION OUTPUT ;
    USE SIGNAL ;
    PORT
      LAYER M5 ;
        RECT  41.856 25.728 41.88 25.92 ;
    END
  END do0[409]
  PIN do0[40]
    DIRECTION OUTPUT ;
    USE SIGNAL ;
    PORT
      LAYER M3 ;
        RECT  7.992 25.776 8.01 25.92 ;
    END
  END do0[40]
  PIN do0[410]
    DIRECTION OUTPUT ;
    USE SIGNAL ;
    PORT
      LAYER M3 ;
        RECT  41.976 25.776 41.994 25.92 ;
    END
  END do0[410]
  PIN do0[411]
    DIRECTION OUTPUT ;
    USE SIGNAL ;
    PORT
      LAYER M5 ;
        RECT  42.048 25.728 42.072 25.92 ;
    END
  END do0[411]
  PIN do0[412]
    DIRECTION OUTPUT ;
    USE SIGNAL ;
    PORT
      LAYER M3 ;
        RECT  42.156 25.776 42.174 25.92 ;
    END
  END do0[412]
  PIN do0[413]
    DIRECTION OUTPUT ;
    USE SIGNAL ;
    PORT
      LAYER M5 ;
        RECT  42.24 25.728 42.264 25.92 ;
    END
  END do0[413]
  PIN do0[414]
    DIRECTION OUTPUT ;
    USE SIGNAL ;
    PORT
      LAYER M3 ;
        RECT  42.336 25.776 42.354 25.92 ;
    END
  END do0[414]
  PIN do0[415]
    DIRECTION OUTPUT ;
    USE SIGNAL ;
    PORT
      LAYER M5 ;
        RECT  42.432 25.728 42.456 25.92 ;
    END
  END do0[415]
  PIN do0[416]
    DIRECTION OUTPUT ;
    USE SIGNAL ;
    PORT
      LAYER M3 ;
        RECT  42.516 25.776 42.534 25.92 ;
    END
  END do0[416]
  PIN do0[417]
    DIRECTION OUTPUT ;
    USE SIGNAL ;
    PORT
      LAYER M5 ;
        RECT  42.576 25.728 42.6 25.92 ;
    END
  END do0[417]
  PIN do0[418]
    DIRECTION OUTPUT ;
    USE SIGNAL ;
    PORT
      LAYER M3 ;
        RECT  42.696 25.776 42.714 25.92 ;
    END
  END do0[418]
  PIN do0[419]
    DIRECTION OUTPUT ;
    USE SIGNAL ;
    PORT
      LAYER M5 ;
        RECT  42.768 25.728 42.792 25.92 ;
    END
  END do0[419]
  PIN do0[41]
    DIRECTION OUTPUT ;
    USE SIGNAL ;
    PORT
      LAYER M5 ;
        RECT  8.112 25.728 8.136 25.92 ;
    END
  END do0[41]
  PIN do0[420]
    DIRECTION OUTPUT ;
    USE SIGNAL ;
    PORT
      LAYER M3 ;
        RECT  42.876 25.776 42.894 25.92 ;
    END
  END do0[420]
  PIN do0[421]
    DIRECTION OUTPUT ;
    USE SIGNAL ;
    PORT
      LAYER M5 ;
        RECT  42.96 25.728 42.984 25.92 ;
    END
  END do0[421]
  PIN do0[422]
    DIRECTION OUTPUT ;
    USE SIGNAL ;
    PORT
      LAYER M3 ;
        RECT  43.056 25.776 43.074 25.92 ;
    END
  END do0[422]
  PIN do0[423]
    DIRECTION OUTPUT ;
    USE SIGNAL ;
    PORT
      LAYER M5 ;
        RECT  43.152 25.728 43.176 25.92 ;
    END
  END do0[423]
  PIN do0[424]
    DIRECTION OUTPUT ;
    USE SIGNAL ;
    PORT
      LAYER M3 ;
        RECT  43.236 25.776 43.254 25.92 ;
    END
  END do0[424]
  PIN do0[425]
    DIRECTION OUTPUT ;
    USE SIGNAL ;
    PORT
      LAYER M5 ;
        RECT  43.344 25.728 43.368 25.92 ;
    END
  END do0[425]
  PIN do0[426]
    DIRECTION OUTPUT ;
    USE SIGNAL ;
    PORT
      LAYER M3 ;
        RECT  43.416 25.776 43.434 25.92 ;
    END
  END do0[426]
  PIN do0[427]
    DIRECTION OUTPUT ;
    USE SIGNAL ;
    PORT
      LAYER M5 ;
        RECT  43.488 25.728 43.512 25.92 ;
    END
  END do0[427]
  PIN do0[428]
    DIRECTION OUTPUT ;
    USE SIGNAL ;
    PORT
      LAYER M3 ;
        RECT  43.596 25.776 43.614 25.92 ;
    END
  END do0[428]
  PIN do0[429]
    DIRECTION OUTPUT ;
    USE SIGNAL ;
    PORT
      LAYER M5 ;
        RECT  43.68 25.728 43.704 25.92 ;
    END
  END do0[429]
  PIN do0[42]
    DIRECTION OUTPUT ;
    USE SIGNAL ;
    PORT
      LAYER M3 ;
        RECT  8.172 25.776 8.19 25.92 ;
    END
  END do0[42]
  PIN do0[430]
    DIRECTION OUTPUT ;
    USE SIGNAL ;
    PORT
      LAYER M3 ;
        RECT  43.776 25.776 43.794 25.92 ;
    END
  END do0[430]
  PIN do0[431]
    DIRECTION OUTPUT ;
    USE SIGNAL ;
    PORT
      LAYER M5 ;
        RECT  43.872 25.728 43.896 25.92 ;
    END
  END do0[431]
  PIN do0[432]
    DIRECTION OUTPUT ;
    USE SIGNAL ;
    PORT
      LAYER M3 ;
        RECT  43.956 25.776 43.974 25.92 ;
    END
  END do0[432]
  PIN do0[433]
    DIRECTION OUTPUT ;
    USE SIGNAL ;
    PORT
      LAYER M5 ;
        RECT  44.064 25.728 44.088 25.92 ;
    END
  END do0[433]
  PIN do0[434]
    DIRECTION OUTPUT ;
    USE SIGNAL ;
    PORT
      LAYER M3 ;
        RECT  44.136 25.776 44.154 25.92 ;
    END
  END do0[434]
  PIN do0[435]
    DIRECTION OUTPUT ;
    USE SIGNAL ;
    PORT
      LAYER M5 ;
        RECT  44.256 25.728 44.28 25.92 ;
    END
  END do0[435]
  PIN do0[436]
    DIRECTION OUTPUT ;
    USE SIGNAL ;
    PORT
      LAYER M3 ;
        RECT  44.316 25.776 44.334 25.92 ;
    END
  END do0[436]
  PIN do0[437]
    DIRECTION OUTPUT ;
    USE SIGNAL ;
    PORT
      LAYER M5 ;
        RECT  44.4 25.728 44.424 25.92 ;
    END
  END do0[437]
  PIN do0[438]
    DIRECTION OUTPUT ;
    USE SIGNAL ;
    PORT
      LAYER M3 ;
        RECT  44.532 25.776 44.55 25.92 ;
    END
  END do0[438]
  PIN do0[439]
    DIRECTION OUTPUT ;
    USE SIGNAL ;
    PORT
      LAYER M5 ;
        RECT  44.592 25.728 44.616 25.92 ;
    END
  END do0[439]
  PIN do0[43]
    DIRECTION OUTPUT ;
    USE SIGNAL ;
    PORT
      LAYER M5 ;
        RECT  8.256 25.728 8.28 25.92 ;
    END
  END do0[43]
  PIN do0[440]
    DIRECTION OUTPUT ;
    USE SIGNAL ;
    PORT
      LAYER M3 ;
        RECT  44.712 25.776 44.73 25.92 ;
    END
  END do0[440]
  PIN do0[441]
    DIRECTION OUTPUT ;
    USE SIGNAL ;
    PORT
      LAYER M5 ;
        RECT  44.784 25.728 44.808 25.92 ;
    END
  END do0[441]
  PIN do0[442]
    DIRECTION OUTPUT ;
    USE SIGNAL ;
    PORT
      LAYER M3 ;
        RECT  44.892 25.776 44.91 25.92 ;
    END
  END do0[442]
  PIN do0[443]
    DIRECTION OUTPUT ;
    USE SIGNAL ;
    PORT
      LAYER M5 ;
        RECT  44.976 25.728 45 25.92 ;
    END
  END do0[443]
  PIN do0[444]
    DIRECTION OUTPUT ;
    USE SIGNAL ;
    PORT
      LAYER M3 ;
        RECT  45.072 25.776 45.09 25.92 ;
    END
  END do0[444]
  PIN do0[445]
    DIRECTION OUTPUT ;
    USE SIGNAL ;
    PORT
      LAYER M5 ;
        RECT  45.168 25.728 45.192 25.92 ;
    END
  END do0[445]
  PIN do0[446]
    DIRECTION OUTPUT ;
    USE SIGNAL ;
    PORT
      LAYER M3 ;
        RECT  45.252 25.776 45.27 25.92 ;
    END
  END do0[446]
  PIN do0[447]
    DIRECTION OUTPUT ;
    USE SIGNAL ;
    PORT
      LAYER M5 ;
        RECT  45.312 25.728 45.336 25.92 ;
    END
  END do0[447]
  PIN do0[448]
    DIRECTION OUTPUT ;
    USE SIGNAL ;
    PORT
      LAYER M3 ;
        RECT  45.432 25.776 45.45 25.92 ;
    END
  END do0[448]
  PIN do0[449]
    DIRECTION OUTPUT ;
    USE SIGNAL ;
    PORT
      LAYER M5 ;
        RECT  45.504 25.728 45.528 25.92 ;
    END
  END do0[449]
  PIN do0[44]
    DIRECTION OUTPUT ;
    USE SIGNAL ;
    PORT
      LAYER M3 ;
        RECT  8.388 25.776 8.406 25.92 ;
    END
  END do0[44]
  PIN do0[450]
    DIRECTION OUTPUT ;
    USE SIGNAL ;
    PORT
      LAYER M3 ;
        RECT  45.612 25.776 45.63 25.92 ;
    END
  END do0[450]
  PIN do0[451]
    DIRECTION OUTPUT ;
    USE SIGNAL ;
    PORT
      LAYER M5 ;
        RECT  45.696 25.728 45.72 25.92 ;
    END
  END do0[451]
  PIN do0[452]
    DIRECTION OUTPUT ;
    USE SIGNAL ;
    PORT
      LAYER M3 ;
        RECT  45.792 25.776 45.81 25.92 ;
    END
  END do0[452]
  PIN do0[453]
    DIRECTION OUTPUT ;
    USE SIGNAL ;
    PORT
      LAYER M5 ;
        RECT  45.888 25.728 45.912 25.92 ;
    END
  END do0[453]
  PIN do0[454]
    DIRECTION OUTPUT ;
    USE SIGNAL ;
    PORT
      LAYER M3 ;
        RECT  45.972 25.776 45.99 25.92 ;
    END
  END do0[454]
  PIN do0[455]
    DIRECTION OUTPUT ;
    USE SIGNAL ;
    PORT
      LAYER M5 ;
        RECT  46.08 25.728 46.104 25.92 ;
    END
  END do0[455]
  PIN do0[456]
    DIRECTION OUTPUT ;
    USE SIGNAL ;
    PORT
      LAYER M3 ;
        RECT  46.152 25.776 46.17 25.92 ;
    END
  END do0[456]
  PIN do0[457]
    DIRECTION OUTPUT ;
    USE SIGNAL ;
    PORT
      LAYER M5 ;
        RECT  46.224 25.728 46.248 25.92 ;
    END
  END do0[457]
  PIN do0[458]
    DIRECTION OUTPUT ;
    USE SIGNAL ;
    PORT
      LAYER M3 ;
        RECT  46.332 25.776 46.35 25.92 ;
    END
  END do0[458]
  PIN do0[459]
    DIRECTION OUTPUT ;
    USE SIGNAL ;
    PORT
      LAYER M5 ;
        RECT  46.416 25.728 46.44 25.92 ;
    END
  END do0[459]
  PIN do0[45]
    DIRECTION OUTPUT ;
    USE SIGNAL ;
    PORT
      LAYER M5 ;
        RECT  8.448 25.728 8.472 25.92 ;
    END
  END do0[45]
  PIN do0[460]
    DIRECTION OUTPUT ;
    USE SIGNAL ;
    PORT
      LAYER M3 ;
        RECT  46.512 25.776 46.53 25.92 ;
    END
  END do0[460]
  PIN do0[461]
    DIRECTION OUTPUT ;
    USE SIGNAL ;
    PORT
      LAYER M5 ;
        RECT  46.608 25.728 46.632 25.92 ;
    END
  END do0[461]
  PIN do0[462]
    DIRECTION OUTPUT ;
    USE SIGNAL ;
    PORT
      LAYER M3 ;
        RECT  46.692 25.776 46.71 25.92 ;
    END
  END do0[462]
  PIN do0[463]
    DIRECTION OUTPUT ;
    USE SIGNAL ;
    PORT
      LAYER M5 ;
        RECT  46.8 25.728 46.824 25.92 ;
    END
  END do0[463]
  PIN do0[464]
    DIRECTION OUTPUT ;
    USE SIGNAL ;
    PORT
      LAYER M3 ;
        RECT  46.872 25.776 46.89 25.92 ;
    END
  END do0[464]
  PIN do0[465]
    DIRECTION OUTPUT ;
    USE SIGNAL ;
    PORT
      LAYER M5 ;
        RECT  46.992 25.728 47.016 25.92 ;
    END
  END do0[465]
  PIN do0[466]
    DIRECTION OUTPUT ;
    USE SIGNAL ;
    PORT
      LAYER M3 ;
        RECT  47.052 25.776 47.07 25.92 ;
    END
  END do0[466]
  PIN do0[467]
    DIRECTION OUTPUT ;
    USE SIGNAL ;
    PORT
      LAYER M5 ;
        RECT  47.136 25.728 47.16 25.92 ;
    END
  END do0[467]
  PIN do0[468]
    DIRECTION OUTPUT ;
    USE SIGNAL ;
    PORT
      LAYER M3 ;
        RECT  47.268 25.776 47.286 25.92 ;
    END
  END do0[468]
  PIN do0[469]
    DIRECTION OUTPUT ;
    USE SIGNAL ;
    PORT
      LAYER M5 ;
        RECT  47.328 25.728 47.352 25.92 ;
    END
  END do0[469]
  PIN do0[46]
    DIRECTION OUTPUT ;
    USE SIGNAL ;
    PORT
      LAYER M3 ;
        RECT  8.568 25.776 8.586 25.92 ;
    END
  END do0[46]
  PIN do0[470]
    DIRECTION OUTPUT ;
    USE SIGNAL ;
    PORT
      LAYER M3 ;
        RECT  47.448 25.776 47.466 25.92 ;
    END
  END do0[470]
  PIN do0[471]
    DIRECTION OUTPUT ;
    USE SIGNAL ;
    PORT
      LAYER M5 ;
        RECT  47.52 25.728 47.544 25.92 ;
    END
  END do0[471]
  PIN do0[472]
    DIRECTION OUTPUT ;
    USE SIGNAL ;
    PORT
      LAYER M3 ;
        RECT  47.628 25.776 47.646 25.92 ;
    END
  END do0[472]
  PIN do0[473]
    DIRECTION OUTPUT ;
    USE SIGNAL ;
    PORT
      LAYER M5 ;
        RECT  47.712 25.728 47.736 25.92 ;
    END
  END do0[473]
  PIN do0[474]
    DIRECTION OUTPUT ;
    USE SIGNAL ;
    PORT
      LAYER M3 ;
        RECT  47.808 25.776 47.826 25.92 ;
    END
  END do0[474]
  PIN do0[475]
    DIRECTION OUTPUT ;
    USE SIGNAL ;
    PORT
      LAYER M5 ;
        RECT  47.904 25.728 47.928 25.92 ;
    END
  END do0[475]
  PIN do0[476]
    DIRECTION OUTPUT ;
    USE SIGNAL ;
    PORT
      LAYER M3 ;
        RECT  47.988 25.776 48.006 25.92 ;
    END
  END do0[476]
  PIN do0[477]
    DIRECTION OUTPUT ;
    USE SIGNAL ;
    PORT
      LAYER M5 ;
        RECT  48.048 25.728 48.072 25.92 ;
    END
  END do0[477]
  PIN do0[478]
    DIRECTION OUTPUT ;
    USE SIGNAL ;
    PORT
      LAYER M3 ;
        RECT  48.168 25.776 48.186 25.92 ;
    END
  END do0[478]
  PIN do0[479]
    DIRECTION OUTPUT ;
    USE SIGNAL ;
    PORT
      LAYER M5 ;
        RECT  48.24 25.728 48.264 25.92 ;
    END
  END do0[479]
  PIN do0[47]
    DIRECTION OUTPUT ;
    USE SIGNAL ;
    PORT
      LAYER M5 ;
        RECT  8.64 25.728 8.664 25.92 ;
    END
  END do0[47]
  PIN do0[480]
    DIRECTION OUTPUT ;
    USE SIGNAL ;
    PORT
      LAYER M3 ;
        RECT  48.348 25.776 48.366 25.92 ;
    END
  END do0[480]
  PIN do0[481]
    DIRECTION OUTPUT ;
    USE SIGNAL ;
    PORT
      LAYER M5 ;
        RECT  48.432 25.728 48.456 25.92 ;
    END
  END do0[481]
  PIN do0[482]
    DIRECTION OUTPUT ;
    USE SIGNAL ;
    PORT
      LAYER M3 ;
        RECT  48.528 25.776 48.546 25.92 ;
    END
  END do0[482]
  PIN do0[483]
    DIRECTION OUTPUT ;
    USE SIGNAL ;
    PORT
      LAYER M5 ;
        RECT  48.624 25.728 48.648 25.92 ;
    END
  END do0[483]
  PIN do0[484]
    DIRECTION OUTPUT ;
    USE SIGNAL ;
    PORT
      LAYER M3 ;
        RECT  48.708 25.776 48.726 25.92 ;
    END
  END do0[484]
  PIN do0[485]
    DIRECTION OUTPUT ;
    USE SIGNAL ;
    PORT
      LAYER M5 ;
        RECT  48.816 25.728 48.84 25.92 ;
    END
  END do0[485]
  PIN do0[486]
    DIRECTION OUTPUT ;
    USE SIGNAL ;
    PORT
      LAYER M3 ;
        RECT  48.888 25.776 48.906 25.92 ;
    END
  END do0[486]
  PIN do0[487]
    DIRECTION OUTPUT ;
    USE SIGNAL ;
    PORT
      LAYER M5 ;
        RECT  48.96 25.728 48.984 25.92 ;
    END
  END do0[487]
  PIN do0[488]
    DIRECTION OUTPUT ;
    USE SIGNAL ;
    PORT
      LAYER M3 ;
        RECT  49.068 25.776 49.086 25.92 ;
    END
  END do0[488]
  PIN do0[489]
    DIRECTION OUTPUT ;
    USE SIGNAL ;
    PORT
      LAYER M5 ;
        RECT  49.152 25.728 49.176 25.92 ;
    END
  END do0[489]
  PIN do0[48]
    DIRECTION OUTPUT ;
    USE SIGNAL ;
    PORT
      LAYER M3 ;
        RECT  8.748 25.776 8.766 25.92 ;
    END
  END do0[48]
  PIN do0[490]
    DIRECTION OUTPUT ;
    USE SIGNAL ;
    PORT
      LAYER M3 ;
        RECT  49.248 25.776 49.266 25.92 ;
    END
  END do0[490]
  PIN do0[491]
    DIRECTION OUTPUT ;
    USE SIGNAL ;
    PORT
      LAYER M5 ;
        RECT  49.344 25.728 49.368 25.92 ;
    END
  END do0[491]
  PIN do0[492]
    DIRECTION OUTPUT ;
    USE SIGNAL ;
    PORT
      LAYER M3 ;
        RECT  49.428 25.776 49.446 25.92 ;
    END
  END do0[492]
  PIN do0[493]
    DIRECTION OUTPUT ;
    USE SIGNAL ;
    PORT
      LAYER M5 ;
        RECT  49.536 25.728 49.56 25.92 ;
    END
  END do0[493]
  PIN do0[494]
    DIRECTION OUTPUT ;
    USE SIGNAL ;
    PORT
      LAYER M3 ;
        RECT  49.608 25.776 49.626 25.92 ;
    END
  END do0[494]
  PIN do0[495]
    DIRECTION OUTPUT ;
    USE SIGNAL ;
    PORT
      LAYER M5 ;
        RECT  49.728 25.728 49.752 25.92 ;
    END
  END do0[495]
  PIN do0[496]
    DIRECTION OUTPUT ;
    USE SIGNAL ;
    PORT
      LAYER M3 ;
        RECT  49.824 25.776 49.842 25.92 ;
    END
  END do0[496]
  PIN do0[497]
    DIRECTION OUTPUT ;
    USE SIGNAL ;
    PORT
      LAYER M5 ;
        RECT  49.92 25.728 49.944 25.92 ;
    END
  END do0[497]
  PIN do0[498]
    DIRECTION OUTPUT ;
    USE SIGNAL ;
    PORT
      LAYER M3 ;
        RECT  50.004 25.776 50.022 25.92 ;
    END
  END do0[498]
  PIN do0[499]
    DIRECTION OUTPUT ;
    USE SIGNAL ;
    PORT
      LAYER M5 ;
        RECT  50.064 25.728 50.088 25.92 ;
    END
  END do0[499]
  PIN do0[49]
    DIRECTION OUTPUT ;
    USE SIGNAL ;
    PORT
      LAYER M5 ;
        RECT  8.832 25.728 8.856 25.92 ;
    END
  END do0[49]
  PIN do0[4]
    DIRECTION OUTPUT ;
    USE SIGNAL ;
    PORT
      LAYER M3 ;
        RECT  4.716 25.776 4.734 25.92 ;
    END
  END do0[4]
  PIN do0[500]
    DIRECTION OUTPUT ;
    USE SIGNAL ;
    PORT
      LAYER M3 ;
        RECT  50.184 25.776 50.202 25.92 ;
    END
  END do0[500]
  PIN do0[501]
    DIRECTION OUTPUT ;
    USE SIGNAL ;
    PORT
      LAYER M5 ;
        RECT  50.256 25.728 50.28 25.92 ;
    END
  END do0[501]
  PIN do0[502]
    DIRECTION OUTPUT ;
    USE SIGNAL ;
    PORT
      LAYER M3 ;
        RECT  50.364 25.776 50.382 25.92 ;
    END
  END do0[502]
  PIN do0[503]
    DIRECTION OUTPUT ;
    USE SIGNAL ;
    PORT
      LAYER M5 ;
        RECT  50.448 25.728 50.472 25.92 ;
    END
  END do0[503]
  PIN do0[504]
    DIRECTION OUTPUT ;
    USE SIGNAL ;
    PORT
      LAYER M3 ;
        RECT  50.544 25.776 50.562 25.92 ;
    END
  END do0[504]
  PIN do0[505]
    DIRECTION OUTPUT ;
    USE SIGNAL ;
    PORT
      LAYER M5 ;
        RECT  50.64 25.728 50.664 25.92 ;
    END
  END do0[505]
  PIN do0[506]
    DIRECTION OUTPUT ;
    USE SIGNAL ;
    PORT
      LAYER M3 ;
        RECT  50.724 25.776 50.742 25.92 ;
    END
  END do0[506]
  PIN do0[507]
    DIRECTION OUTPUT ;
    USE SIGNAL ;
    PORT
      LAYER M5 ;
        RECT  50.832 25.728 50.856 25.92 ;
    END
  END do0[507]
  PIN do0[508]
    DIRECTION OUTPUT ;
    USE SIGNAL ;
    PORT
      LAYER M3 ;
        RECT  50.904 25.776 50.922 25.92 ;
    END
  END do0[508]
  PIN do0[509]
    DIRECTION OUTPUT ;
    USE SIGNAL ;
    PORT
      LAYER M5 ;
        RECT  50.976 25.728 51 25.92 ;
    END
  END do0[509]
  PIN do0[50]
    DIRECTION OUTPUT ;
    USE SIGNAL ;
    PORT
      LAYER M3 ;
        RECT  8.928 25.776 8.946 25.92 ;
    END
  END do0[50]
  PIN do0[510]
    DIRECTION OUTPUT ;
    USE SIGNAL ;
    PORT
      LAYER M3 ;
        RECT  51.084 25.776 51.102 25.92 ;
    END
  END do0[510]
  PIN do0[511]
    DIRECTION OUTPUT ;
    USE SIGNAL ;
    PORT
      LAYER M5 ;
        RECT  51.168 25.728 51.192 25.92 ;
    END
  END do0[511]
  PIN do0[512]
    DIRECTION OUTPUT ;
    USE SIGNAL ;
    PORT
      LAYER M3 ;
        RECT  51.264 25.776 51.282 25.92 ;
    END
  END do0[512]
  PIN do0[513]
    DIRECTION OUTPUT ;
    USE SIGNAL ;
    PORT
      LAYER M5 ;
        RECT  51.36 25.728 51.384 25.92 ;
    END
  END do0[513]
  PIN do0[514]
    DIRECTION OUTPUT ;
    USE SIGNAL ;
    PORT
      LAYER M3 ;
        RECT  51.444 25.776 51.462 25.92 ;
    END
  END do0[514]
  PIN do0[515]
    DIRECTION OUTPUT ;
    USE SIGNAL ;
    PORT
      LAYER M5 ;
        RECT  51.552 25.728 51.576 25.92 ;
    END
  END do0[515]
  PIN do0[516]
    DIRECTION OUTPUT ;
    USE SIGNAL ;
    PORT
      LAYER M3 ;
        RECT  51.624 25.776 51.642 25.92 ;
    END
  END do0[516]
  PIN do0[517]
    DIRECTION OUTPUT ;
    USE SIGNAL ;
    PORT
      LAYER M5 ;
        RECT  51.744 25.728 51.768 25.92 ;
    END
  END do0[517]
  PIN do0[518]
    DIRECTION OUTPUT ;
    USE SIGNAL ;
    PORT
      LAYER M3 ;
        RECT  51.804 25.776 51.822 25.92 ;
    END
  END do0[518]
  PIN do0[519]
    DIRECTION OUTPUT ;
    USE SIGNAL ;
    PORT
      LAYER M5 ;
        RECT  51.888 25.728 51.912 25.92 ;
    END
  END do0[519]
  PIN do0[51]
    DIRECTION OUTPUT ;
    USE SIGNAL ;
    PORT
      LAYER M5 ;
        RECT  9.024 25.728 9.048 25.92 ;
    END
  END do0[51]
  PIN do0[520]
    DIRECTION OUTPUT ;
    USE SIGNAL ;
    PORT
      LAYER M3 ;
        RECT  51.984 25.776 52.002 25.92 ;
    END
  END do0[520]
  PIN do0[521]
    DIRECTION OUTPUT ;
    USE SIGNAL ;
    PORT
      LAYER M5 ;
        RECT  52.08 25.728 52.104 25.92 ;
    END
  END do0[521]
  PIN do0[522]
    DIRECTION OUTPUT ;
    USE SIGNAL ;
    PORT
      LAYER M3 ;
        RECT  52.164 25.776 52.182 25.92 ;
    END
  END do0[522]
  PIN do0[523]
    DIRECTION OUTPUT ;
    USE SIGNAL ;
    PORT
      LAYER M5 ;
        RECT  52.272 25.728 52.296 25.92 ;
    END
  END do0[523]
  PIN do0[524]
    DIRECTION OUTPUT ;
    USE SIGNAL ;
    PORT
      LAYER M3 ;
        RECT  52.38 25.776 52.398 25.92 ;
    END
  END do0[524]
  PIN do0[525]
    DIRECTION OUTPUT ;
    USE SIGNAL ;
    PORT
      LAYER M5 ;
        RECT  52.464 25.728 52.488 25.92 ;
    END
  END do0[525]
  PIN do0[526]
    DIRECTION OUTPUT ;
    USE SIGNAL ;
    PORT
      LAYER M3 ;
        RECT  52.56 25.776 52.578 25.92 ;
    END
  END do0[526]
  PIN do0[527]
    DIRECTION OUTPUT ;
    USE SIGNAL ;
    PORT
      LAYER M5 ;
        RECT  52.656 25.728 52.68 25.92 ;
    END
  END do0[527]
  PIN do0[528]
    DIRECTION OUTPUT ;
    USE SIGNAL ;
    PORT
      LAYER M3 ;
        RECT  52.74 25.776 52.758 25.92 ;
    END
  END do0[528]
  PIN do0[529]
    DIRECTION OUTPUT ;
    USE SIGNAL ;
    PORT
      LAYER M5 ;
        RECT  52.8 25.728 52.824 25.92 ;
    END
  END do0[529]
  PIN do0[52]
    DIRECTION OUTPUT ;
    USE SIGNAL ;
    PORT
      LAYER M3 ;
        RECT  9.108 25.776 9.126 25.92 ;
    END
  END do0[52]
  PIN do0[530]
    DIRECTION OUTPUT ;
    USE SIGNAL ;
    PORT
      LAYER M3 ;
        RECT  52.92 25.776 52.938 25.92 ;
    END
  END do0[530]
  PIN do0[531]
    DIRECTION OUTPUT ;
    USE SIGNAL ;
    PORT
      LAYER M5 ;
        RECT  52.992 25.728 53.016 25.92 ;
    END
  END do0[531]
  PIN do0[532]
    DIRECTION OUTPUT ;
    USE SIGNAL ;
    PORT
      LAYER M3 ;
        RECT  53.1 25.776 53.118 25.92 ;
    END
  END do0[532]
  PIN do0[533]
    DIRECTION OUTPUT ;
    USE SIGNAL ;
    PORT
      LAYER M5 ;
        RECT  53.184 25.728 53.208 25.92 ;
    END
  END do0[533]
  PIN do0[534]
    DIRECTION OUTPUT ;
    USE SIGNAL ;
    PORT
      LAYER M3 ;
        RECT  53.28 25.776 53.298 25.92 ;
    END
  END do0[534]
  PIN do0[535]
    DIRECTION OUTPUT ;
    USE SIGNAL ;
    PORT
      LAYER M5 ;
        RECT  53.376 25.728 53.4 25.92 ;
    END
  END do0[535]
  PIN do0[536]
    DIRECTION OUTPUT ;
    USE SIGNAL ;
    PORT
      LAYER M3 ;
        RECT  53.46 25.776 53.478 25.92 ;
    END
  END do0[536]
  PIN do0[537]
    DIRECTION OUTPUT ;
    USE SIGNAL ;
    PORT
      LAYER M5 ;
        RECT  53.568 25.728 53.592 25.92 ;
    END
  END do0[537]
  PIN do0[538]
    DIRECTION OUTPUT ;
    USE SIGNAL ;
    PORT
      LAYER M3 ;
        RECT  53.64 25.776 53.658 25.92 ;
    END
    PORT
      LAYER M3 ;
        RECT  53.604 25.788 53.73 25.853 ;
    END
  END do0[538]
  PIN do0[539]
    DIRECTION OUTPUT ;
    USE SIGNAL ;
    PORT
      LAYER M5 ;
        RECT  53.712 25.728 53.736 25.92 ;
    END
  END do0[539]
  PIN do0[53]
    DIRECTION OUTPUT ;
    USE SIGNAL ;
    PORT
      LAYER M5 ;
        RECT  9.168 25.728 9.192 25.92 ;
    END
  END do0[53]
  PIN do0[540]
    DIRECTION OUTPUT ;
    USE SIGNAL ;
    PORT
      LAYER M3 ;
        RECT  53.82 25.776 53.838 25.92 ;
    END
  END do0[540]
  PIN do0[541]
    DIRECTION OUTPUT ;
    USE SIGNAL ;
    PORT
      LAYER M5 ;
        RECT  53.904 25.728 53.928 25.92 ;
    END
  END do0[541]
  PIN do0[542]
    DIRECTION OUTPUT ;
    USE SIGNAL ;
    PORT
      LAYER M3 ;
        RECT  54 25.776 54.018 25.92 ;
    END
  END do0[542]
  PIN do0[543]
    DIRECTION OUTPUT ;
    USE SIGNAL ;
    PORT
      LAYER M5 ;
        RECT  54.096 25.728 54.12 25.92 ;
    END
  END do0[543]
  PIN do0[544]
    DIRECTION OUTPUT ;
    USE SIGNAL ;
    PORT
      LAYER M3 ;
        RECT  54.18 25.776 54.198 25.92 ;
    END
  END do0[544]
  PIN do0[545]
    DIRECTION OUTPUT ;
    USE SIGNAL ;
    PORT
      LAYER M5 ;
        RECT  54.288 25.728 54.312 25.92 ;
    END
  END do0[545]
  PIN do0[546]
    DIRECTION OUTPUT ;
    USE SIGNAL ;
    PORT
      LAYER M3 ;
        RECT  54.36 25.776 54.378 25.92 ;
    END
  END do0[546]
  PIN do0[547]
    DIRECTION OUTPUT ;
    USE SIGNAL ;
    PORT
      LAYER M5 ;
        RECT  54.48 25.728 54.504 25.92 ;
    END
  END do0[547]
  PIN do0[548]
    DIRECTION OUTPUT ;
    USE SIGNAL ;
    PORT
      LAYER M3 ;
        RECT  54.54 25.776 54.558 25.92 ;
    END
  END do0[548]
  PIN do0[549]
    DIRECTION OUTPUT ;
    USE SIGNAL ;
    PORT
      LAYER M5 ;
        RECT  54.624 25.728 54.648 25.92 ;
    END
  END do0[549]
  PIN do0[54]
    DIRECTION OUTPUT ;
    USE SIGNAL ;
    PORT
      LAYER M3 ;
        RECT  9.288 25.776 9.306 25.92 ;
    END
  END do0[54]
  PIN do0[550]
    DIRECTION OUTPUT ;
    USE SIGNAL ;
    PORT
      LAYER M3 ;
        RECT  54.72 25.776 54.738 25.92 ;
    END
  END do0[550]
  PIN do0[551]
    DIRECTION OUTPUT ;
    USE SIGNAL ;
    PORT
      LAYER M5 ;
        RECT  54.816 25.728 54.84 25.92 ;
    END
  END do0[551]
  PIN do0[552]
    DIRECTION OUTPUT ;
    USE SIGNAL ;
    PORT
      LAYER M3 ;
        RECT  54.936 25.776 54.954 25.92 ;
    END
  END do0[552]
  PIN do0[553]
    DIRECTION OUTPUT ;
    USE SIGNAL ;
    PORT
      LAYER M5 ;
        RECT  55.008 25.728 55.032 25.92 ;
    END
  END do0[553]
  PIN do0[554]
    DIRECTION OUTPUT ;
    USE SIGNAL ;
    PORT
      LAYER M3 ;
        RECT  55.116 25.776 55.134 25.92 ;
    END
  END do0[554]
  PIN do0[555]
    DIRECTION OUTPUT ;
    USE SIGNAL ;
    PORT
      LAYER M5 ;
        RECT  55.2 25.728 55.224 25.92 ;
    END
  END do0[555]
  PIN do0[556]
    DIRECTION OUTPUT ;
    USE SIGNAL ;
    PORT
      LAYER M3 ;
        RECT  55.296 25.776 55.314 25.92 ;
    END
  END do0[556]
  PIN do0[557]
    DIRECTION OUTPUT ;
    USE SIGNAL ;
    PORT
      LAYER M5 ;
        RECT  55.392 25.728 55.416 25.92 ;
    END
  END do0[557]
  PIN do0[558]
    DIRECTION OUTPUT ;
    USE SIGNAL ;
    PORT
      LAYER M3 ;
        RECT  55.476 25.776 55.494 25.92 ;
    END
  END do0[558]
  PIN do0[559]
    DIRECTION OUTPUT ;
    USE SIGNAL ;
    PORT
      LAYER M5 ;
        RECT  55.536 25.728 55.56 25.92 ;
    END
  END do0[559]
  PIN do0[55]
    DIRECTION OUTPUT ;
    USE SIGNAL ;
    PORT
      LAYER M5 ;
        RECT  9.36 25.728 9.384 25.92 ;
    END
  END do0[55]
  PIN do0[560]
    DIRECTION OUTPUT ;
    USE SIGNAL ;
    PORT
      LAYER M3 ;
        RECT  55.656 25.776 55.674 25.92 ;
    END
  END do0[560]
  PIN do0[561]
    DIRECTION OUTPUT ;
    USE SIGNAL ;
    PORT
      LAYER M5 ;
        RECT  55.728 25.728 55.752 25.92 ;
    END
  END do0[561]
  PIN do0[562]
    DIRECTION OUTPUT ;
    USE SIGNAL ;
    PORT
      LAYER M3 ;
        RECT  55.836 25.776 55.854 25.92 ;
    END
  END do0[562]
  PIN do0[563]
    DIRECTION OUTPUT ;
    USE SIGNAL ;
    PORT
      LAYER M5 ;
        RECT  55.92 25.728 55.944 25.92 ;
    END
  END do0[563]
  PIN do0[564]
    DIRECTION OUTPUT ;
    USE SIGNAL ;
    PORT
      LAYER M3 ;
        RECT  56.016 25.776 56.034 25.92 ;
    END
  END do0[564]
  PIN do0[565]
    DIRECTION OUTPUT ;
    USE SIGNAL ;
    PORT
      LAYER M5 ;
        RECT  56.112 25.728 56.136 25.92 ;
    END
  END do0[565]
  PIN do0[56]
    DIRECTION OUTPUT ;
    USE SIGNAL ;
    PORT
      LAYER M3 ;
        RECT  9.468 25.776 9.486 25.92 ;
    END
  END do0[56]
  PIN do0[57]
    DIRECTION OUTPUT ;
    USE SIGNAL ;
    PORT
      LAYER M5 ;
        RECT  9.552 25.728 9.576 25.92 ;
    END
  END do0[57]
  PIN do0[58]
    DIRECTION OUTPUT ;
    USE SIGNAL ;
    PORT
      LAYER M3 ;
        RECT  9.648 25.776 9.666 25.92 ;
    END
  END do0[58]
  PIN do0[59]
    DIRECTION OUTPUT ;
    USE SIGNAL ;
    PORT
      LAYER M5 ;
        RECT  9.744 25.728 9.768 25.92 ;
    END
  END do0[59]
  PIN do0[5]
    DIRECTION OUTPUT ;
    USE SIGNAL ;
    PORT
      LAYER M5 ;
        RECT  4.8 25.728 4.824 25.92 ;
    END
  END do0[5]
  PIN do0[60]
    DIRECTION OUTPUT ;
    USE SIGNAL ;
    PORT
      LAYER M3 ;
        RECT  9.828 25.776 9.846 25.92 ;
    END
  END do0[60]
  PIN do0[61]
    DIRECTION OUTPUT ;
    USE SIGNAL ;
    PORT
      LAYER M5 ;
        RECT  9.936 25.728 9.96 25.92 ;
    END
  END do0[61]
  PIN do0[62]
    DIRECTION OUTPUT ;
    USE SIGNAL ;
    PORT
      LAYER M3 ;
        RECT  10.008 25.776 10.026 25.92 ;
    END
  END do0[62]
  PIN do0[63]
    DIRECTION OUTPUT ;
    USE SIGNAL ;
    PORT
      LAYER M5 ;
        RECT  10.08 25.728 10.104 25.92 ;
    END
  END do0[63]
  PIN do0[64]
    DIRECTION OUTPUT ;
    USE SIGNAL ;
    PORT
      LAYER M3 ;
        RECT  10.188 25.776 10.206 25.92 ;
    END
  END do0[64]
  PIN do0[65]
    DIRECTION OUTPUT ;
    USE SIGNAL ;
    PORT
      LAYER M5 ;
        RECT  10.272 25.728 10.296 25.92 ;
    END
  END do0[65]
  PIN do0[66]
    DIRECTION OUTPUT ;
    USE SIGNAL ;
    PORT
      LAYER M3 ;
        RECT  10.368 25.776 10.386 25.92 ;
    END
  END do0[66]
  PIN do0[67]
    DIRECTION OUTPUT ;
    USE SIGNAL ;
    PORT
      LAYER M5 ;
        RECT  10.464 25.728 10.488 25.92 ;
    END
  END do0[67]
  PIN do0[68]
    DIRECTION OUTPUT ;
    USE SIGNAL ;
    PORT
      LAYER M3 ;
        RECT  10.548 25.776 10.566 25.92 ;
    END
  END do0[68]
  PIN do0[69]
    DIRECTION OUTPUT ;
    USE SIGNAL ;
    PORT
      LAYER M5 ;
        RECT  10.656 25.728 10.68 25.92 ;
    END
  END do0[69]
  PIN do0[6]
    DIRECTION OUTPUT ;
    USE SIGNAL ;
    PORT
      LAYER M3 ;
        RECT  4.896 25.776 4.914 25.92 ;
    END
  END do0[6]
  PIN do0[70]
    DIRECTION OUTPUT ;
    USE SIGNAL ;
    PORT
      LAYER M3 ;
        RECT  10.728 25.776 10.746 25.92 ;
    END
  END do0[70]
  PIN do0[71]
    DIRECTION OUTPUT ;
    USE SIGNAL ;
    PORT
      LAYER M5 ;
        RECT  10.848 25.728 10.872 25.92 ;
    END
  END do0[71]
  PIN do0[72]
    DIRECTION OUTPUT ;
    USE SIGNAL ;
    PORT
      LAYER M3 ;
        RECT  10.944 25.776 10.962 25.92 ;
    END
  END do0[72]
  PIN do0[73]
    DIRECTION OUTPUT ;
    USE SIGNAL ;
    PORT
      LAYER M5 ;
        RECT  11.04 25.728 11.064 25.92 ;
    END
  END do0[73]
  PIN do0[74]
    DIRECTION OUTPUT ;
    USE SIGNAL ;
    PORT
      LAYER M3 ;
        RECT  11.124 25.776 11.142 25.92 ;
    END
  END do0[74]
  PIN do0[75]
    DIRECTION OUTPUT ;
    USE SIGNAL ;
    PORT
      LAYER M5 ;
        RECT  11.184 25.728 11.208 25.92 ;
    END
  END do0[75]
  PIN do0[76]
    DIRECTION OUTPUT ;
    USE SIGNAL ;
    PORT
      LAYER M3 ;
        RECT  11.304 25.776 11.322 25.92 ;
    END
  END do0[76]
  PIN do0[77]
    DIRECTION OUTPUT ;
    USE SIGNAL ;
    PORT
      LAYER M5 ;
        RECT  11.376 25.728 11.4 25.92 ;
    END
  END do0[77]
  PIN do0[78]
    DIRECTION OUTPUT ;
    USE SIGNAL ;
    PORT
      LAYER M3 ;
        RECT  11.484 25.776 11.502 25.92 ;
    END
  END do0[78]
  PIN do0[79]
    DIRECTION OUTPUT ;
    USE SIGNAL ;
    PORT
      LAYER M5 ;
        RECT  11.568 25.728 11.592 25.92 ;
    END
  END do0[79]
  PIN do0[7]
    DIRECTION OUTPUT ;
    USE SIGNAL ;
    PORT
      LAYER M5 ;
        RECT  4.992 25.728 5.016 25.92 ;
    END
  END do0[7]
  PIN do0[80]
    DIRECTION OUTPUT ;
    USE SIGNAL ;
    PORT
      LAYER M3 ;
        RECT  11.664 25.776 11.682 25.92 ;
    END
  END do0[80]
  PIN do0[81]
    DIRECTION OUTPUT ;
    USE SIGNAL ;
    PORT
      LAYER M5 ;
        RECT  11.76 25.728 11.784 25.92 ;
    END
  END do0[81]
  PIN do0[82]
    DIRECTION OUTPUT ;
    USE SIGNAL ;
    PORT
      LAYER M3 ;
        RECT  11.844 25.776 11.862 25.92 ;
    END
  END do0[82]
  PIN do0[83]
    DIRECTION OUTPUT ;
    USE SIGNAL ;
    PORT
      LAYER M5 ;
        RECT  11.952 25.728 11.976 25.92 ;
    END
  END do0[83]
  PIN do0[84]
    DIRECTION OUTPUT ;
    USE SIGNAL ;
    PORT
      LAYER M3 ;
        RECT  12.024 25.776 12.042 25.92 ;
    END
  END do0[84]
  PIN do0[85]
    DIRECTION OUTPUT ;
    USE SIGNAL ;
    PORT
      LAYER M5 ;
        RECT  12.096 25.728 12.12 25.92 ;
    END
  END do0[85]
  PIN do0[86]
    DIRECTION OUTPUT ;
    USE SIGNAL ;
    PORT
      LAYER M3 ;
        RECT  12.204 25.776 12.222 25.92 ;
    END
  END do0[86]
  PIN do0[87]
    DIRECTION OUTPUT ;
    USE SIGNAL ;
    PORT
      LAYER M5 ;
        RECT  12.288 25.728 12.312 25.92 ;
    END
  END do0[87]
  PIN do0[88]
    DIRECTION OUTPUT ;
    USE SIGNAL ;
    PORT
      LAYER M3 ;
        RECT  12.384 25.776 12.402 25.92 ;
    END
  END do0[88]
  PIN do0[89]
    DIRECTION OUTPUT ;
    USE SIGNAL ;
    PORT
      LAYER M5 ;
        RECT  12.48 25.728 12.504 25.92 ;
    END
  END do0[89]
  PIN do0[8]
    DIRECTION OUTPUT ;
    USE SIGNAL ;
    PORT
      LAYER M3 ;
        RECT  5.076 25.776 5.094 25.92 ;
    END
  END do0[8]
  PIN do0[90]
    DIRECTION OUTPUT ;
    USE SIGNAL ;
    PORT
      LAYER M3 ;
        RECT  12.564 25.776 12.582 25.92 ;
    END
  END do0[90]
  PIN do0[91]
    DIRECTION OUTPUT ;
    USE SIGNAL ;
    PORT
      LAYER M5 ;
        RECT  12.672 25.728 12.696 25.92 ;
    END
  END do0[91]
  PIN do0[92]
    DIRECTION OUTPUT ;
    USE SIGNAL ;
    PORT
      LAYER M3 ;
        RECT  12.744 25.776 12.762 25.92 ;
    END
  END do0[92]
  PIN do0[93]
    DIRECTION OUTPUT ;
    USE SIGNAL ;
    PORT
      LAYER M5 ;
        RECT  12.864 25.728 12.888 25.92 ;
    END
  END do0[93]
  PIN do0[94]
    DIRECTION OUTPUT ;
    USE SIGNAL ;
    PORT
      LAYER M3 ;
        RECT  12.924 25.776 12.942 25.92 ;
    END
  END do0[94]
  PIN do0[95]
    DIRECTION OUTPUT ;
    USE SIGNAL ;
    PORT
      LAYER M5 ;
        RECT  13.008 25.728 13.032 25.92 ;
    END
  END do0[95]
  PIN do0[96]
    DIRECTION OUTPUT ;
    USE SIGNAL ;
    PORT
      LAYER M3 ;
        RECT  13.104 25.776 13.122 25.92 ;
    END
  END do0[96]
  PIN do0[97]
    DIRECTION OUTPUT ;
    USE SIGNAL ;
    PORT
      LAYER M5 ;
        RECT  13.2 25.728 13.224 25.92 ;
    END
  END do0[97]
  PIN do0[98]
    DIRECTION OUTPUT ;
    USE SIGNAL ;
    PORT
      LAYER M3 ;
        RECT  13.284 25.776 13.302 25.92 ;
    END
  END do0[98]
  PIN do0[99]
    DIRECTION OUTPUT ;
    USE SIGNAL ;
    PORT
      LAYER M5 ;
        RECT  13.392 25.728 13.416 25.92 ;
    END
  END do0[99]
  PIN do0[9]
    DIRECTION OUTPUT ;
    USE SIGNAL ;
    PORT
      LAYER M5 ;
        RECT  5.184 25.728 5.208 25.92 ;
    END
  END do0[9]
  PIN fi0[0]
    DIRECTION INPUT ;
    USE SIGNAL ;
    PORT
      LAYER M5 ;
        RECT  30.24 0 30.264 0.192 ;
    END
  END fi0[0]
  PIN fn0[0]
    DIRECTION OUTPUT ;
    USE SIGNAL ;
    PORT
      LAYER M5 ;
        RECT  30.192 25.728 30.216 25.92 ;
    END
  END fn0[0]
  PIN fo0[0]
    DIRECTION OUTPUT ;
    USE SIGNAL ;
    PORT
      LAYER M3 ;
        RECT  30.276 25.776 30.294 25.92 ;
    END
  END fo0[0]
  PIN VDD
    DIRECTION INOUT ;
    USE POWER ;
    PORT
      LAYER M5 ;
        RECT  56.592 2.151 56.712 23.769 ;
        RECT  53.892 2.151 54.012 23.769 ;
        RECT  51.192 2.151 51.312 23.769 ;
        RECT  48.492 2.151 48.612 23.769 ;
        RECT  45.792 2.151 45.912 23.769 ;
        RECT  43.092 2.151 43.212 23.769 ;
        RECT  40.392 2.151 40.512 23.769 ;
        RECT  37.692 2.151 37.812 23.769 ;
        RECT  34.992 2.151 35.112 23.769 ;
        RECT  32.292 2.151 32.412 23.769 ;
        RECT  29.592 2.151 29.712 23.769 ;
        RECT  26.892 2.151 27.012 23.769 ;
        RECT  24.192 2.151 24.312 23.769 ;
        RECT  21.492 2.151 21.612 23.769 ;
        RECT  18.792 2.151 18.912 23.769 ;
        RECT  16.092 2.151 16.212 23.769 ;
        RECT  13.392 2.151 13.512 23.769 ;
        RECT  10.692 2.151 10.812 23.769 ;
        RECT  7.992 2.151 8.112 23.769 ;
        RECT  5.292 2.151 5.412 23.769 ;
        RECT  2.592 2.151 2.712 23.769 ;
    END
  END VDD
  PIN VSS
    DIRECTION INOUT ;
    USE GROUND ;
    PORT
      LAYER M5 ;
        RECT  56.4 2.137 56.52 23.783 ;
        RECT  53.7 2.137 53.82 23.783 ;
        RECT  51 2.137 51.12 23.783 ;
        RECT  48.3 2.137 48.42 23.783 ;
        RECT  45.6 2.137 45.72 23.783 ;
        RECT  42.9 2.137 43.02 23.783 ;
        RECT  40.2 2.137 40.32 23.783 ;
        RECT  37.5 2.137 37.62 23.783 ;
        RECT  34.8 2.137 34.92 23.783 ;
        RECT  32.1 2.137 32.22 23.783 ;
        RECT  29.4 2.137 29.52 23.783 ;
        RECT  26.7 2.137 26.82 23.783 ;
        RECT  24 2.137 24.12 23.783 ;
        RECT  21.3 2.137 21.42 23.783 ;
        RECT  18.6 2.137 18.72 23.783 ;
        RECT  15.9 2.137 16.02 23.783 ;
        RECT  13.2 2.137 13.32 23.783 ;
        RECT  10.5 2.137 10.62 23.783 ;
        RECT  7.8 2.137 7.92 23.783 ;
        RECT  5.1 2.137 5.22 23.783 ;
        RECT  2.4 2.137 2.52 23.783 ;
    END
  END VSS
  # OT_OBS_CLOSED layer=M5 d_um=1.536 added=96
  OBS
    LAYER RVTN ;
     RECT  2.16 2.16 58.32 2.295 ;
     RECT  2.16 2.565 58.32 2.835 ;
     RECT  2.16 3.105 58.32 3.375 ;
     RECT  2.16 3.645 58.32 3.915 ;
     RECT  2.16 4.185 58.32 4.455 ;
     RECT  2.16 4.725 58.32 4.995 ;
     RECT  2.16 5.265 58.32 5.535 ;
     RECT  2.16 5.805 58.32 6.075 ;
     RECT  2.16 6.345 58.32 6.615 ;
     RECT  2.16 6.885 58.32 7.155 ;
     RECT  2.16 7.425 58.32 7.695 ;
     RECT  2.16 7.965 58.32 8.235 ;
     RECT  2.16 8.505 58.32 8.775 ;
     RECT  2.16 9.045 58.32 9.315 ;
     RECT  2.16 9.585 58.32 9.855 ;
     RECT  2.16 10.125 58.32 10.395 ;
     RECT  2.16 10.665 58.32 10.935 ;
     RECT  2.16 11.205 58.32 11.475 ;
     RECT  2.16 11.745 58.32 12.015 ;
     RECT  2.16 12.285 58.32 12.555 ;
     RECT  2.16 12.825 58.32 13.095 ;
     RECT  2.16 13.365 58.32 13.635 ;
     RECT  2.16 13.905 58.32 14.175 ;
     RECT  2.16 14.445 58.32 14.715 ;
     RECT  2.16 14.985 58.32 15.255 ;
     RECT  2.16 15.525 58.32 15.795 ;
     RECT  2.16 16.065 58.32 16.335 ;
     RECT  2.16 16.605 58.32 16.875 ;
     RECT  2.16 17.145 58.32 17.415 ;
     RECT  2.16 17.685 58.32 17.955 ;
     RECT  2.16 18.225 58.32 18.495 ;
     RECT  2.16 18.765 58.32 19.035 ;
     RECT  2.16 19.305 58.32 19.575 ;
     RECT  2.16 19.845 58.32 20.115 ;
     RECT  2.16 20.385 58.32 20.655 ;
     RECT  2.16 20.925 58.32 21.195 ;
     RECT  2.16 21.465 58.32 21.735 ;
     RECT  2.16 22.005 58.32 22.275 ;
     RECT  2.16 22.545 58.32 22.815 ;
     RECT  2.16 23.085 58.32 23.355 ;
     RECT  2.16 23.625 58.32 23.76 ;
    LAYER RVTP ;
     RECT  2.16 2.295 58.32 2.565 ;
     RECT  2.16 2.835 58.32 3.105 ;
     RECT  2.16 3.375 58.32 3.645 ;
     RECT  2.16 3.915 58.32 4.185 ;
     RECT  2.16 4.455 58.32 4.725 ;
     RECT  2.16 4.995 58.32 5.265 ;
     RECT  2.16 5.535 58.32 5.805 ;
     RECT  2.16 6.075 58.32 6.345 ;
     RECT  2.16 6.615 58.32 6.885 ;
     RECT  2.16 7.155 58.32 7.425 ;
     RECT  2.16 7.695 58.32 7.965 ;
     RECT  2.16 8.235 58.32 8.505 ;
     RECT  2.16 8.775 58.32 9.045 ;
     RECT  2.16 9.315 58.32 9.585 ;
     RECT  2.16 9.855 58.32 10.125 ;
     RECT  2.16 10.395 58.32 10.665 ;
     RECT  2.16 10.935 58.32 11.205 ;
     RECT  2.16 11.475 58.32 11.745 ;
     RECT  2.16 12.015 58.32 12.285 ;
     RECT  2.16 12.555 58.32 12.825 ;
     RECT  2.16 13.095 58.32 13.365 ;
     RECT  2.16 13.635 58.32 13.905 ;
     RECT  2.16 14.175 58.32 14.445 ;
     RECT  2.16 14.715 58.32 14.985 ;
     RECT  2.16 15.255 58.32 15.525 ;
     RECT  2.16 15.795 58.32 16.065 ;
     RECT  2.16 16.335 58.32 16.605 ;
     RECT  2.16 16.875 58.32 17.145 ;
     RECT  2.16 17.415 58.32 17.685 ;
     RECT  2.16 17.955 58.32 18.225 ;
     RECT  2.16 18.495 58.32 18.765 ;
     RECT  2.16 19.035 58.32 19.305 ;
     RECT  2.16 19.575 58.32 19.845 ;
     RECT  2.16 20.115 58.32 20.385 ;
     RECT  2.16 20.655 58.32 20.925 ;
     RECT  2.16 21.195 58.32 21.465 ;
     RECT  2.16 21.735 58.32 22.005 ;
     RECT  2.16 22.275 58.32 22.545 ;
     RECT  2.16 22.815 58.32 23.085 ;
     RECT  2.16 23.355 58.32 23.625 ;
    LAYER M1 ;
     RECT  2.16 2.151 58.32 23.769 ;
    LAYER M2 ;
     RECT  2.16 2.151 3.703 23.769 ;
     RECT  3.703 2.106 4.927 23.769 ;
     RECT  4.927 2.034 5.251 23.769 ;
     RECT  5.251 2.034 5.647 23.958 ;
     RECT  5.647 2.034 5.935 24.039 ;
     RECT  5.935 2.034 6.035 24.084 ;
     RECT  6.035 2.034 6.287 24.039 ;
     RECT  5.431 25.101 6.323 25.119 ;
     RECT  6.287 2.151 6.359 24.039 ;
     RECT  6.727 0.144 6.827 0.162 ;
     RECT  6.359 2.151 7.447 23.769 ;
     RECT  7.447 2.106 7.483 23.769 ;
     RECT  6.511 25.758 7.727 25.848 ;
     RECT  7.483 2.106 7.799 23.85 ;
     RECT  7.799 2.151 7.835 23.85 ;
     RECT  8.167 25.101 8.563 25.119 ;
     RECT  8.563 25.101 8.663 25.2 ;
     RECT  7.835 2.151 8.923 23.769 ;
     RECT  8.663 25.182 9.103 25.2 ;
     RECT  7.843 0.144 9.131 0.162 ;
     RECT  9.103 25.182 9.131 25.272 ;
     RECT  8.923 1.728 9.275 23.769 ;
     RECT  9.131 25.254 9.419 25.272 ;
     RECT  9.427 25.758 9.743 25.848 ;
     RECT  9.275 1.8 9.779 23.769 ;
     RECT  10.363 0.144 10.427 0.162 ;
     RECT  9.779 2.151 10.435 23.769 ;
     RECT  10.435 2.151 10.571 23.85 ;
     RECT  10.571 2.151 10.579 23.769 ;
     RECT  10.579 1.728 10.895 23.769 ;
     RECT  10.895 2.151 11.875 23.769 ;
     RECT  11.407 0.144 11.939 0.162 ;
     RECT  11.299 25.101 12.011 25.119 ;
     RECT  12.199 25.218 12.235 25.776 ;
     RECT  12.235 25.218 12.335 25.848 ;
     RECT  12.335 25.218 12.515 25.236 ;
     RECT  12.595 1.152 12.695 1.17 ;
     RECT  11.875 2.106 12.875 23.769 ;
     RECT  12.875 2.151 13.279 23.769 ;
     RECT  12.775 0.144 13.343 0.162 ;
     RECT  13.279 2.151 13.379 23.85 ;
     RECT  13.855 25.101 14.215 25.119 ;
     RECT  13.379 2.151 14.575 23.769 ;
     RECT  14.215 25.101 14.639 25.164 ;
     RECT  14.639 25.146 14.675 25.164 ;
     RECT  14.575 1.728 15.215 23.769 ;
     RECT  15.223 25.758 15.323 25.848 ;
     RECT  15.323 25.83 15.359 25.848 ;
     RECT  16.591 0.306 16.699 0.324 ;
     RECT  16.699 0.144 16.799 0.324 ;
     RECT  17.311 25.758 17.347 25.776 ;
     RECT  17.347 25.758 17.447 25.848 ;
     RECT  18.031 25.146 18.167 25.164 ;
     RECT  15.215 2.151 18.175 23.769 ;
     RECT  18.175 2.106 18.607 23.769 ;
     RECT  18.607 0.144 18.779 0.162 ;
     RECT  18.607 2.106 19.399 23.85 ;
     RECT  19.399 2.106 19.427 24.039 ;
     RECT  19.427 2.151 19.535 24.039 ;
     RECT  19.327 25.101 20.047 25.119 ;
     RECT  19.535 2.151 20.263 23.769 ;
     RECT  20.047 25.101 20.335 25.2 ;
     RECT  19.759 0.144 20.471 0.162 ;
     RECT  20.335 25.101 20.471 25.848 ;
     RECT  20.471 25.101 20.759 25.119 ;
     RECT  20.263 1.728 21.199 23.769 ;
     RECT  21.199 1.728 21.371 23.85 ;
     RECT  21.271 0.144 21.659 0.162 ;
     RECT  21.703 25.101 21.991 25.119 ;
     RECT  21.991 25.101 22.091 25.236 ;
     RECT  22.091 25.101 22.559 25.2 ;
     RECT  22.559 25.182 22.739 25.2 ;
     RECT  23.467 25.83 23.503 25.848 ;
     RECT  21.371 1.728 23.719 23.769 ;
     RECT  23.503 25.758 23.891 25.848 ;
     RECT  23.891 25.758 23.927 25.776 ;
     RECT  23.719 1.152 24.079 23.769 ;
     RECT  24.079 1.152 24.179 23.85 ;
     RECT  24.655 0.144 24.755 0.162 ;
     RECT  24.259 25.101 24.791 25.119 ;
     RECT  24.179 1.728 24.935 23.769 ;
     RECT  25.159 25.758 25.195 25.776 ;
     RECT  25.195 25.758 25.295 25.848 ;
     RECT  25.735 0.144 25.915 0.162 ;
     RECT  25.915 0.144 26.015 0.198 ;
     RECT  26.015 0.144 26.051 0.162 ;
     RECT  24.935 2.151 26.815 23.769 ;
     RECT  26.851 0.144 27.031 0.162 ;
     RECT  27.031 0.144 27.095 0.234 ;
     RECT  26.815 2.151 27.131 23.85 ;
     RECT  27.095 0.216 27.167 0.234 ;
     RECT  27.499 1.152 27.599 1.17 ;
     RECT  27.175 25.101 27.715 25.119 ;
     RECT  27.715 25.101 27.751 25.776 ;
     RECT  27.751 25.101 28.211 25.848 ;
     RECT  28.211 25.218 28.391 25.848 ;
     RECT  27.131 2.151 28.471 23.769 ;
     RECT  28.471 1.728 28.715 23.769 ;
     RECT  28.687 0.306 28.795 0.324 ;
     RECT  28.795 0.144 28.895 0.324 ;
     RECT  28.391 25.758 28.931 25.848 ;
     RECT  29.299 25.182 29.371 25.2 ;
     RECT  29.371 25.101 29.579 25.2 ;
     RECT  28.895 0.144 29.767 0.162 ;
     RECT  29.579 25.101 29.911 25.164 ;
     RECT  29.767 0.144 29.975 0.324 ;
     RECT  28.715 2.151 30.127 23.769 ;
     RECT  30.127 1.728 30.163 23.769 ;
     RECT  29.911 25.056 30.163 25.164 ;
     RECT  30.163 1.728 30.263 25.164 ;
     RECT  30.263 25.056 30.451 25.164 ;
     RECT  29.975 0.144 30.623 0.162 ;
     RECT  30.451 25.056 30.623 25.236 ;
     RECT  30.263 2.151 31.063 23.769 ;
     RECT  30.623 25.056 31.351 25.074 ;
     RECT  31.351 25.02 31.567 25.074 ;
     RECT  31.567 25.02 31.595 25.119 ;
     RECT  31.063 1.728 31.963 23.769 ;
     RECT  31.595 25.101 32.107 25.119 ;
     RECT  31.963 1.152 32.467 23.769 ;
     RECT  32.107 25.101 32.467 25.164 ;
     RECT  32.503 0.144 32.603 0.162 ;
     RECT  32.467 1.152 32.603 25.236 ;
     RECT  32.603 1.152 32.675 23.769 ;
     RECT  32.675 1.224 32.783 23.769 ;
     RECT  32.603 25.218 32.891 25.236 ;
     RECT  32.783 1.728 34.087 23.769 ;
     RECT  34.087 1.728 34.295 23.958 ;
     RECT  34.295 2.151 34.583 23.958 ;
     RECT  34.583 2.151 34.979 23.85 ;
     RECT  34.447 0.144 35.195 0.162 ;
     RECT  34.979 2.151 35.239 23.769 ;
     RECT  35.239 1.728 35.743 23.769 ;
     RECT  35.743 1.728 35.987 23.958 ;
     RECT  35.987 1.728 36.275 23.769 ;
     RECT  36.535 0.144 36.887 0.162 ;
     RECT  35.383 25.101 36.995 25.119 ;
     RECT  36.895 0.216 37.031 0.234 ;
     RECT  36.275 2.106 37.471 23.769 ;
     RECT  37.471 2.106 37.607 23.85 ;
     RECT  37.615 0.144 37.895 0.162 ;
     RECT  37.607 2.106 38.011 23.769 ;
     RECT  37.939 24.516 38.119 24.534 ;
     RECT  38.119 24.516 38.299 25.119 ;
     RECT  38.011 1.728 38.435 23.769 ;
     RECT  38.299 24.516 38.479 25.2 ;
     RECT  38.479 24.516 38.543 25.272 ;
     RECT  38.543 25.101 38.651 25.272 ;
     RECT  38.651 25.254 39.019 25.272 ;
     RECT  39.019 25.254 39.055 25.776 ;
     RECT  38.435 1.8 39.083 23.769 ;
     RECT  39.055 25.254 39.155 25.848 ;
     RECT  39.083 2.151 39.991 23.769 ;
     RECT  39.991 1.728 40.099 23.769 ;
     RECT  40.063 0.216 40.135 0.234 ;
     RECT  40.099 1.728 40.343 23.85 ;
     RECT  40.135 0.144 40.415 0.234 ;
     RECT  40.343 1.728 40.559 23.769 ;
     RECT  40.639 25.83 40.675 25.848 ;
     RECT  40.675 25.758 40.775 25.848 ;
     RECT  40.415 0.144 40.847 0.162 ;
     RECT  40.855 24.606 40.991 24.624 ;
     RECT  40.559 2.151 41.467 23.769 ;
     RECT  41.575 25.101 41.719 25.119 ;
     RECT  41.467 1.728 41.855 23.769 ;
     RECT  41.719 25.101 41.891 25.848 ;
     RECT  41.827 0.144 41.927 0.162 ;
     RECT  41.891 25.758 42.467 25.848 ;
     RECT  42.763 0.144 43.763 0.162 ;
     RECT  43.771 24.516 43.951 24.534 ;
     RECT  43.951 24.516 44.311 25.119 ;
     RECT  44.311 24.516 44.375 25.164 ;
     RECT  44.375 25.101 44.519 25.164 ;
     RECT  44.519 25.101 44.807 25.119 ;
     RECT  41.855 2.151 44.959 23.769 ;
     RECT  44.959 1.728 45.095 23.769 ;
     RECT  45.095 2.151 45.607 23.769 ;
     RECT  45.679 0.144 45.859 0.162 ;
     RECT  45.859 0.144 45.959 0.234 ;
     RECT  45.607 2.151 45.967 23.85 ;
     RECT  45.959 0.216 46.031 0.234 ;
     RECT  45.967 2.151 46.039 23.958 ;
     RECT  46.039 1.728 46.399 23.958 ;
     RECT  46.399 1.152 46.499 23.958 ;
     RECT  46.147 25.182 46.507 25.2 ;
     RECT  46.507 25.101 46.931 25.2 ;
     RECT  46.499 1.728 46.939 23.958 ;
     RECT  46.939 1.728 47.075 24.039 ;
     RECT  46.931 25.182 47.147 25.2 ;
     RECT  47.075 1.728 47.363 23.769 ;
     RECT  47.695 25.758 47.795 25.848 ;
     RECT  47.795 25.758 47.831 25.776 ;
     RECT  47.363 2.151 47.983 23.769 ;
     RECT  47.983 2.151 48.163 23.958 ;
     RECT  48.163 2.151 48.415 24.039 ;
     RECT  48.415 2.07 48.659 24.039 ;
     RECT  47.335 0.144 48.731 0.162 ;
     RECT  48.883 1.152 48.983 1.17 ;
     RECT  48.659 2.151 49.423 24.039 ;
     RECT  49.423 2.151 49.559 24.12 ;
     RECT  49.819 25.758 49.855 25.776 ;
     RECT  49.559 2.151 49.891 23.958 ;
     RECT  49.855 25.758 49.955 25.848 ;
     RECT  49.891 1.728 50.531 23.958 ;
     RECT  50.531 1.728 50.675 23.85 ;
     RECT  50.935 0.144 51.179 0.162 ;
     RECT  50.675 2.151 51.439 23.85 ;
     RECT  51.691 25.758 52.115 25.848 ;
     RECT  51.439 2.151 52.295 23.958 ;
     RECT  52.159 25.182 52.691 25.236 ;
     RECT  52.691 25.182 52.943 25.2 ;
     RECT  52.295 2.151 52.987 23.769 ;
     RECT  53.599 25.758 53.735 25.848 ;
     RECT  52.987 1.728 53.815 23.769 ;
     RECT  53.815 1.728 53.995 23.85 ;
     RECT  53.167 0.144 54.095 0.162 ;
     RECT  53.995 1.728 54.095 24.534 ;
     RECT  54.095 24.516 54.175 24.534 ;
     RECT  54.175 24.516 54.203 24.624 ;
     RECT  54.203 24.606 54.355 24.624 ;
     RECT  54.355 24.606 54.851 25.119 ;
     RECT  54.851 25.101 54.931 25.119 ;
     RECT  54.931 25.101 55.111 25.2 ;
     RECT  55.111 25.101 55.211 25.308 ;
     RECT  55.211 25.182 55.247 25.308 ;
     RECT  55.247 25.182 55.283 25.2 ;
     RECT  54.095 1.728 55.355 23.769 ;
     RECT  55.355 1.8 56.083 23.769 ;
     RECT  56.083 1.728 56.183 23.769 ;
     RECT  56.183 2.151 58.32 23.769 ;
    LAYER M3 ;
     RECT  4.374 0.108 4.536 0.144 ;
     RECT  4.554 0.108 4.716 0.144 ;
     RECT  4.734 0.108 4.896 0.144 ;
     RECT  4.914 0.108 5.076 0.144 ;
     RECT  5.094 0.108 5.256 0.144 ;
     RECT  5.274 0.108 5.436 0.144 ;
     RECT  5.454 0.108 5.652 0.144 ;
     RECT  5.67 0.108 5.832 0.144 ;
     RECT  5.85 0.108 6.012 0.144 ;
     RECT  6.03 0.108 6.192 0.144 ;
     RECT  6.21 0.108 6.372 0.144 ;
     RECT  6.39 0.108 6.552 0.144 ;
     RECT  6.57 0.108 6.732 0.144 ;
     RECT  6.75 0.108 6.912 0.144 ;
     RECT  6.93 0.108 7.092 0.144 ;
     RECT  7.11 0.108 7.272 0.144 ;
     RECT  7.29 0.108 7.452 0.144 ;
     RECT  7.47 0.108 7.632 0.144 ;
     RECT  7.65 0.108 7.848 0.144 ;
     RECT  7.866 0.108 8.028 0.144 ;
     RECT  8.046 0.108 8.208 0.144 ;
     RECT  8.226 0.108 8.388 0.144 ;
     RECT  8.406 0.108 8.568 0.144 ;
     RECT  8.586 0.108 8.748 0.144 ;
     RECT  8.766 0.108 8.928 0.144 ;
     RECT  8.946 0.108 9.108 0.144 ;
     RECT  9.126 0.108 9.288 0.144 ;
     RECT  9.306 0.108 9.468 0.144 ;
     RECT  9.486 0.108 9.648 0.144 ;
     RECT  9.666 0.108 9.828 0.144 ;
     RECT  9.846 0.108 10.008 0.144 ;
     RECT  10.026 0.108 10.224 0.144 ;
     RECT  10.242 0.108 10.404 0.144 ;
     RECT  10.422 0.108 10.584 0.144 ;
     RECT  10.602 0.108 10.764 0.144 ;
     RECT  10.782 0.108 10.944 0.144 ;
     RECT  10.962 0.108 11.124 0.144 ;
     RECT  11.142 0.108 11.304 0.144 ;
     RECT  11.322 0.108 11.484 0.144 ;
     RECT  11.502 0.108 11.664 0.144 ;
     RECT  11.682 0.108 11.844 0.144 ;
     RECT  11.862 0.108 12.024 0.144 ;
     RECT  12.042 0.108 12.204 0.144 ;
     RECT  12.222 0.108 12.42 0.144 ;
     RECT  12.438 0.108 12.6 0.144 ;
     RECT  12.618 0.108 12.78 0.144 ;
     RECT  12.798 0.108 12.96 0.144 ;
     RECT  12.978 0.108 13.14 0.144 ;
     RECT  13.158 0.108 13.32 0.144 ;
     RECT  13.338 0.108 13.5 0.144 ;
     RECT  13.518 0.108 13.68 0.144 ;
     RECT  13.698 0.108 13.86 0.144 ;
     RECT  13.878 0.108 14.04 0.144 ;
     RECT  14.058 0.108 14.22 0.144 ;
     RECT  14.238 0.108 14.4 0.144 ;
     RECT  14.418 0.108 14.58 0.144 ;
     RECT  14.598 0.108 14.796 0.144 ;
     RECT  14.814 0.108 14.976 0.144 ;
     RECT  14.994 0.108 15.156 0.144 ;
     RECT  15.174 0.108 15.336 0.144 ;
     RECT  15.354 0.108 15.516 0.144 ;
     RECT  15.534 0.108 15.696 0.144 ;
     RECT  15.714 0.108 15.876 0.144 ;
     RECT  15.894 0.108 16.056 0.144 ;
     RECT  16.074 0.108 16.236 0.144 ;
     RECT  16.254 0.108 16.416 0.144 ;
     RECT  16.434 0.108 16.596 0.144 ;
     RECT  16.614 0.108 16.776 0.144 ;
     RECT  16.794 0.108 16.956 0.144 ;
     RECT  16.974 0.108 17.172 0.144 ;
     RECT  17.19 0.108 17.352 0.144 ;
     RECT  17.37 0.108 17.532 0.144 ;
     RECT  17.55 0.108 17.712 0.144 ;
     RECT  17.73 0.108 17.892 0.144 ;
     RECT  17.91 0.108 18.072 0.144 ;
     RECT  18.09 0.108 18.252 0.144 ;
     RECT  18.27 0.108 18.432 0.144 ;
     RECT  18.45 0.108 18.612 0.144 ;
     RECT  18.63 0.108 18.792 0.144 ;
     RECT  18.81 0.108 18.972 0.144 ;
     RECT  18.99 0.108 19.152 0.144 ;
     RECT  19.17 0.108 19.368 0.144 ;
     RECT  19.386 0.108 19.548 0.144 ;
     RECT  19.566 0.108 19.728 0.144 ;
     RECT  19.746 0.108 19.908 0.144 ;
     RECT  19.926 0.108 20.088 0.144 ;
     RECT  20.106 0.108 20.268 0.144 ;
     RECT  20.286 0.108 20.448 0.144 ;
     RECT  20.466 0.108 20.628 0.144 ;
     RECT  20.646 0.108 20.808 0.144 ;
     RECT  20.826 0.108 20.988 0.144 ;
     RECT  21.006 0.108 21.168 0.144 ;
     RECT  21.186 0.108 21.348 0.144 ;
     RECT  21.366 0.108 21.528 0.144 ;
     RECT  21.546 0.108 21.744 0.144 ;
     RECT  21.762 0.108 21.924 0.144 ;
     RECT  21.942 0.108 22.104 0.144 ;
     RECT  22.122 0.108 22.284 0.144 ;
     RECT  22.302 0.108 22.464 0.144 ;
     RECT  22.482 0.108 22.644 0.144 ;
     RECT  22.662 0.108 22.824 0.144 ;
     RECT  22.842 0.108 23.004 0.144 ;
     RECT  23.022 0.108 23.184 0.144 ;
     RECT  23.202 0.108 23.364 0.144 ;
     RECT  23.382 0.108 23.544 0.144 ;
     RECT  23.562 0.108 23.724 0.144 ;
     RECT  23.742 0.108 23.94 0.144 ;
     RECT  23.958 0.108 24.12 0.144 ;
     RECT  24.138 0.108 24.3 0.144 ;
     RECT  24.318 0.108 24.48 0.144 ;
     RECT  24.498 0.108 24.66 0.144 ;
     RECT  24.678 0.108 24.84 0.144 ;
     RECT  24.858 0.108 25.02 0.144 ;
     RECT  25.038 0.108 25.2 0.144 ;
     RECT  25.218 0.108 25.38 0.144 ;
     RECT  25.398 0.108 25.56 0.144 ;
     RECT  25.578 0.108 25.74 0.144 ;
     RECT  25.758 0.108 25.92 0.144 ;
     RECT  25.938 0.108 26.1 0.144 ;
     RECT  26.118 0.108 26.316 0.144 ;
     RECT  26.334 0.108 26.496 0.144 ;
     RECT  26.514 0.108 26.676 0.144 ;
     RECT  26.694 0.108 26.856 0.144 ;
     RECT  26.874 0.108 27.036 0.144 ;
     RECT  27.054 0.108 27.216 0.144 ;
     RECT  27.234 0.108 27.396 0.144 ;
     RECT  27.414 0.108 27.576 0.144 ;
     RECT  27.594 0.108 27.756 0.144 ;
     RECT  27.774 0.108 27.936 0.144 ;
     RECT  27.954 0.108 28.116 0.144 ;
     RECT  28.134 0.108 28.296 0.144 ;
     RECT  28.314 0.108 28.476 0.144 ;
     RECT  28.494 0.108 28.692 0.144 ;
     RECT  28.71 0.108 28.872 0.144 ;
     RECT  28.89 0.108 29.052 0.144 ;
     RECT  29.07 0.108 29.232 0.144 ;
     RECT  29.25 0.108 29.412 0.144 ;
     RECT  29.43 0.108 29.592 0.144 ;
     RECT  29.61 0.108 29.772 0.144 ;
     RECT  29.79 0.108 29.952 0.144 ;
     RECT  29.97 0.108 30.132 0.144 ;
     RECT  30.15 0.108 30.312 0.144 ;
     RECT  30.33 0.108 30.492 0.144 ;
     RECT  30.51 0.108 30.672 0.144 ;
     RECT  30.69 0.108 30.888 0.144 ;
     RECT  30.906 0.108 31.068 0.144 ;
     RECT  31.086 0.108 31.248 0.144 ;
     RECT  31.266 0.108 31.428 0.144 ;
     RECT  31.446 0.108 31.608 0.144 ;
     RECT  31.626 0.108 31.788 0.144 ;
     RECT  31.806 0.108 31.968 0.144 ;
     RECT  31.986 0.108 32.148 0.144 ;
     RECT  32.166 0.108 32.328 0.144 ;
     RECT  32.346 0.108 32.508 0.144 ;
     RECT  32.526 0.108 32.688 0.144 ;
     RECT  32.706 0.108 32.868 0.144 ;
     RECT  32.886 0.108 33.048 0.144 ;
     RECT  33.066 0.108 33.264 0.144 ;
     RECT  33.282 0.108 33.444 0.144 ;
     RECT  33.462 0.108 33.624 0.144 ;
     RECT  33.642 0.108 33.804 0.144 ;
     RECT  33.822 0.108 33.984 0.144 ;
     RECT  34.002 0.108 34.164 0.144 ;
     RECT  34.182 0.108 34.344 0.144 ;
     RECT  34.362 0.108 34.524 0.144 ;
     RECT  34.542 0.108 34.704 0.144 ;
     RECT  34.722 0.108 34.884 0.144 ;
     RECT  34.902 0.108 35.064 0.144 ;
     RECT  35.082 0.108 35.244 0.144 ;
     RECT  35.262 0.108 35.46 0.144 ;
     RECT  35.478 0.108 35.64 0.144 ;
     RECT  35.658 0.108 35.82 0.144 ;
     RECT  35.838 0.108 36 0.144 ;
     RECT  36.018 0.108 36.18 0.144 ;
     RECT  36.198 0.108 36.36 0.144 ;
     RECT  36.378 0.108 36.54 0.144 ;
     RECT  36.558 0.108 36.72 0.144 ;
     RECT  36.738 0.108 36.9 0.144 ;
     RECT  36.918 0.108 37.08 0.144 ;
     RECT  37.098 0.108 37.26 0.144 ;
     RECT  37.278 0.108 37.44 0.144 ;
     RECT  37.458 0.108 37.62 0.144 ;
     RECT  37.638 0.108 37.836 0.144 ;
     RECT  37.854 0.108 38.016 0.144 ;
     RECT  38.034 0.108 38.196 0.144 ;
     RECT  38.214 0.108 38.376 0.144 ;
     RECT  38.394 0.108 38.556 0.144 ;
     RECT  38.574 0.108 38.736 0.144 ;
     RECT  38.754 0.108 38.916 0.144 ;
     RECT  38.934 0.108 39.096 0.144 ;
     RECT  39.114 0.108 39.276 0.144 ;
     RECT  39.294 0.108 39.456 0.144 ;
     RECT  39.474 0.108 39.636 0.144 ;
     RECT  39.654 0.108 39.816 0.144 ;
     RECT  39.834 0.108 39.996 0.144 ;
     RECT  40.014 0.108 40.212 0.144 ;
     RECT  40.23 0.108 40.392 0.144 ;
     RECT  40.41 0.108 40.572 0.144 ;
     RECT  40.59 0.108 40.752 0.144 ;
     RECT  40.77 0.108 40.932 0.144 ;
     RECT  40.95 0.108 41.112 0.144 ;
     RECT  41.13 0.108 41.292 0.144 ;
     RECT  41.31 0.108 41.472 0.144 ;
     RECT  41.49 0.108 41.652 0.144 ;
     RECT  41.67 0.108 41.832 0.144 ;
     RECT  41.85 0.108 42.012 0.144 ;
     RECT  42.03 0.108 42.192 0.144 ;
     RECT  42.21 0.108 42.408 0.144 ;
     RECT  42.426 0.108 42.588 0.144 ;
     RECT  42.606 0.108 42.768 0.144 ;
     RECT  42.786 0.108 42.948 0.144 ;
     RECT  42.966 0.108 43.128 0.144 ;
     RECT  43.146 0.108 43.308 0.144 ;
     RECT  43.326 0.108 43.488 0.144 ;
     RECT  43.506 0.108 43.668 0.144 ;
     RECT  43.686 0.108 43.848 0.144 ;
     RECT  43.866 0.108 44.028 0.144 ;
     RECT  44.046 0.108 44.208 0.144 ;
     RECT  44.226 0.108 44.388 0.144 ;
     RECT  44.406 0.108 44.568 0.144 ;
     RECT  44.586 0.108 44.784 0.144 ;
     RECT  44.802 0.108 44.964 0.144 ;
     RECT  44.982 0.108 45.144 0.144 ;
     RECT  45.162 0.108 45.324 0.144 ;
     RECT  45.342 0.108 45.504 0.144 ;
     RECT  45.522 0.108 45.684 0.144 ;
     RECT  45.702 0.108 45.864 0.144 ;
     RECT  45.882 0.108 46.044 0.144 ;
     RECT  46.062 0.108 46.224 0.144 ;
     RECT  46.242 0.108 46.404 0.144 ;
     RECT  46.422 0.108 46.584 0.144 ;
     RECT  46.602 0.108 46.764 0.144 ;
     RECT  46.782 0.108 46.98 0.144 ;
     RECT  46.998 0.108 47.16 0.144 ;
     RECT  47.178 0.108 47.34 0.144 ;
     RECT  47.358 0.108 47.52 0.144 ;
     RECT  47.538 0.108 47.7 0.144 ;
     RECT  47.718 0.108 47.88 0.144 ;
     RECT  47.898 0.108 48.06 0.144 ;
     RECT  48.078 0.108 48.24 0.144 ;
     RECT  48.258 0.108 48.42 0.144 ;
     RECT  48.438 0.108 48.6 0.144 ;
     RECT  48.618 0.108 48.78 0.144 ;
     RECT  48.798 0.108 48.96 0.144 ;
     RECT  48.978 0.108 49.14 0.144 ;
     RECT  49.158 0.108 49.356 0.144 ;
     RECT  49.374 0.108 49.536 0.144 ;
     RECT  49.554 0.108 49.716 0.144 ;
     RECT  49.734 0.108 49.896 0.144 ;
     RECT  49.914 0.108 50.076 0.144 ;
     RECT  50.094 0.108 50.256 0.144 ;
     RECT  50.274 0.108 50.436 0.144 ;
     RECT  50.454 0.108 50.616 0.144 ;
     RECT  50.634 0.108 50.796 0.144 ;
     RECT  50.814 0.108 50.976 0.144 ;
     RECT  50.994 0.108 51.156 0.144 ;
     RECT  51.174 0.108 51.336 0.144 ;
     RECT  51.354 0.108 51.516 0.144 ;
     RECT  51.534 0.108 51.732 0.144 ;
     RECT  51.75 0.108 51.912 0.144 ;
     RECT  51.93 0.108 52.092 0.144 ;
     RECT  52.11 0.108 52.272 0.144 ;
     RECT  52.29 0.108 52.452 0.144 ;
     RECT  52.47 0.108 52.632 0.144 ;
     RECT  52.65 0.108 52.812 0.144 ;
     RECT  52.83 0.108 52.992 0.144 ;
     RECT  53.01 0.108 53.172 0.144 ;
     RECT  53.19 0.108 53.352 0.144 ;
     RECT  53.37 0.108 53.532 0.144 ;
     RECT  53.55 0.108 53.712 0.144 ;
     RECT  53.73 0.108 53.928 0.144 ;
     RECT  53.946 0.108 54.108 0.144 ;
     RECT  54.126 0.108 54.288 0.144 ;
     RECT  54.306 0.108 54.468 0.144 ;
     RECT  54.486 0.108 54.648 0.144 ;
     RECT  54.666 0.108 54.828 0.144 ;
     RECT  54.846 0.108 55.008 0.144 ;
     RECT  55.026 0.108 55.188 0.144 ;
     RECT  55.206 0.108 55.368 0.144 ;
     RECT  55.386 0.108 55.548 0.144 ;
     RECT  55.566 0.108 55.728 0.144 ;
     RECT  55.746 0.108 55.908 0.144 ;
     RECT  55.926 0.108 56.088 0.144 ;
     RECT  4.356 0.144 56.106 1.723 ;
     RECT  4.356 1.723 56.178 2.101 ;
     RECT  3.708 2.101 56.178 2.143 ;
     RECT  3.708 2.143 56.505 2.255 ;
     RECT  3.816 2.255 56.505 2.371 ;
     RECT  2.415 2.143 2.505 2.413 ;
     RECT  3.816 2.371 56.97 2.641 ;
     RECT  57.852 2.263 57.87 2.641 ;
     RECT  3.816 2.641 57.87 2.759 ;
     RECT  4.176 2.759 57.87 2.839 ;
     RECT  4.176 2.839 57.942 5.459 ;
     RECT  4.608 5.459 57.942 5.999 ;
     RECT  4.644 5.999 57.942 7.457 ;
     RECT  4.644 7.457 57.114 7.889 ;
     RECT  57.852 7.457 57.942 7.889 ;
     RECT  4.644 7.889 57.042 7.915 ;
     RECT  4.392 7.915 57.042 7.961 ;
     RECT  57.924 7.889 57.942 8.699 ;
     RECT  4.644 7.961 57.042 8.707 ;
     RECT  4.644 8.707 57.546 9.419 ;
     RECT  4.644 9.419 57.006 9.545 ;
     RECT  4.644 9.545 56.697 9.787 ;
     RECT  4.608 9.787 56.697 10.049 ;
     RECT  4.644 10.049 56.697 13.639 ;
     RECT  2.415 2.413 2.697 23.507 ;
     RECT  4.356 13.639 56.697 23.507 ;
     RECT  2.415 23.507 2.505 23.777 ;
     RECT  4.356 23.507 56.505 23.777 ;
     RECT  4.356 23.777 56.286 25.133 ;
     RECT  4.356 25.133 56.214 25.181 ;
     RECT  4.356 25.181 56.034 25.776 ;
     RECT  4.374 25.776 4.536 25.788 ;
     RECT  4.554 25.776 4.716 25.788 ;
     RECT  4.734 25.776 4.896 25.788 ;
     RECT  4.914 25.776 5.076 25.788 ;
     RECT  5.094 25.776 5.256 25.788 ;
     RECT  5.274 25.776 5.436 25.788 ;
     RECT  5.454 25.776 5.652 25.788 ;
     RECT  5.67 25.776 5.832 25.788 ;
     RECT  5.85 25.776 6.012 25.788 ;
     RECT  6.03 25.776 6.192 25.788 ;
     RECT  6.21 25.776 6.372 25.788 ;
     RECT  6.39 25.776 6.552 25.788 ;
     RECT  6.57 25.776 6.732 25.788 ;
     RECT  6.75 25.776 6.912 25.788 ;
     RECT  6.93 25.776 7.092 25.788 ;
     RECT  7.11 25.776 7.272 25.788 ;
     RECT  7.29 25.776 7.452 25.788 ;
     RECT  7.47 25.776 7.632 25.788 ;
     RECT  7.65 25.776 7.812 25.788 ;
     RECT  7.83 25.776 7.992 25.788 ;
     RECT  8.01 25.776 8.172 25.788 ;
     RECT  8.19 25.776 8.388 25.788 ;
     RECT  8.406 25.776 8.568 25.788 ;
     RECT  8.586 25.776 8.748 25.788 ;
     RECT  8.766 25.776 8.928 25.788 ;
     RECT  8.946 25.776 9.108 25.788 ;
     RECT  9.126 25.776 9.288 25.788 ;
     RECT  9.306 25.776 9.468 25.788 ;
     RECT  9.486 25.776 9.648 25.788 ;
     RECT  9.666 25.776 9.828 25.788 ;
     RECT  9.846 25.776 10.008 25.788 ;
     RECT  10.026 25.776 10.188 25.788 ;
     RECT  10.206 25.776 10.368 25.788 ;
     RECT  10.386 25.776 10.548 25.788 ;
     RECT  10.566 25.776 10.728 25.788 ;
     RECT  10.746 25.776 10.944 25.788 ;
     RECT  10.962 25.776 11.124 25.788 ;
     RECT  11.142 25.776 11.304 25.788 ;
     RECT  11.322 25.776 11.484 25.788 ;
     RECT  11.502 25.776 11.664 25.788 ;
     RECT  11.682 25.776 11.844 25.788 ;
     RECT  11.862 25.776 12.024 25.788 ;
     RECT  12.042 25.776 12.204 25.788 ;
     RECT  12.222 25.776 12.384 25.788 ;
     RECT  12.402 25.776 12.564 25.788 ;
     RECT  12.582 25.776 12.744 25.788 ;
     RECT  12.762 25.776 12.924 25.788 ;
     RECT  12.942 25.776 13.104 25.788 ;
     RECT  13.122 25.776 13.284 25.788 ;
     RECT  13.302 25.776 13.5 25.788 ;
     RECT  13.518 25.776 13.68 25.788 ;
     RECT  13.698 25.776 13.86 25.788 ;
     RECT  13.878 25.776 14.04 25.788 ;
     RECT  14.058 25.776 14.22 25.788 ;
     RECT  14.238 25.776 14.4 25.788 ;
     RECT  14.418 25.776 14.58 25.788 ;
     RECT  14.598 25.776 14.76 25.788 ;
     RECT  14.778 25.776 14.94 25.788 ;
     RECT  14.958 25.776 15.12 25.788 ;
     RECT  15.138 25.776 15.3 25.788 ;
     RECT  15.318 25.776 15.48 25.788 ;
     RECT  15.498 25.776 15.66 25.788 ;
     RECT  15.678 25.776 15.84 25.788 ;
     RECT  15.858 25.776 16.056 25.788 ;
     RECT  16.074 25.776 16.236 25.788 ;
     RECT  16.254 25.776 16.416 25.788 ;
     RECT  16.434 25.776 16.596 25.788 ;
     RECT  16.614 25.776 16.776 25.788 ;
     RECT  16.794 25.776 16.956 25.788 ;
     RECT  16.974 25.776 17.136 25.788 ;
     RECT  17.154 25.776 17.316 25.788 ;
     RECT  17.334 25.776 17.496 25.788 ;
     RECT  17.514 25.776 17.676 25.788 ;
     RECT  17.694 25.776 17.856 25.788 ;
     RECT  17.874 25.776 18.036 25.788 ;
     RECT  18.054 25.776 18.216 25.788 ;
     RECT  18.234 25.776 18.396 25.788 ;
     RECT  18.414 25.776 18.612 25.788 ;
     RECT  18.63 25.776 18.792 25.788 ;
     RECT  18.81 25.776 18.972 25.788 ;
     RECT  18.99 25.776 19.152 25.788 ;
     RECT  19.17 25.776 19.332 25.788 ;
     RECT  19.35 25.776 19.512 25.788 ;
     RECT  19.53 25.776 19.692 25.788 ;
     RECT  19.71 25.776 19.872 25.788 ;
     RECT  19.89 25.776 20.052 25.788 ;
     RECT  20.07 25.776 20.232 25.788 ;
     RECT  20.25 25.776 20.412 25.788 ;
     RECT  20.43 25.776 20.592 25.788 ;
     RECT  20.61 25.776 20.772 25.788 ;
     RECT  20.79 25.776 20.952 25.788 ;
     RECT  20.97 25.776 21.132 25.788 ;
     RECT  21.15 25.776 21.348 25.788 ;
     RECT  21.366 25.776 21.528 25.788 ;
     RECT  21.546 25.776 21.708 25.788 ;
     RECT  21.726 25.776 21.888 25.788 ;
     RECT  21.906 25.776 22.068 25.788 ;
     RECT  22.086 25.776 22.248 25.788 ;
     RECT  22.266 25.776 22.428 25.788 ;
     RECT  22.446 25.776 22.608 25.788 ;
     RECT  22.626 25.776 22.788 25.788 ;
     RECT  22.806 25.776 22.968 25.788 ;
     RECT  22.986 25.776 23.148 25.788 ;
     RECT  23.166 25.776 23.328 25.788 ;
     RECT  23.346 25.776 23.508 25.788 ;
     RECT  23.526 25.776 23.688 25.788 ;
     RECT  23.706 25.776 23.904 25.788 ;
     RECT  23.922 25.776 24.084 25.788 ;
     RECT  24.102 25.776 24.264 25.788 ;
     RECT  24.282 25.776 24.444 25.788 ;
     RECT  24.462 25.776 24.624 25.788 ;
     RECT  24.642 25.776 24.804 25.788 ;
     RECT  24.822 25.776 24.984 25.788 ;
     RECT  25.002 25.776 25.164 25.788 ;
     RECT  25.182 25.776 25.344 25.788 ;
     RECT  25.362 25.776 25.524 25.788 ;
     RECT  25.542 25.776 25.704 25.788 ;
     RECT  25.722 25.776 25.884 25.788 ;
     RECT  25.902 25.776 26.064 25.788 ;
     RECT  26.082 25.776 26.244 25.788 ;
     RECT  26.262 25.776 26.46 25.788 ;
     RECT  26.478 25.776 26.64 25.788 ;
     RECT  26.658 25.776 26.82 25.788 ;
     RECT  26.838 25.776 27 25.788 ;
     RECT  27.018 25.776 27.18 25.788 ;
     RECT  27.198 25.776 27.36 25.788 ;
     RECT  27.378 25.776 27.54 25.788 ;
     RECT  27.558 25.776 27.72 25.788 ;
     RECT  27.738 25.776 27.9 25.788 ;
     RECT  27.918 25.776 28.08 25.788 ;
     RECT  28.098 25.776 28.26 25.788 ;
     RECT  28.278 25.776 28.44 25.788 ;
     RECT  28.458 25.776 28.62 25.788 ;
     RECT  28.638 25.776 28.8 25.788 ;
     RECT  28.818 25.776 29.016 25.788 ;
     RECT  29.034 25.776 29.196 25.788 ;
     RECT  29.214 25.776 29.376 25.788 ;
     RECT  29.394 25.776 29.556 25.788 ;
     RECT  29.574 25.776 29.736 25.788 ;
     RECT  29.754 25.776 29.916 25.788 ;
     RECT  29.934 25.776 30.096 25.788 ;
     RECT  30.114 25.776 30.276 25.788 ;
     RECT  30.294 25.776 30.456 25.788 ;
     RECT  30.474 25.776 30.636 25.788 ;
     RECT  30.654 25.776 30.816 25.788 ;
     RECT  30.834 25.776 30.996 25.788 ;
     RECT  31.014 25.776 31.176 25.788 ;
     RECT  31.194 25.776 31.356 25.788 ;
     RECT  31.374 25.776 31.572 25.788 ;
     RECT  31.59 25.776 31.752 25.788 ;
     RECT  31.77 25.776 31.932 25.788 ;
     RECT  31.95 25.776 32.112 25.788 ;
     RECT  32.13 25.776 32.292 25.788 ;
     RECT  32.31 25.776 32.472 25.788 ;
     RECT  32.49 25.776 32.652 25.788 ;
     RECT  32.67 25.776 32.832 25.788 ;
     RECT  32.85 25.776 33.012 25.788 ;
     RECT  33.03 25.776 33.192 25.788 ;
     RECT  33.21 25.776 33.372 25.788 ;
     RECT  33.39 25.776 33.552 25.788 ;
     RECT  33.57 25.776 33.732 25.788 ;
     RECT  33.75 25.776 33.912 25.788 ;
     RECT  33.93 25.776 34.092 25.788 ;
     RECT  34.11 25.776 34.308 25.788 ;
     RECT  34.326 25.776 34.488 25.788 ;
     RECT  34.506 25.776 34.668 25.788 ;
     RECT  34.686 25.776 34.848 25.788 ;
     RECT  34.866 25.776 35.028 25.788 ;
     RECT  35.046 25.776 35.208 25.788 ;
     RECT  35.226 25.776 35.388 25.788 ;
     RECT  35.406 25.776 35.568 25.788 ;
     RECT  35.586 25.776 35.748 25.788 ;
     RECT  35.766 25.776 35.928 25.788 ;
     RECT  35.946 25.776 36.108 25.788 ;
     RECT  36.126 25.776 36.288 25.788 ;
     RECT  36.306 25.776 36.468 25.788 ;
     RECT  36.486 25.776 36.648 25.788 ;
     RECT  36.666 25.776 36.864 25.788 ;
     RECT  36.882 25.776 37.044 25.788 ;
     RECT  37.062 25.776 37.224 25.788 ;
     RECT  37.242 25.776 37.404 25.788 ;
     RECT  37.422 25.776 37.584 25.788 ;
     RECT  37.602 25.776 37.764 25.788 ;
     RECT  37.782 25.776 37.944 25.788 ;
     RECT  37.962 25.776 38.124 25.788 ;
     RECT  38.142 25.776 38.304 25.788 ;
     RECT  38.322 25.776 38.484 25.788 ;
     RECT  38.502 25.776 38.664 25.788 ;
     RECT  38.682 25.776 38.844 25.788 ;
     RECT  38.862 25.776 39.024 25.788 ;
     RECT  39.042 25.776 39.204 25.788 ;
     RECT  39.222 25.776 39.42 25.788 ;
     RECT  39.438 25.776 39.6 25.788 ;
     RECT  39.618 25.776 39.78 25.788 ;
     RECT  39.798 25.776 39.96 25.788 ;
     RECT  39.978 25.776 40.14 25.788 ;
     RECT  40.158 25.776 40.32 25.788 ;
     RECT  40.338 25.776 40.5 25.788 ;
     RECT  40.518 25.776 40.68 25.788 ;
     RECT  40.698 25.776 40.86 25.788 ;
     RECT  40.878 25.776 41.04 25.788 ;
     RECT  41.058 25.776 41.22 25.788 ;
     RECT  41.238 25.776 41.4 25.788 ;
     RECT  41.418 25.776 41.58 25.788 ;
     RECT  41.598 25.776 41.76 25.788 ;
     RECT  41.778 25.776 41.976 25.788 ;
     RECT  41.994 25.776 42.156 25.788 ;
     RECT  42.174 25.776 42.336 25.788 ;
     RECT  42.354 25.776 42.516 25.788 ;
     RECT  42.534 25.776 42.696 25.788 ;
     RECT  42.714 25.776 42.876 25.788 ;
     RECT  42.894 25.776 43.056 25.788 ;
     RECT  43.074 25.776 43.236 25.788 ;
     RECT  43.254 25.776 43.416 25.788 ;
     RECT  43.434 25.776 43.596 25.788 ;
     RECT  43.614 25.776 43.776 25.788 ;
     RECT  43.794 25.776 43.956 25.788 ;
     RECT  43.974 25.776 44.136 25.788 ;
     RECT  44.154 25.776 44.316 25.788 ;
     RECT  44.334 25.776 44.532 25.788 ;
     RECT  44.55 25.776 44.712 25.788 ;
     RECT  44.73 25.776 44.892 25.788 ;
     RECT  44.91 25.776 45.072 25.788 ;
     RECT  45.09 25.776 45.252 25.788 ;
     RECT  45.27 25.776 45.432 25.788 ;
     RECT  45.45 25.776 45.612 25.788 ;
     RECT  45.63 25.776 45.792 25.788 ;
     RECT  45.81 25.776 45.972 25.788 ;
     RECT  45.99 25.776 46.152 25.788 ;
     RECT  46.17 25.776 46.332 25.788 ;
     RECT  46.35 25.776 46.512 25.788 ;
     RECT  46.53 25.776 46.692 25.788 ;
     RECT  46.71 25.776 46.872 25.788 ;
     RECT  46.89 25.776 47.052 25.788 ;
     RECT  47.07 25.776 47.268 25.788 ;
     RECT  47.286 25.776 47.448 25.788 ;
     RECT  47.466 25.776 47.628 25.788 ;
     RECT  47.646 25.776 47.808 25.788 ;
     RECT  47.826 25.776 47.988 25.788 ;
     RECT  48.006 25.776 48.168 25.788 ;
     RECT  48.186 25.776 48.348 25.788 ;
     RECT  48.366 25.776 48.528 25.788 ;
     RECT  48.546 25.776 48.708 25.788 ;
     RECT  48.726 25.776 48.888 25.788 ;
     RECT  48.906 25.776 49.068 25.788 ;
     RECT  49.086 25.776 49.248 25.788 ;
     RECT  49.266 25.776 49.428 25.788 ;
     RECT  49.446 25.776 49.608 25.788 ;
     RECT  49.626 25.776 49.824 25.788 ;
     RECT  49.842 25.776 50.004 25.788 ;
     RECT  50.022 25.776 50.184 25.788 ;
     RECT  50.202 25.776 50.364 25.788 ;
     RECT  50.382 25.776 50.544 25.788 ;
     RECT  50.562 25.776 50.724 25.788 ;
     RECT  50.742 25.776 50.904 25.788 ;
     RECT  50.922 25.776 51.084 25.788 ;
     RECT  51.102 25.776 51.264 25.788 ;
     RECT  51.282 25.776 51.444 25.788 ;
     RECT  51.462 25.776 51.624 25.788 ;
     RECT  51.642 25.776 51.804 25.788 ;
     RECT  51.822 25.776 51.984 25.788 ;
     RECT  52.002 25.776 52.164 25.788 ;
     RECT  52.182 25.776 52.38 25.788 ;
     RECT  52.398 25.776 52.56 25.788 ;
     RECT  52.578 25.776 52.74 25.788 ;
     RECT  52.758 25.776 52.92 25.788 ;
     RECT  52.938 25.776 53.1 25.788 ;
     RECT  53.118 25.776 53.28 25.788 ;
     RECT  53.298 25.776 53.46 25.788 ;
     RECT  53.478 25.776 53.64 25.788 ;
     RECT  53.658 25.776 53.82 25.788 ;
     RECT  53.838 25.776 54 25.788 ;
     RECT  54.018 25.776 54.18 25.788 ;
     RECT  54.198 25.776 54.36 25.788 ;
     RECT  54.378 25.776 54.54 25.788 ;
     RECT  54.558 25.776 54.72 25.788 ;
     RECT  54.738 25.776 54.936 25.788 ;
     RECT  54.954 25.776 55.116 25.788 ;
     RECT  55.134 25.776 55.296 25.788 ;
     RECT  55.314 25.776 55.476 25.788 ;
     RECT  55.494 25.776 55.656 25.788 ;
     RECT  55.674 25.776 55.836 25.788 ;
     RECT  55.854 25.776 56.016 25.788 ;
     RECT  6.516 25.788 6.552 25.853 ;
     RECT  6.57 25.788 6.732 25.853 ;
     RECT  6.75 25.788 6.912 25.853 ;
     RECT  6.93 25.788 7.092 25.853 ;
     RECT  7.11 25.788 7.272 25.853 ;
     RECT  7.29 25.788 7.452 25.853 ;
     RECT  7.47 25.788 7.632 25.853 ;
     RECT  7.65 25.788 7.722 25.853 ;
     RECT  9.432 25.788 9.468 25.853 ;
     RECT  9.486 25.788 9.648 25.853 ;
     RECT  9.666 25.788 9.738 25.853 ;
     RECT  12.24 25.788 12.33 25.853 ;
     RECT  17.352 25.788 17.442 25.853 ;
     RECT  23.472 25.788 23.508 25.853 ;
     RECT  23.526 25.788 23.688 25.853 ;
     RECT  23.706 25.788 23.886 25.853 ;
     RECT  25.2 25.788 25.29 25.853 ;
     RECT  27.756 25.788 27.9 25.853 ;
     RECT  27.918 25.788 28.08 25.853 ;
     RECT  28.098 25.788 28.26 25.853 ;
     RECT  28.278 25.788 28.44 25.853 ;
     RECT  28.458 25.788 28.62 25.853 ;
     RECT  28.638 25.788 28.8 25.853 ;
     RECT  28.818 25.788 28.926 25.853 ;
     RECT  39.06 25.788 39.15 25.853 ;
     RECT  41.724 25.788 41.76 25.853 ;
     RECT  41.778 25.788 41.976 25.853 ;
     RECT  41.994 25.788 42.156 25.853 ;
     RECT  42.174 25.788 42.336 25.853 ;
     RECT  42.354 25.788 42.462 25.853 ;
     RECT  47.7 25.788 47.79 25.853 ;
     RECT  49.86 25.788 49.95 25.853 ;
     RECT  51.696 25.788 51.804 25.853 ;
     RECT  51.822 25.788 51.984 25.853 ;
     RECT  52.002 25.788 52.11 25.853 ;
    LAYER M4 ;
     RECT  2.408 2.148 2.512 23.772 ;
     RECT  2.512 2.418 2.704 23.502 ;
     RECT  4.453 1.152 4.537 1.176 ;
     RECT  4.597 0.576 4.681 0.6 ;
     RECT  4.597 5.568 4.813 5.592 ;
     RECT  4.597 9.792 4.849 9.816 ;
     RECT  4.445 14.208 4.981 14.232 ;
     RECT  4.769 1.728 5.108 1.752 ;
     RECT  4.813 5.088 5.108 5.592 ;
     RECT  4.381 7.92 5.108 7.944 ;
     RECT  4.849 9.072 5.108 9.816 ;
     RECT  4.981 14.208 5.108 14.28 ;
     RECT  4.789 16.56 5.108 16.584 ;
     RECT  5.108 1.728 5.173 23.772 ;
     RECT  5.173 0.384 5.365 0.408 ;
     RECT  5.173 1.728 5.404 23.976 ;
     RECT  4.597 25.104 5.425 25.128 ;
     RECT  5.404 6.864 5.501 7.944 ;
     RECT  5.365 0.288 5.509 0.408 ;
     RECT  5.425 25.008 5.555 25.128 ;
     RECT  5.509 0.192 5.603 0.408 ;
     RECT  5.404 2.88 5.603 3.864 ;
     RECT  5.603 0.192 5.651 0.216 ;
     RECT  5.555 25.104 5.824 25.128 ;
     RECT  5.824 25.104 5.939 25.176 ;
     RECT  5.404 5.568 6.293 5.592 ;
     RECT  5.404 9.072 6.323 9.816 ;
     RECT  5.501 6.864 6.433 7.368 ;
     RECT  6.433 6.816 6.563 7.368 ;
     RECT  5.603 2.88 6.793 3.432 ;
     RECT  5.404 13.68 6.797 13.704 ;
     RECT  5.404 23.952 6.797 23.976 ;
     RECT  6.323 9.072 7.333 9.096 ;
     RECT  5.404 1.728 7.523 1.752 ;
     RECT  6.793 2.88 7.525 3.672 ;
     RECT  5.939 25.104 7.621 25.128 ;
     RECT  7.621 0.192 7.669 0.216 ;
     RECT  7.525 2.88 7.808 3.864 ;
     RECT  6.541 5.136 7.808 5.16 ;
     RECT  6.563 7.2 7.808 7.368 ;
     RECT  7.333 8.496 7.808 9.096 ;
     RECT  6.577 10.608 7.808 10.632 ;
     RECT  7.189 11.856 7.808 11.88 ;
     RECT  6.805 14.832 7.808 14.856 ;
     RECT  6.421 16.56 7.808 16.584 ;
     RECT  6.997 22.8 7.808 22.824 ;
     RECT  7.808 2.148 7.912 23.772 ;
     RECT  7.621 25.104 7.996 25.176 ;
     RECT  7.912 2.256 8.101 23.772 ;
     RECT  8.101 2.256 8.104 23.976 ;
     RECT  7.669 0.192 8.197 0.312 ;
     RECT  8.197 0.144 8.291 0.312 ;
     RECT  8.104 2.256 8.309 8.568 ;
     RECT  8.309 2.256 8.417 7.368 ;
     RECT  8.291 0.144 8.579 0.168 ;
     RECT  8.104 23.952 8.629 23.976 ;
     RECT  8.417 7.2 8.669 7.368 ;
     RECT  8.417 2.256 8.723 6.024 ;
     RECT  8.723 5.664 8.771 6.024 ;
     RECT  8.629 23.952 8.813 24.024 ;
     RECT  8.813 23.952 8.908 23.976 ;
     RECT  8.104 10.272 8.963 10.632 ;
     RECT  8.723 2.256 9.107 4.632 ;
     RECT  8.104 20.496 9.497 20.52 ;
     RECT  8.669 7.344 9.601 7.368 ;
     RECT  8.309 8.448 9.601 8.568 ;
     RECT  9.107 2.256 9.637 4.584 ;
     RECT  7.996 25.104 9.892 25.128 ;
     RECT  8.963 10.608 9.925 10.632 ;
     RECT  9.892 25.104 10.012 25.176 ;
     RECT  9.601 7.344 10.177 8.568 ;
     RECT  9.637 0.288 10.261 0.312 ;
     RECT  9.925 9.84 10.321 10.632 ;
     RECT  10.309 23.904 10.357 23.928 ;
     RECT  9.637 2.208 10.393 4.584 ;
     RECT  10.393 2.208 10.429 4.68 ;
     RECT  8.771 5.712 10.429 6.024 ;
     RECT  10.429 2.208 10.508 6.024 ;
     RECT  10.177 7.104 10.508 8.568 ;
     RECT  10.321 9.792 10.508 10.632 ;
     RECT  8.104 15.936 10.508 15.96 ;
     RECT  10.349 17.616 10.508 17.64 ;
     RECT  10.309 19.872 10.508 19.896 ;
     RECT  10.357 23.904 10.508 24.024 ;
     RECT  10.508 2.148 10.612 24.024 ;
     RECT  10.261 0.288 10.691 0.36 ;
     RECT  10.612 2.304 10.691 24.024 ;
     RECT  10.691 0.288 10.753 0.312 ;
     RECT  10.691 2.304 10.804 23.502 ;
     RECT  10.804 9.792 10.865 9.864 ;
     RECT  10.753 0.144 10.979 0.312 ;
     RECT  10.979 0.288 11.027 0.312 ;
     RECT  10.804 2.304 11.171 8.04 ;
     RECT  10.012 25.104 11.365 25.128 ;
     RECT  11.365 24.528 11.452 25.128 ;
     RECT  11.171 2.304 11.717 4.728 ;
     RECT  10.865 9.792 11.837 9.816 ;
     RECT  11.797 10.848 11.881 10.872 ;
     RECT  11.452 25.104 11.941 25.128 ;
     RECT  11.717 1.728 11.945 4.728 ;
     RECT  11.945 1.728 12.035 3.672 ;
     RECT  10.804 11.952 12.085 11.976 ;
     RECT  11.941 25.104 12.089 25.176 ;
     RECT  12.035 1.728 12.125 3.48 ;
     RECT  11.171 6.24 12.337 8.04 ;
     RECT  11.945 4.656 12.373 4.728 ;
     RECT  12.089 25.152 12.413 25.176 ;
     RECT  12.277 15.36 12.469 15.384 ;
     RECT  12.125 1.728 12.899 1.752 ;
     RECT  12.125 3.12 13.013 3.48 ;
     RECT  12.373 4.656 13.013 5.112 ;
     RECT  13.013 3.12 13.021 5.112 ;
     RECT  12.337 6.24 13.021 8.184 ;
     RECT  12.085 11.904 13.052 11.976 ;
     RECT  13.093 1.152 13.189 1.176 ;
     RECT  13.021 3.12 13.208 8.184 ;
     RECT  12.625 9.6 13.208 9.72 ;
     RECT  13.093 10.704 13.208 10.728 ;
     RECT  13.052 11.904 13.208 12.024 ;
     RECT  12.997 13.056 13.208 13.08 ;
     RECT  12.469 14.784 13.208 15.384 ;
     RECT  10.804 16.512 13.208 16.536 ;
     RECT  12.853 21.648 13.208 21.672 ;
     RECT  13.189 23.952 13.208 23.976 ;
     RECT  13.208 2.148 13.312 23.976 ;
     RECT  13.189 0.288 13.427 1.176 ;
     RECT  13.312 2.418 13.504 23.976 ;
     RECT  13.381 25.2 13.525 25.224 ;
     RECT  13.504 6.096 13.601 8.184 ;
     RECT  13.427 0.288 13.667 0.312 ;
     RECT  13.504 2.784 13.763 4.248 ;
     RECT  13.525 25.104 13.817 25.224 ;
     RECT  13.504 10.8 13.997 10.824 ;
     RECT  13.763 2.784 14.033 3.432 ;
     RECT  14.033 2.784 14.257 2.952 ;
     RECT  13.504 9.216 14.285 9.672 ;
     RECT  13.504 13.056 14.285 13.08 ;
     RECT  13.817 25.104 14.465 25.176 ;
     RECT  14.485 1.728 14.641 1.752 ;
     RECT  14.641 1.728 14.725 1.8 ;
     RECT  14.725 1.728 14.789 1.752 ;
     RECT  13.504 23.952 14.821 23.976 ;
     RECT  14.677 17.088 14.825 17.112 ;
     RECT  13.601 6.096 14.929 7.368 ;
     RECT  14.257 2.88 15.029 2.952 ;
     RECT  14.821 23.952 15.185 24.552 ;
     RECT  15.029 2.88 15.253 3.432 ;
     RECT  15.185 23.952 15.443 23.976 ;
     RECT  15.253 2.88 15.469 3.96 ;
     RECT  15.469 2.832 15.577 3.96 ;
     RECT  14.929 5.28 15.577 7.368 ;
     RECT  15.577 2.832 15.733 7.368 ;
     RECT  15.205 11.952 15.733 11.976 ;
     RECT  15.733 2.256 15.908 7.368 ;
     RECT  14.285 9.6 15.908 9.672 ;
     RECT  15.733 11.952 15.908 12.552 ;
     RECT  15.013 22.752 15.908 22.776 ;
     RECT  15.908 2.148 16.012 23.772 ;
     RECT  15.973 0.288 16.117 0.312 ;
     RECT  15.589 25.104 16.117 25.128 ;
     RECT  16.012 2.148 16.204 23.502 ;
     RECT  16.117 25.104 16.309 25.176 ;
     RECT  16.204 11.952 16.337 12.936 ;
     RECT  16.117 0.288 16.403 0.36 ;
     RECT  16.204 6.816 16.489 8.424 ;
     RECT  16.403 0.288 16.499 0.312 ;
     RECT  16.204 2.148 16.685 5.688 ;
     RECT  16.204 9.696 16.741 10.344 ;
     RECT  16.685 1.728 16.769 5.688 ;
     RECT  16.204 15.648 16.769 16.536 ;
     RECT  16.769 2.256 16.877 5.688 ;
     RECT  16.309 25.104 16.877 25.224 ;
     RECT  16.204 17.616 17.093 17.64 ;
     RECT  16.741 10.272 17.129 10.344 ;
     RECT  16.489 6.816 17.219 8.136 ;
     RECT  16.877 5.664 17.411 5.688 ;
     RECT  16.877 2.256 17.417 4.536 ;
     RECT  17.219 6.864 17.521 8.136 ;
     RECT  17.221 22.8 17.597 22.824 ;
     RECT  17.417 2.304 18.097 4.536 ;
     RECT  17.129 10.272 18.169 10.296 ;
     RECT  17.521 6.864 18.241 8.232 ;
     RECT  18.169 9.36 18.241 10.296 ;
     RECT  16.769 16.512 18.421 16.536 ;
     RECT  18.421 0.144 18.469 0.216 ;
     RECT  18.421 24.048 18.469 24.072 ;
     RECT  18.097 2.304 18.608 4.584 ;
     RECT  18.241 6.864 18.608 10.296 ;
     RECT  18.133 11.328 18.608 11.352 ;
     RECT  16.337 12.528 18.608 12.936 ;
     RECT  18.421 16.512 18.608 17.112 ;
     RECT  18.469 23.952 18.608 24.072 ;
     RECT  18.608 2.148 18.707 24.072 ;
     RECT  18.469 0.144 18.781 0.312 ;
     RECT  18.707 2.148 18.904 23.976 ;
     RECT  18.781 0.144 19.043 0.552 ;
     RECT  18.904 23.856 19.043 23.976 ;
     RECT  19.043 0.144 19.091 0.312 ;
     RECT  18.904 17.088 19.145 17.112 ;
     RECT  18.904 2.148 19.333 3.768 ;
     RECT  18.904 14.256 19.361 14.376 ;
     RECT  19.091 0.144 19.379 0.216 ;
     RECT  18.904 6.24 19.397 9.384 ;
     RECT  19.361 14.256 19.397 14.28 ;
     RECT  19.043 23.952 19.541 23.976 ;
     RECT  19.379 0.144 19.571 0.168 ;
     RECT  18.904 5.088 20.003 5.112 ;
     RECT  18.904 10.848 20.185 10.872 ;
     RECT  19.333 1.728 20.189 3.72 ;
     RECT  19.397 6.24 20.261 8.568 ;
     RECT  16.877 25.104 20.293 25.128 ;
     RECT  20.261 6.24 20.329 6.264 ;
     RECT  20.189 2.208 20.365 3.72 ;
     RECT  20.293 25.104 20.38 25.224 ;
     RECT  20.329 6.192 20.444 6.264 ;
     RECT  20.185 10.848 20.485 10.968 ;
     RECT  20.185 9.552 20.581 9.576 ;
     RECT  20.485 10.848 20.581 11.16 ;
     RECT  20.261 7.44 20.797 8.568 ;
     RECT  20.581 9.552 20.797 11.16 ;
     RECT  20.473 17.616 20.869 17.64 ;
     RECT  20.444 5.376 21.157 6.264 ;
     RECT  20.365 2.208 21.265 4.008 ;
     RECT  21.157 5.136 21.265 6.264 ;
     RECT  21.109 0.288 21.299 0.312 ;
     RECT  21.265 2.208 21.308 6.264 ;
     RECT  20.797 7.44 21.308 11.16 ;
     RECT  21.061 12.528 21.308 12.552 ;
     RECT  20.677 13.632 21.308 13.656 ;
     RECT  20.869 17.088 21.308 17.64 ;
     RECT  21.308 2.148 21.412 23.772 ;
     RECT  21.412 2.148 21.445 23.502 ;
     RECT  21.445 2.016 21.604 23.502 ;
     RECT  21.637 0.192 21.779 0.216 ;
     RECT  21.604 2.016 21.797 5.832 ;
     RECT  21.797 1.728 21.827 5.832 ;
     RECT  20.38 25.104 22.096 25.176 ;
     RECT  22.096 25.104 22.205 25.224 ;
     RECT  21.604 6.816 22.211 6.984 ;
     RECT  21.827 1.728 22.355 5.784 ;
     RECT  22.355 4.512 22.451 5.784 ;
     RECT  22.355 1.728 22.465 3.528 ;
     RECT  22.211 6.816 22.493 6.888 ;
     RECT  21.604 8.208 22.633 9.576 ;
     RECT  22.465 1.728 22.637 1.8 ;
     RECT  22.451 4.944 22.709 5.784 ;
     RECT  22.637 1.728 22.745 1.752 ;
     RECT  21.604 22.752 22.781 22.776 ;
     RECT  22.465 2.832 22.817 3.528 ;
     RECT  22.693 15.888 22.853 15.912 ;
     RECT  22.633 8.208 22.897 9.672 ;
     RECT  22.897 9.648 22.921 9.672 ;
     RECT  22.897 8.208 22.957 8.616 ;
     RECT  22.877 17.616 22.961 17.64 ;
     RECT  22.709 5.76 23.317 5.784 ;
     RECT  22.493 6.816 23.317 6.84 ;
     RECT  23.317 5.76 23.677 6.84 ;
     RECT  23.677 5.76 23.708 6.888 ;
     RECT  23.708 5.088 23.777 6.888 ;
     RECT  22.957 7.968 23.777 8.616 ;
     RECT  22.817 2.832 23.797 3.48 ;
     RECT  22.921 9.648 23.797 9.72 ;
     RECT  21.604 10.848 23.797 11.16 ;
     RECT  23.797 2.832 23.845 3.528 ;
     RECT  23.845 2.592 24.008 3.528 ;
     RECT  23.777 5.088 24.008 8.616 ;
     RECT  23.797 9.648 24.008 11.16 ;
     RECT  23.221 13.056 24.008 13.08 ;
     RECT  23.605 16.368 24.008 16.392 ;
     RECT  23.029 19.344 24.008 19.368 ;
     RECT  24.008 2.148 24.112 23.772 ;
     RECT  24.112 2.304 24.133 23.772 ;
     RECT  23.989 0.384 24.181 0.408 ;
     RECT  24.181 0.192 24.277 0.408 ;
     RECT  24.133 2.304 24.304 23.976 ;
     RECT  22.205 25.104 24.325 25.128 ;
     RECT  24.304 2.304 24.445 8.568 ;
     RECT  24.277 0.192 24.467 1.176 ;
     RECT  24.467 0.192 24.515 0.216 ;
     RECT  24.304 16.368 24.581 16.392 ;
     RECT  24.445 2.304 24.659 6.264 ;
     RECT  24.304 20.496 24.833 20.52 ;
     RECT  24.659 5.04 24.851 6.264 ;
     RECT  24.304 23.952 24.905 23.976 ;
     RECT  24.325 25.104 24.941 25.176 ;
     RECT  24.304 15.36 25.085 15.384 ;
     RECT  24.304 17.616 25.085 17.64 ;
     RECT  25.009 0.144 25.235 0.168 ;
     RECT  24.659 2.304 25.285 3.672 ;
     RECT  24.445 7.44 25.475 8.568 ;
     RECT  24.851 5.088 25.517 6.264 ;
     RECT  24.304 10.368 25.813 11.16 ;
     RECT  25.285 1.728 25.837 3.672 ;
     RECT  25.517 5.616 25.916 6.264 ;
     RECT  25.549 0.192 25.955 0.312 ;
     RECT  25.837 1.728 26.093 4.104 ;
     RECT  25.475 7.968 26.233 8.568 ;
     RECT  25.813 9.552 26.233 11.16 ;
     RECT  24.941 25.104 26.428 25.128 ;
     RECT  24.304 13.056 26.533 13.656 ;
     RECT  26.093 1.824 26.593 4.104 ;
     RECT  25.916 5.616 26.629 6.792 ;
     RECT  26.233 7.968 26.629 11.16 ;
     RECT  26.593 1.824 26.708 4.152 ;
     RECT  26.629 5.616 26.708 11.16 ;
     RECT  26.533 13.056 26.708 14.28 ;
     RECT  26.149 16.512 26.708 16.536 ;
     RECT  26.581 17.616 26.708 17.64 ;
     RECT  26.581 23.904 26.708 23.928 ;
     RECT  26.665 0.528 26.725 0.552 ;
     RECT  26.725 0.528 26.917 0.6 ;
     RECT  26.708 1.824 27.004 23.928 ;
     RECT  26.917 0.288 27.109 0.6 ;
     RECT  27.004 23.808 27.173 23.928 ;
     RECT  27.109 0.192 27.251 0.6 ;
     RECT  27.004 1.824 27.299 4.152 ;
     RECT  27.004 10.944 27.347 12.552 ;
     RECT  27.251 0.576 27.395 0.6 ;
     RECT  27.253 23.952 27.445 24.552 ;
     RECT  27.299 1.824 27.493 3.672 ;
     RECT  27.445 23.952 27.533 25.128 ;
     RECT  27.004 5.664 27.539 9.528 ;
     RECT  27.493 1.728 27.605 3.672 ;
     RECT  27.533 25.104 27.637 25.128 ;
     RECT  27.347 12 27.749 12.552 ;
     RECT  27.533 23.952 27.965 23.976 ;
     RECT  27.539 5.664 28.019 5.688 ;
     RECT  27.539 6.864 28.037 9.528 ;
     RECT  27.749 12 28.181 12.024 ;
     RECT  28.213 13.632 28.325 13.656 ;
     RECT  27.637 25.104 28.325 25.176 ;
     RECT  28.037 9.312 28.357 9.528 ;
     RECT  28.325 25.152 28.613 25.176 ;
     RECT  28.213 23.328 28.693 23.352 ;
     RECT  27.605 2.256 28.717 3.672 ;
     RECT  28.357 9.312 28.789 9.72 ;
     RECT  28.717 2.256 29.077 3.96 ;
     RECT  28.037 6.864 29.113 8.232 ;
     RECT  28.789 9.312 29.113 9.816 ;
     RECT  29.113 6.864 29.149 9.816 ;
     RECT  28.465 5.088 29.185 5.112 ;
     RECT  29.077 2.256 29.408 4.104 ;
     RECT  29.185 5.088 29.408 5.16 ;
     RECT  29.149 6.576 29.408 9.816 ;
     RECT  27.347 10.944 29.408 10.968 ;
     RECT  29.269 14.4 29.408 14.424 ;
     RECT  28.549 17.088 29.408 17.112 ;
     RECT  29.077 19.344 29.408 19.368 ;
     RECT  28.693 22.752 29.408 23.352 ;
     RECT  29.408 2.148 29.509 23.772 ;
     RECT  29.461 25.104 29.584 25.128 ;
     RECT  29.509 2.016 29.704 23.772 ;
     RECT  29.704 2.016 29.765 11.4 ;
     RECT  28.285 0.288 29.843 0.312 ;
     RECT  29.765 2.832 30.179 10.248 ;
     RECT  30.085 23.856 30.227 23.928 ;
     RECT  30.179 5.664 30.233 10.248 ;
     RECT  29.584 25.104 30.265 25.176 ;
     RECT  29.704 14.4 30.341 14.424 ;
     RECT  30.227 23.856 30.349 23.88 ;
     RECT  30.233 5.664 30.419 9.192 ;
     RECT  30.419 7.392 30.467 9.192 ;
     RECT  30.467 7.392 30.629 8.568 ;
     RECT  30.179 2.832 30.757 4.632 ;
     RECT  29.765 11.376 30.769 11.4 ;
     RECT  30.769 11.232 30.809 11.4 ;
     RECT  30.757 2.736 30.844 4.632 ;
     RECT  30.265 25.104 30.881 25.224 ;
     RECT  30.757 0.192 30.899 0.216 ;
     RECT  30.419 5.664 30.947 6.36 ;
     RECT  30.233 10.176 30.995 10.248 ;
     RECT  30.985 14.784 31.097 14.808 ;
     RECT  30.844 2.88 31.244 4.632 ;
     RECT  30.947 5.664 31.244 5.88 ;
     RECT  30.709 15.84 31.265 15.864 ;
     RECT  30.881 25.104 31.429 25.128 ;
     RECT  30.995 10.224 31.489 10.248 ;
     RECT  30.809 11.232 31.489 11.256 ;
     RECT  30.629 7.392 31.621 8.232 ;
     RECT  31.429 24.48 31.673 25.128 ;
     RECT  31.244 2.88 31.813 5.88 ;
     RECT  31.772 23.856 31.813 23.976 ;
     RECT  31.621 7.392 31.841 8.52 ;
     RECT  31.813 2.352 31.909 5.88 ;
     RECT  31.841 7.392 31.957 9.096 ;
     RECT  31.489 10.224 31.957 11.256 ;
     RECT  31.909 2.304 32.053 5.88 ;
     RECT  32.053 1.728 32.108 5.88 ;
     RECT  31.957 7.344 32.108 11.256 ;
     RECT  31.265 15.36 32.108 15.864 ;
     RECT  30.901 17.616 32.108 17.64 ;
     RECT  31.813 23.76 32.108 23.976 ;
     RECT  31.673 25.104 32.387 25.128 ;
     RECT  32.108 1.728 32.404 23.976 ;
     RECT  32.404 1.728 32.429 11.4 ;
     RECT  32.429 1.728 32.609 8.568 ;
     RECT  32.609 1.776 32.675 8.568 ;
     RECT  32.675 1.776 32.717 7.944 ;
     RECT  31.957 0.192 32.857 0.216 ;
     RECT  32.429 9.696 32.963 11.4 ;
     RECT  32.404 22.752 33.005 22.776 ;
     RECT  32.857 0.144 33.037 0.216 ;
     RECT  32.717 5.04 33.059 7.944 ;
     RECT  32.404 23.952 33.068 23.976 ;
     RECT  33.037 0.144 33.107 0.312 ;
     RECT  33.059 5.856 33.113 7.944 ;
     RECT  33.068 23.952 33.155 24.552 ;
     RECT  32.963 10.272 33.329 11.4 ;
     RECT  33.155 23.952 33.365 23.976 ;
     RECT  32.404 14.544 33.617 14.808 ;
     RECT  32.717 2.304 33.685 4.008 ;
     RECT  33.113 6.096 33.829 7.944 ;
     RECT  33.685 1.728 33.973 4.008 ;
     RECT  33.973 1.728 33.977 4.584 ;
     RECT  33.977 2.148 34.021 4.584 ;
     RECT  33.107 0.288 34.333 0.312 ;
     RECT  34.021 2.148 34.549 5.112 ;
     RECT  33.829 6.096 34.549 8.904 ;
     RECT  33.637 25.104 34.636 25.128 ;
     RECT  34.652 23.808 34.693 23.832 ;
     RECT  34.549 2.148 34.765 8.904 ;
     RECT  33.329 10.272 34.765 11.256 ;
     RECT  34.333 0.288 34.789 0.36 ;
     RECT  34.765 2.148 34.808 11.256 ;
     RECT  34.357 12.336 34.808 12.36 ;
     RECT  34.693 13.632 34.808 13.656 ;
     RECT  34.021 15.36 34.808 15.384 ;
     RECT  34.693 23.808 34.808 23.928 ;
     RECT  34.808 2.148 34.912 23.928 ;
     RECT  34.912 2.208 34.933 23.928 ;
     RECT  34.789 0.288 35.077 0.456 ;
     RECT  34.933 2.208 35.104 24.552 ;
     RECT  35.104 23.856 35.219 24.552 ;
     RECT  35.219 24.528 35.273 24.552 ;
     RECT  35.104 15.36 35.356 15.672 ;
     RECT  35.356 15.648 35.561 15.672 ;
     RECT  35.653 25.104 35.812 25.128 ;
     RECT  35.077 0.192 35.881 0.6 ;
     RECT  35.104 20.496 35.885 20.52 ;
     RECT  35.881 0.144 35.939 0.6 ;
     RECT  35.939 0.144 36.029 0.216 ;
     RECT  36.029 0.192 36.035 0.216 ;
     RECT  35.104 2.208 36.101 5.112 ;
     RECT  35.104 7.44 36.133 8.04 ;
     RECT  35.812 25.104 36.373 25.176 ;
     RECT  36.133 7.44 36.457 8.376 ;
     RECT  36.101 2.688 36.461 5.112 ;
     RECT  35.104 9.6 36.533 9.624 ;
     RECT  36.373 25.104 36.611 25.272 ;
     RECT  36.611 25.152 36.785 25.272 ;
     RECT  36.461 5.04 36.817 5.112 ;
     RECT  36.785 25.152 36.821 25.176 ;
     RECT  36.457 6.864 37.069 8.376 ;
     RECT  36.949 15.936 37.093 15.96 ;
     RECT  36.757 17.232 37.093 17.256 ;
     RECT  37.285 23.376 37.381 23.4 ;
     RECT  36.461 2.688 37.429 3.864 ;
     RECT  36.817 5.04 37.429 5.16 ;
     RECT  37.429 2.688 37.508 5.16 ;
     RECT  37.069 6.864 37.508 8.568 ;
     RECT  36.629 9.696 37.508 9.72 ;
     RECT  35.104 11.232 37.508 11.256 ;
     RECT  37.381 12.528 37.508 12.552 ;
     RECT  37.093 15.936 37.508 17.256 ;
     RECT  37.381 23.376 37.508 23.928 ;
     RECT  37.508 2.148 37.523 23.928 ;
     RECT  37.523 2.148 37.612 23.772 ;
     RECT  37.612 2.148 37.804 23.502 ;
     RECT  37.381 0.288 37.909 0.312 ;
     RECT  37.804 2.148 37.955 8.568 ;
     RECT  37.628 25.104 38.005 25.128 ;
     RECT  37.909 0.192 38.051 0.312 ;
     RECT  37.955 2.148 38.101 6.312 ;
     RECT  38.005 25.104 38.189 25.176 ;
     RECT  38.101 1.728 38.261 6.312 ;
     RECT  38.261 1.728 38.333 1.752 ;
     RECT  37.804 16.368 38.513 16.392 ;
     RECT  37.804 11.232 38.801 11.4 ;
     RECT  38.051 0.288 38.819 0.312 ;
     RECT  37.955 7.632 38.833 8.568 ;
     RECT  38.261 2.736 38.837 6.312 ;
     RECT  38.837 2.832 38.915 6.312 ;
     RECT  38.915 5.616 38.941 6.312 ;
     RECT  38.915 2.832 38.963 4.488 ;
     RECT  38.917 21.648 39.053 21.672 ;
     RECT  38.941 5.616 39.161 6.408 ;
     RECT  39.109 17.088 39.26 17.112 ;
     RECT  39.161 6.24 39.409 6.408 ;
     RECT  38.833 7.632 39.409 8.616 ;
     RECT  38.801 11.232 39.653 11.256 ;
     RECT  39.409 6.24 39.829 8.616 ;
     RECT  39.973 0.288 39.98 0.312 ;
     RECT  39.98 0.288 40.021 0.408 ;
     RECT  38.963 2.832 40.069 4.008 ;
     RECT  40.069 2.784 40.208 4.008 ;
     RECT  39.829 6.24 40.208 9.096 ;
     RECT  39.653 10.272 40.208 11.256 ;
     RECT  38.773 15.936 40.208 15.96 ;
     RECT  39.26 17.088 40.208 17.16 ;
     RECT  39.493 21.072 40.208 21.096 ;
     RECT  40.021 23.952 40.208 23.976 ;
     RECT  40.208 2.148 40.213 23.976 ;
     RECT  38.189 25.104 40.213 25.128 ;
     RECT  40.213 2.148 40.504 25.128 ;
     RECT  40.504 23.952 40.556 25.128 ;
     RECT  40.556 23.952 40.643 25.176 ;
     RECT  40.504 5.088 40.739 8.568 ;
     RECT  40.504 2.148 40.805 4.056 ;
     RECT  40.504 9.552 40.853 11.352 ;
     RECT  40.739 6.72 40.883 8.568 ;
     RECT  40.643 23.952 40.889 25.128 ;
     RECT  40.021 0.24 40.921 0.408 ;
     RECT  40.921 0.144 40.931 0.408 ;
     RECT  40.504 21.648 40.997 21.672 ;
     RECT  40.504 14.256 41.033 14.28 ;
     RECT  40.853 9.552 41.105 10.344 ;
     RECT  40.805 1.728 41.219 4.056 ;
     RECT  40.931 0.144 41.315 0.168 ;
     RECT  40.883 6.864 41.329 8.568 ;
     RECT  40.504 19.344 41.573 19.368 ;
     RECT  40.739 5.088 41.749 5.688 ;
     RECT  41.219 1.728 41.833 4.008 ;
     RECT  41.749 5.088 42.181 5.736 ;
     RECT  41.329 6.864 42.181 8.232 ;
     RECT  40.889 23.952 42.221 23.976 ;
     RECT  40.889 25.104 42.316 25.128 ;
     RECT  42.181 5.088 42.397 8.232 ;
     RECT  41.509 12.528 42.421 12.552 ;
     RECT  41.105 9.552 42.469 9.576 ;
     RECT  40.853 11.328 42.469 11.352 ;
     RECT  41.833 2.208 42.908 4.008 ;
     RECT  42.397 5.088 42.908 8.568 ;
     RECT  42.469 9.552 42.908 11.352 ;
     RECT  42.421 12.336 42.908 12.552 ;
     RECT  42.565 14.208 42.908 14.232 ;
     RECT  42.757 17.616 42.908 17.64 ;
     RECT  42.757 23.28 42.908 23.928 ;
     RECT  42.908 2.148 42.995 23.928 ;
     RECT  42.757 0.192 43.117 0.216 ;
     RECT  42.995 2.148 43.181 23.88 ;
     RECT  43.181 2.016 43.204 23.88 ;
     RECT  43.204 2.016 43.265 8.568 ;
     RECT  43.117 0.144 43.331 0.216 ;
     RECT  43.204 23.856 43.331 23.88 ;
     RECT  43.265 2.688 43.337 8.568 ;
     RECT  43.204 14.208 43.372 15.096 ;
     RECT  43.372 14.208 43.373 14.28 ;
     RECT  43.337 2.688 43.379 6.312 ;
     RECT  43.436 25.104 43.522 25.128 ;
     RECT  43.331 0.144 43.523 0.168 ;
     RECT  43.379 5.088 43.589 6.312 ;
     RECT  43.522 25.104 43.715 25.176 ;
     RECT  43.379 2.688 43.859 4.104 ;
     RECT  43.373 14.256 43.877 14.28 ;
     RECT  43.204 17.616 43.913 17.64 ;
     RECT  43.204 9.696 44.195 9.72 ;
     RECT  43.859 2.784 44.453 4.104 ;
     RECT  44.389 11.856 44.561 11.88 ;
     RECT  43.589 5.088 44.581 5.688 ;
     RECT  43.337 7.44 44.593 8.568 ;
     RECT  43.715 25.104 44.705 25.128 ;
     RECT  44.581 4.992 44.821 5.688 ;
     RECT  44.453 2.784 45.013 4.008 ;
     RECT  44.773 15.36 45.28 15.384 ;
     RECT  45.013 2.304 45.589 4.008 ;
     RECT  45.589 1.728 45.608 4.008 ;
     RECT  44.821 4.992 45.608 6.312 ;
     RECT  44.593 7.44 45.608 8.76 ;
     RECT  44.989 9.792 45.608 9.816 ;
     RECT  45.493 12.528 45.608 12.552 ;
     RECT  45.157 13.632 45.608 13.656 ;
     RECT  45.28 15.312 45.608 15.384 ;
     RECT  44.965 17.616 45.608 17.64 ;
     RECT  45.608 1.728 45.712 23.772 ;
     RECT  45.712 1.728 45.785 23.502 ;
     RECT  45.685 25.104 45.877 25.128 ;
     RECT  45.785 2.352 45.904 23.502 ;
     RECT  45.781 0.288 45.925 0.312 ;
     RECT  45.925 0.192 46.019 0.312 ;
     RECT  46.019 0.192 46.067 0.216 ;
     RECT  45.877 25.104 46.069 25.176 ;
     RECT  45.904 9.12 46.073 10.296 ;
     RECT  45.904 2.352 46.115 8.088 ;
     RECT  45.904 14.688 46.115 14.808 ;
     RECT  46.115 14.784 46.153 14.808 ;
     RECT  46.069 24.528 46.217 25.176 ;
     RECT  46.217 25.104 46.433 25.176 ;
     RECT  46.115 2.352 46.817 7.656 ;
     RECT  46.817 1.728 46.901 7.656 ;
     RECT  46.073 10.272 46.979 10.296 ;
     RECT  46.717 23.952 46.981 23.976 ;
     RECT  46.981 23.376 47.081 23.976 ;
     RECT  46.901 6.144 47.171 7.656 ;
     RECT  47.081 23.376 47.189 23.4 ;
     RECT  47.125 17.616 47.225 17.64 ;
     RECT  45.904 12.528 47.509 12.6 ;
     RECT  46.901 1.728 47.837 5.112 ;
     RECT  46.433 25.104 47.941 25.128 ;
     RECT  47.509 0.144 48.083 0.168 ;
     RECT  47.171 6.24 48.085 7.656 ;
     RECT  46.073 9.12 48.265 9.144 ;
     RECT  47.941 25.104 48.275 25.224 ;
     RECT  47.837 2.148 48.308 5.112 ;
     RECT  48.085 6.24 48.308 7.992 ;
     RECT  48.265 9.072 48.308 9.144 ;
     RECT  47.257 10.128 48.308 10.152 ;
     RECT  47.509 11.952 48.308 12.6 ;
     RECT  45.904 15.936 48.308 15.96 ;
     RECT  48.037 17.088 48.308 17.112 ;
     RECT  47.285 22.752 48.308 22.776 ;
     RECT  48.308 2.148 48.412 23.772 ;
     RECT  48.275 25.104 48.508 25.128 ;
     RECT  48.412 2.256 48.604 23.772 ;
     RECT  48.604 2.256 48.755 8.04 ;
     RECT  48.755 6.768 48.803 8.04 ;
     RECT  48.604 11.424 48.899 11.448 ;
     RECT  48.755 2.256 48.947 5.736 ;
     RECT  48.133 0.192 48.949 0.6 ;
     RECT  48.604 20.496 48.953 20.52 ;
     RECT  48.604 17.088 48.989 17.64 ;
     RECT  48.949 0.192 48.995 1.272 ;
     RECT  48.995 0.288 49.097 1.272 ;
     RECT  49.097 0.288 49.139 0.408 ;
     RECT  48.947 2.256 49.205 5.208 ;
     RECT  48.989 17.616 49.205 17.64 ;
     RECT  49.205 2.304 49.379 5.208 ;
     RECT  48.613 23.952 49.421 24.552 ;
     RECT  48.604 9.072 49.529 9.096 ;
     RECT  48.604 14.784 49.601 14.808 ;
     RECT  49.139 0.288 49.619 0.312 ;
     RECT  49.421 24.528 49.673 24.552 ;
     RECT  48.604 10.368 49.781 10.392 ;
     RECT  49.741 11.472 49.825 11.496 ;
     RECT  49.717 25.104 49.909 25.128 ;
     RECT  49.909 25.104 49.996 25.224 ;
     RECT  49.993 5.664 50.245 5.736 ;
     RECT  48.803 6.768 50.245 7.944 ;
     RECT  50.065 0.144 50.291 0.168 ;
     RECT  50.773 0.192 50.821 0.216 ;
     RECT  50.353 9.792 50.821 9.816 ;
     RECT  50.821 17.616 50.869 17.64 ;
     RECT  50.245 5.664 50.965 7.944 ;
     RECT  49.379 2.304 51.008 4.584 ;
     RECT  50.965 5.568 51.008 7.944 ;
     RECT  50.821 9.024 51.008 9.816 ;
     RECT  50.437 12.528 51.008 12.552 ;
     RECT  50.629 14.736 51.008 14.76 ;
     RECT  50.869 17.088 51.008 17.64 ;
     RECT  50.869 23.856 51.008 23.88 ;
     RECT  50.821 0.192 51.107 0.312 ;
     RECT  51.107 0.192 51.299 0.216 ;
     RECT  51.008 2.148 51.304 23.88 ;
     RECT  51.304 14.736 51.401 14.76 ;
     RECT  51.304 23.76 51.437 23.88 ;
     RECT  51.304 20.544 51.443 20.568 ;
     RECT  51.304 5.568 51.473 9.816 ;
     RECT  51.304 17.616 51.473 17.64 ;
     RECT  51.473 6 51.481 9.816 ;
     RECT  51.437 23.76 51.481 23.784 ;
     RECT  51.304 21.648 51.833 21.672 ;
     RECT  49.996 25.104 51.877 25.128 ;
     RECT  51.569 1.728 52.021 1.752 ;
     RECT  51.877 25.104 52.069 25.176 ;
     RECT  51.481 6 52.301 7.704 ;
     RECT  51.481 8.928 52.661 9.816 ;
     RECT  51.304 2.88 52.693 4.584 ;
     RECT  52.301 6 52.693 7.656 ;
     RECT  52.661 9.696 52.697 9.816 ;
     RECT  52.693 2.88 52.789 7.656 ;
     RECT  52.069 25.104 52.789 25.224 ;
     RECT  52.789 24.528 52.913 25.224 ;
     RECT  52.913 25.104 52.985 25.224 ;
     RECT  53.017 10.176 53.197 10.2 ;
     RECT  53.197 10.176 53.521 10.296 ;
     RECT  52.789 2.784 53.557 7.656 ;
     RECT  53.557 2.016 53.708 8.472 ;
     RECT  53.521 10.176 53.708 10.392 ;
     RECT  52.981 20.4 53.708 20.424 ;
     RECT  53.365 22.176 53.708 22.2 ;
     RECT  53.173 23.376 53.708 23.4 ;
     RECT  53.708 2.016 53.893 23.772 ;
     RECT  53.893 2.016 53.981 23.976 ;
     RECT  53.981 1.728 54.004 23.976 ;
     RECT  54.004 1.728 54.065 7.656 ;
     RECT  53.797 0.192 54.131 0.216 ;
     RECT  54.004 8.928 54.131 10.872 ;
     RECT  54.065 2.256 54.179 7.656 ;
     RECT  54.179 2.256 54.275 5.16 ;
     RECT  54.004 20.4 54.317 20.568 ;
     RECT  54.179 6.24 54.353 7.656 ;
     RECT  54.275 2.256 54.371 5.064 ;
     RECT  54.004 23.952 54.389 23.976 ;
     RECT  52.985 25.104 54.469 25.176 ;
     RECT  54.371 2.256 54.515 4.584 ;
     RECT  54.131 8.928 54.641 10.392 ;
     RECT  54.353 7.632 54.821 7.656 ;
     RECT  54.317 20.544 54.851 20.568 ;
     RECT  54.641 8.928 54.929 9.768 ;
     RECT  54.515 2.256 55.091 4.152 ;
     RECT  54.469 25.104 55.145 25.224 ;
     RECT  55.091 2.256 55.235 3.48 ;
     RECT  54.353 6.24 55.235 6.264 ;
     RECT  55.235 2.88 55.253 3.48 ;
     RECT  54.997 21.648 55.253 21.672 ;
     RECT  54.929 9.072 55.283 9.768 ;
     RECT  55.189 17.088 55.381 17.112 ;
     RECT  55.781 1.728 56.053 1.752 ;
     RECT  55.145 25.104 56.225 25.176 ;
     RECT  56.225 25.104 56.297 25.128 ;
     RECT  55.253 2.88 56.408 3.432 ;
     RECT  55.283 9.072 56.408 9.096 ;
     RECT  56.041 10.8 56.408 10.824 ;
     RECT  55.493 13.632 56.408 13.656 ;
     RECT  55.381 16.512 56.408 17.112 ;
     RECT  56.408 2.148 56.512 23.772 ;
     RECT  56.512 2.418 56.704 23.502 ;
    LAYER M5 ;
     RECT  8.544 0.133 8.568 0.144 ;
     RECT  10.944 0.133 10.968 0.144 ;
     RECT  19.152 0.133 19.248 0.144 ;
     RECT  19.272 0.133 19.44 0.144 ;
     RECT  19.464 0.133 19.56 0.144 ;
     RECT  25.2 0.133 25.224 0.144 ;
     RECT  33.072 0.133 33.096 0.144 ;
     RECT  41.28 0.133 41.304 0.144 ;
     RECT  43.488 0.133 43.512 0.144 ;
     RECT  48.048 0.133 48.072 0.144 ;
     RECT  50.256 0.133 50.28 0.144 ;
     RECT  4.488 0.144 4.608 0.192 ;
     RECT  4.632 0.144 4.8 0.192 ;
     RECT  4.824 0.144 4.992 0.192 ;
     RECT  5.016 0.144 5.184 0.192 ;
     RECT  5.208 0.144 5.376 0.192 ;
     RECT  5.4 0.144 5.52 0.192 ;
     RECT  5.544 0.144 5.712 0.192 ;
     RECT  5.736 0.144 5.904 0.192 ;
     RECT  5.928 0.144 6.096 0.192 ;
     RECT  6.12 0.144 6.288 0.192 ;
     RECT  6.312 0.144 6.48 0.192 ;
     RECT  6.504 0.144 6.624 0.192 ;
     RECT  6.648 0.144 6.816 0.192 ;
     RECT  6.84 0.144 7.008 0.192 ;
     RECT  7.032 0.144 7.2 0.192 ;
     RECT  7.224 0.144 7.392 0.192 ;
     RECT  7.416 0.144 7.536 0.192 ;
     RECT  7.56 0.144 7.728 0.192 ;
     RECT  7.752 0.144 7.92 0.192 ;
     RECT  7.944 0.144 8.112 0.192 ;
     RECT  8.136 0.144 8.304 0.192 ;
     RECT  8.328 0.144 8.448 0.192 ;
     RECT  8.472 0.144 8.64 0.192 ;
     RECT  8.664 0.144 8.832 0.192 ;
     RECT  8.856 0.144 9.024 0.192 ;
     RECT  9.048 0.144 9.216 0.192 ;
     RECT  9.24 0.144 9.36 0.192 ;
     RECT  9.384 0.144 9.552 0.192 ;
     RECT  9.576 0.144 9.744 0.192 ;
     RECT  9.768 0.144 9.936 0.192 ;
     RECT  9.96 0.144 10.128 0.192 ;
     RECT  10.152 0.144 10.32 0.192 ;
     RECT  10.344 0.144 10.464 0.192 ;
     RECT  10.488 0.144 10.656 0.192 ;
     RECT  10.68 0.144 10.848 0.192 ;
     RECT  10.872 0.144 11.04 0.192 ;
     RECT  11.064 0.144 11.232 0.192 ;
     RECT  11.256 0.144 11.376 0.192 ;
     RECT  11.4 0.144 11.568 0.192 ;
     RECT  11.592 0.144 11.76 0.192 ;
     RECT  11.784 0.144 11.952 0.192 ;
     RECT  11.976 0.144 12.144 0.192 ;
     RECT  12.168 0.144 12.288 0.192 ;
     RECT  12.312 0.144 12.48 0.192 ;
     RECT  12.504 0.144 12.672 0.192 ;
     RECT  12.696 0.144 12.864 0.192 ;
     RECT  12.888 0.144 13.056 0.192 ;
     RECT  13.08 0.144 13.2 0.192 ;
     RECT  13.224 0.144 13.392 0.192 ;
     RECT  13.416 0.144 13.584 0.192 ;
     RECT  13.608 0.144 13.776 0.192 ;
     RECT  13.8 0.144 13.968 0.192 ;
     RECT  13.992 0.144 14.16 0.192 ;
     RECT  14.184 0.144 14.304 0.192 ;
     RECT  14.328 0.144 14.496 0.192 ;
     RECT  14.52 0.144 14.688 0.192 ;
     RECT  14.712 0.144 14.88 0.192 ;
     RECT  14.904 0.144 15.072 0.192 ;
     RECT  15.096 0.144 15.216 0.192 ;
     RECT  15.24 0.144 15.408 0.192 ;
     RECT  15.432 0.144 15.6 0.192 ;
     RECT  15.624 0.144 15.792 0.192 ;
     RECT  15.816 0.144 15.984 0.192 ;
     RECT  16.008 0.144 16.128 0.192 ;
     RECT  16.152 0.144 16.32 0.192 ;
     RECT  16.344 0.144 16.512 0.192 ;
     RECT  16.536 0.144 16.704 0.192 ;
     RECT  16.728 0.144 16.896 0.192 ;
     RECT  16.92 0.144 17.04 0.192 ;
     RECT  17.064 0.144 17.232 0.192 ;
     RECT  17.256 0.144 17.424 0.192 ;
     RECT  17.448 0.144 17.616 0.192 ;
     RECT  17.64 0.144 17.808 0.192 ;
     RECT  17.832 0.144 18 0.192 ;
     RECT  18.024 0.144 18.144 0.192 ;
     RECT  18.168 0.144 18.336 0.192 ;
     RECT  18.36 0.144 18.528 0.192 ;
     RECT  18.552 0.144 18.72 0.192 ;
     RECT  18.744 0.144 18.912 0.192 ;
     RECT  18.936 0.144 19.056 0.192 ;
     RECT  19.08 0.144 19.248 0.192 ;
     RECT  19.272 0.144 19.44 0.192 ;
     RECT  19.464 0.144 19.632 0.192 ;
     RECT  19.656 0.144 19.824 0.192 ;
     RECT  19.848 0.144 19.968 0.192 ;
     RECT  19.992 0.144 20.16 0.192 ;
     RECT  20.184 0.144 20.352 0.192 ;
     RECT  20.376 0.144 20.544 0.192 ;
     RECT  20.568 0.144 20.736 0.192 ;
     RECT  20.76 0.144 20.88 0.192 ;
     RECT  20.904 0.144 21.072 0.192 ;
     RECT  21.096 0.144 21.264 0.192 ;
     RECT  21.288 0.144 21.456 0.192 ;
     RECT  21.48 0.144 21.648 0.192 ;
     RECT  21.672 0.144 21.84 0.192 ;
     RECT  21.864 0.144 21.984 0.192 ;
     RECT  22.008 0.144 22.176 0.192 ;
     RECT  22.2 0.144 22.368 0.192 ;
     RECT  22.392 0.144 22.56 0.192 ;
     RECT  22.584 0.144 22.752 0.192 ;
     RECT  22.776 0.144 22.896 0.192 ;
     RECT  22.92 0.144 23.088 0.192 ;
     RECT  23.112 0.144 23.28 0.192 ;
     RECT  23.304 0.144 23.472 0.192 ;
     RECT  23.496 0.144 23.664 0.192 ;
     RECT  23.688 0.144 23.808 0.192 ;
     RECT  23.832 0.144 24 0.192 ;
     RECT  24.024 0.144 24.192 0.192 ;
     RECT  24.216 0.144 24.384 0.192 ;
     RECT  24.408 0.144 24.576 0.192 ;
     RECT  24.6 0.144 24.72 0.192 ;
     RECT  24.744 0.144 24.912 0.192 ;
     RECT  24.936 0.144 25.104 0.192 ;
     RECT  25.128 0.144 25.296 0.192 ;
     RECT  25.32 0.144 25.488 0.192 ;
     RECT  25.512 0.144 25.68 0.192 ;
     RECT  25.704 0.144 25.824 0.192 ;
     RECT  25.848 0.144 26.016 0.192 ;
     RECT  26.04 0.144 26.208 0.192 ;
     RECT  26.232 0.144 26.4 0.192 ;
     RECT  26.424 0.144 26.592 0.192 ;
     RECT  26.616 0.144 26.736 0.192 ;
     RECT  26.76 0.144 26.928 0.192 ;
     RECT  26.952 0.144 27.12 0.192 ;
     RECT  27.144 0.144 27.312 0.192 ;
     RECT  27.336 0.144 27.504 0.192 ;
     RECT  27.528 0.144 27.648 0.192 ;
     RECT  27.672 0.144 27.84 0.192 ;
     RECT  27.864 0.144 28.032 0.192 ;
     RECT  28.056 0.144 28.224 0.192 ;
     RECT  28.248 0.144 28.416 0.192 ;
     RECT  28.44 0.144 28.56 0.192 ;
     RECT  28.584 0.144 28.752 0.192 ;
     RECT  28.776 0.144 28.944 0.192 ;
     RECT  28.968 0.144 29.136 0.192 ;
     RECT  29.16 0.144 29.328 0.192 ;
     RECT  29.352 0.144 29.52 0.192 ;
     RECT  29.544 0.144 29.664 0.192 ;
     RECT  29.688 0.144 29.856 0.192 ;
     RECT  29.88 0.144 30.048 0.192 ;
     RECT  30.072 0.144 30.24 0.192 ;
     RECT  30.264 0.144 30.432 0.192 ;
     RECT  30.456 0.144 30.576 0.192 ;
     RECT  30.6 0.144 30.768 0.192 ;
     RECT  30.792 0.144 30.96 0.192 ;
     RECT  30.984 0.144 31.152 0.192 ;
     RECT  31.176 0.144 31.344 0.192 ;
     RECT  31.368 0.144 31.488 0.192 ;
     RECT  31.512 0.144 31.68 0.192 ;
     RECT  31.704 0.144 31.872 0.192 ;
     RECT  31.896 0.144 32.064 0.192 ;
     RECT  32.088 0.144 32.256 0.192 ;
     RECT  32.28 0.144 32.4 0.192 ;
     RECT  32.424 0.144 32.592 0.192 ;
     RECT  32.616 0.144 32.784 0.192 ;
     RECT  32.808 0.144 32.976 0.192 ;
     RECT  33 0.144 33.168 0.192 ;
     RECT  33.192 0.144 33.36 0.192 ;
     RECT  33.384 0.144 33.504 0.192 ;
     RECT  33.528 0.144 33.696 0.192 ;
     RECT  33.72 0.144 33.888 0.192 ;
     RECT  33.912 0.144 34.08 0.192 ;
     RECT  34.104 0.144 34.272 0.192 ;
     RECT  34.296 0.144 34.416 0.192 ;
     RECT  34.44 0.144 34.608 0.192 ;
     RECT  34.632 0.144 34.8 0.192 ;
     RECT  34.824 0.144 34.992 0.192 ;
     RECT  35.016 0.144 35.184 0.192 ;
     RECT  35.208 0.144 35.328 0.192 ;
     RECT  35.352 0.144 35.52 0.192 ;
     RECT  35.544 0.144 35.712 0.192 ;
     RECT  35.736 0.144 35.904 0.192 ;
     RECT  35.928 0.144 36.096 0.192 ;
     RECT  36.12 0.144 36.24 0.192 ;
     RECT  36.264 0.144 36.432 0.192 ;
     RECT  36.456 0.144 36.624 0.192 ;
     RECT  36.648 0.144 36.816 0.192 ;
     RECT  36.84 0.144 37.008 0.192 ;
     RECT  37.032 0.144 37.2 0.192 ;
     RECT  37.224 0.144 37.344 0.192 ;
     RECT  37.368 0.144 37.536 0.192 ;
     RECT  37.56 0.144 37.728 0.192 ;
     RECT  37.752 0.144 37.92 0.192 ;
     RECT  37.944 0.144 38.112 0.192 ;
     RECT  38.136 0.144 38.256 0.192 ;
     RECT  38.28 0.144 38.448 0.192 ;
     RECT  38.472 0.144 38.64 0.192 ;
     RECT  38.664 0.144 38.832 0.192 ;
     RECT  38.856 0.144 39.024 0.192 ;
     RECT  39.048 0.144 39.168 0.192 ;
     RECT  39.192 0.144 39.36 0.192 ;
     RECT  39.384 0.144 39.552 0.192 ;
     RECT  39.576 0.144 39.744 0.192 ;
     RECT  39.768 0.144 39.936 0.192 ;
     RECT  39.96 0.144 40.08 0.192 ;
     RECT  40.104 0.144 40.272 0.192 ;
     RECT  40.296 0.144 40.464 0.192 ;
     RECT  40.488 0.144 40.656 0.192 ;
     RECT  40.68 0.144 40.848 0.192 ;
     RECT  40.872 0.144 41.04 0.192 ;
     RECT  41.064 0.144 41.184 0.192 ;
     RECT  41.208 0.144 41.376 0.192 ;
     RECT  41.4 0.144 41.568 0.192 ;
     RECT  41.592 0.144 41.76 0.192 ;
     RECT  41.784 0.144 41.952 0.192 ;
     RECT  41.976 0.144 42.096 0.192 ;
     RECT  42.12 0.144 42.288 0.192 ;
     RECT  42.312 0.144 42.48 0.192 ;
     RECT  42.504 0.144 42.672 0.192 ;
     RECT  42.696 0.144 42.864 0.192 ;
     RECT  42.888 0.144 43.008 0.192 ;
     RECT  43.032 0.144 43.2 0.192 ;
     RECT  43.224 0.144 43.392 0.192 ;
     RECT  43.416 0.144 43.584 0.192 ;
     RECT  43.608 0.144 43.776 0.192 ;
     RECT  43.8 0.144 43.92 0.192 ;
     RECT  43.944 0.144 44.112 0.192 ;
     RECT  44.136 0.144 44.304 0.192 ;
     RECT  44.328 0.144 44.496 0.192 ;
     RECT  44.52 0.144 44.688 0.192 ;
     RECT  44.712 0.144 44.88 0.192 ;
     RECT  44.904 0.144 45.024 0.192 ;
     RECT  45.048 0.144 45.216 0.192 ;
     RECT  45.24 0.144 45.408 0.192 ;
     RECT  45.432 0.144 45.6 0.192 ;
     RECT  45.624 0.144 45.792 0.192 ;
     RECT  45.816 0.144 45.936 0.192 ;
     RECT  45.96 0.144 46.128 0.192 ;
     RECT  46.152 0.144 46.32 0.192 ;
     RECT  46.344 0.144 46.512 0.192 ;
     RECT  46.536 0.144 46.704 0.192 ;
     RECT  46.728 0.144 46.848 0.192 ;
     RECT  46.872 0.144 47.04 0.192 ;
     RECT  47.064 0.144 47.232 0.192 ;
     RECT  47.256 0.144 47.424 0.192 ;
     RECT  47.448 0.144 47.616 0.192 ;
     RECT  47.64 0.144 47.76 0.192 ;
     RECT  47.784 0.144 47.952 0.192 ;
     RECT  47.976 0.144 48.144 0.192 ;
     RECT  48.168 0.144 48.336 0.192 ;
     RECT  48.36 0.144 48.528 0.192 ;
     RECT  48.552 0.144 48.72 0.192 ;
     RECT  48.744 0.144 48.864 0.192 ;
     RECT  48.888 0.144 49.056 0.192 ;
     RECT  49.08 0.144 49.248 0.192 ;
     RECT  49.272 0.144 49.44 0.192 ;
     RECT  49.464 0.144 49.632 0.192 ;
     RECT  49.656 0.144 49.776 0.192 ;
     RECT  49.8 0.144 49.968 0.192 ;
     RECT  49.992 0.144 50.16 0.192 ;
     RECT  50.184 0.144 50.352 0.192 ;
     RECT  50.376 0.144 50.544 0.192 ;
     RECT  50.568 0.144 50.688 0.192 ;
     RECT  50.712 0.144 50.88 0.192 ;
     RECT  50.904 0.144 51.072 0.192 ;
     RECT  51.096 0.144 51.264 0.192 ;
     RECT  51.288 0.144 51.456 0.192 ;
     RECT  51.48 0.144 51.6 0.192 ;
     RECT  51.624 0.144 51.792 0.192 ;
     RECT  51.816 0.144 51.984 0.192 ;
     RECT  52.008 0.144 52.176 0.192 ;
     RECT  52.2 0.144 52.368 0.192 ;
     RECT  52.392 0.144 52.56 0.192 ;
     RECT  52.584 0.144 52.704 0.192 ;
     RECT  52.728 0.144 52.896 0.192 ;
     RECT  52.92 0.144 53.088 0.192 ;
     RECT  53.112 0.144 53.28 0.192 ;
     RECT  53.304 0.144 53.472 0.192 ;
     RECT  53.496 0.144 53.616 0.192 ;
     RECT  53.64 0.144 53.808 0.192 ;
     RECT  53.832 0.144 54 0.192 ;
     RECT  54.024 0.144 54.192 0.192 ;
     RECT  54.216 0.144 54.384 0.192 ;
     RECT  54.408 0.144 54.528 0.192 ;
     RECT  54.552 0.144 54.72 0.192 ;
     RECT  54.744 0.144 54.912 0.192 ;
     RECT  54.936 0.144 55.104 0.192 ;
     RECT  55.128 0.144 55.296 0.192 ;
     RECT  55.32 0.144 55.44 0.192 ;
     RECT  55.464 0.144 55.632 0.192 ;
     RECT  55.656 0.144 55.824 0.192 ;
     RECT  55.848 0.144 56.016 0.192 ;
     RECT  4.464 0.192 56.04 1.187 ;
     RECT  4.8 1.187 56.04 1.763 ;
     RECT  5.1 1.763 56.04 2.137 ;
     RECT  2.4 2.137 2.52 2.151 ;
     RECT  5.1 2.137 56.52 2.151 ;
     RECT  5.1 2.151 56.712 2.963 ;
     RECT  5.1 2.963 55.32 3.443 ;
     RECT  6.816 3.443 14.232 3.683 ;
     RECT  5.1 3.443 5.592 3.875 ;
     RECT  7.536 3.683 14.232 3.875 ;
     RECT  15.504 3.443 55.272 5.699 ;
     RECT  15.792 5.699 55.272 6.275 ;
     RECT  15.792 6.275 46.968 6.851 ;
     RECT  48.048 6.275 55.272 6.851 ;
     RECT  5.1 3.875 5.412 6.853 ;
     RECT  6.528 6.805 6.552 6.853 ;
     RECT  7.8 3.875 14.232 6.899 ;
     RECT  50.256 6.851 55.272 6.947 ;
     RECT  15.9 6.851 46.968 6.995 ;
     RECT  5.1 6.853 6.552 7.379 ;
     RECT  50.256 6.947 51.48 7.427 ;
     RECT  7.8 6.899 13.512 7.475 ;
     RECT  15.9 6.995 21.612 7.475 ;
     RECT  22.608 6.995 46.968 7.475 ;
     RECT  48.048 6.851 48.792 7.475 ;
     RECT  50.256 7.427 51.432 7.475 ;
     RECT  33.936 7.475 46.968 7.859 ;
     RECT  50.88 7.475 51.432 7.955 ;
     RECT  10.368 7.475 13.512 8.003 ;
     RECT  22.608 7.475 31.032 8.003 ;
     RECT  48.096 7.475 48.792 8.003 ;
     RECT  11.808 8.003 13.512 8.051 ;
     RECT  33.936 7.859 41.304 8.051 ;
     RECT  48.3 8.003 48.792 8.051 ;
     RECT  42.432 7.859 46.968 8.099 ;
     RECT  36.24 8.051 41.304 8.387 ;
     RECT  36.672 8.387 41.304 8.435 ;
     RECT  7.8 7.475 8.952 8.485 ;
     RECT  28.368 8.003 31.032 8.485 ;
     RECT  32.1 7.475 32.952 8.485 ;
     RECT  10.368 8.003 10.812 8.579 ;
     RECT  20.112 7.475 21.612 8.579 ;
     RECT  22.608 8.003 27.192 8.579 ;
     RECT  38.976 8.435 41.304 8.579 ;
     RECT  42.432 8.099 45.912 8.579 ;
     RECT  51 7.955 51.432 8.579 ;
     RECT  18.432 7.475 18.912 8.627 ;
     RECT  22.848 8.579 24.312 8.627 ;
     RECT  38.976 8.579 40.68 8.627 ;
     RECT  28.368 8.485 32.952 8.869 ;
     RECT  33.936 8.051 35.112 8.869 ;
     RECT  22.848 8.627 22.968 9.155 ;
     RECT  28.368 8.869 35.112 9.203 ;
     RECT  52.656 6.947 55.272 9.203 ;
     RECT  26.592 8.579 27.192 9.541 ;
     RECT  12.816 8.051 13.512 9.731 ;
     RECT  22.944 9.155 22.968 9.731 ;
     RECT  28.368 9.203 29.712 9.731 ;
     RECT  30.96 9.203 35.112 9.731 ;
     RECT  36.672 8.435 37.812 9.731 ;
     RECT  39.696 8.627 40.68 9.731 ;
     RECT  42.672 8.579 44.184 9.731 ;
     RECT  52.656 9.203 54.12 9.731 ;
     RECT  55.152 9.203 55.272 9.731 ;
     RECT  55.248 9.731 55.272 9.779 ;
     RECT  5.1 7.379 6.312 9.827 ;
     RECT  30.96 9.731 32.412 10.211 ;
     RECT  42.672 9.731 43.212 10.213 ;
     RECT  7.344 8.485 8.952 10.307 ;
     RECT  39.696 9.731 40.512 10.307 ;
     RECT  46.944 8.099 46.968 10.307 ;
     RECT  53.232 9.731 54.12 10.307 ;
     RECT  24 8.627 24.312 10.309 ;
     RECT  15.9 7.475 17.112 10.355 ;
     RECT  48.3 8.051 48.612 10.357 ;
     RECT  49.776 7.909 49.8 10.357 ;
     RECT  13.2 9.731 13.512 10.693 ;
     RECT  11.808 8.051 11.832 10.883 ;
     RECT  53.7 10.307 54.12 10.883 ;
     RECT  25.824 9.541 27.192 11.125 ;
     RECT  20.496 8.579 21.612 11.171 ;
     RECT  18.6 8.627 18.912 11.317 ;
     RECT  42.48 10.213 43.212 11.363 ;
     RECT  31.632 10.211 32.412 11.365 ;
     RECT  48.3 10.357 49.8 11.459 ;
     RECT  49.776 11.459 49.8 11.507 ;
     RECT  7.344 10.307 8.112 11.845 ;
     RECT  10.5 8.579 10.812 11.941 ;
     RECT  12.096 11.893 12.12 11.941 ;
     RECT  15.9 10.355 16.212 11.941 ;
     RECT  48.3 11.459 48.612 11.941 ;
     RECT  13.104 10.693 13.512 12.035 ;
     RECT  25.824 11.125 27.336 12.035 ;
     RECT  42.9 11.363 43.212 12.325 ;
     RECT  18.144 11.317 18.912 12.517 ;
     RECT  21.3 11.171 21.612 12.517 ;
     RECT  37.5 9.731 37.812 12.517 ;
     RECT  42.432 12.325 43.212 12.517 ;
     RECT  45.6 8.579 45.912 12.517 ;
     RECT  51 8.579 51.312 12.517 ;
     RECT  45.504 12.517 45.912 12.565 ;
     RECT  47.52 11.941 48.612 12.565 ;
     RECT  15.216 11.941 16.212 12.901 ;
     RECT  17.76 12.517 18.912 12.901 ;
     RECT  10.5 11.941 12.12 13.045 ;
     RECT  13.2 12.035 13.512 13.045 ;
     RECT  23.808 10.309 24.312 13.045 ;
     RECT  25.824 12.035 27.144 13.045 ;
     RECT  21.072 12.517 21.612 13.621 ;
     RECT  44.4 11.845 44.424 13.621 ;
     RECT  45.504 12.565 48.612 13.621 ;
     RECT  56.4 2.963 56.712 13.621 ;
     RECT  5.1 9.827 5.412 13.669 ;
     RECT  5.1 13.669 6.12 14.197 ;
     RECT  15.216 12.901 18.912 14.245 ;
     RECT  39.84 10.307 40.512 14.245 ;
     RECT  41.52 12.517 43.212 14.245 ;
     RECT  15.216 14.245 19.032 14.341 ;
     RECT  29.4 9.731 29.712 14.389 ;
     RECT  31.632 11.365 32.568 14.533 ;
     RECT  33.84 9.731 35.112 14.533 ;
     RECT  44.4 13.621 48.612 14.773 ;
     RECT  4.464 14.197 6.12 14.821 ;
     RECT  7.2 11.845 8.112 14.821 ;
     RECT  31.632 14.533 35.112 15.349 ;
     RECT  31.296 15.349 35.304 15.829 ;
     RECT  23.232 13.045 27.144 15.877 ;
     RECT  4.464 14.821 8.112 15.925 ;
     RECT  37.392 12.517 37.812 15.925 ;
     RECT  55.536 13.621 56.712 16.501 ;
     RECT  15.216 14.341 19.08 17.077 ;
     RECT  28.224 13.621 28.248 17.077 ;
     RECT  29.28 14.389 29.712 17.077 ;
     RECT  38.784 15.925 38.808 17.077 ;
     RECT  39.84 14.245 43.368 17.077 ;
     RECT  55.392 16.501 56.712 17.077 ;
     RECT  36.96 15.925 37.812 17.221 ;
     RECT  10.5 13.045 13.512 17.605 ;
     RECT  20.688 13.621 21.612 17.605 ;
     RECT  10.368 17.605 13.512 19.861 ;
     RECT  53.7 10.883 54.012 20.389 ;
     RECT  30.72 15.829 35.304 20.485 ;
     RECT  50.448 12.517 51.312 20.533 ;
     RECT  52.992 20.389 54.012 20.533 ;
     RECT  55.2 17.077 56.712 20.533 ;
     RECT  50.448 20.533 51.432 21.637 ;
     RECT  20.496 17.605 21.612 22.741 ;
     RECT  22.704 15.877 27.144 22.741 ;
     RECT  2.4 2.151 2.712 23.769 ;
     RECT  10.32 19.861 13.512 23.769 ;
     RECT  20.496 22.741 27.144 23.769 ;
     RECT  36.768 17.221 37.812 23.769 ;
     RECT  52.992 20.533 56.712 23.769 ;
     RECT  2.4 23.769 2.52 23.783 ;
     RECT  10.32 23.769 13.32 23.783 ;
     RECT  20.496 23.769 21.42 23.783 ;
     RECT  36.768 23.769 37.62 23.783 ;
     RECT  52.992 23.769 56.52 23.783 ;
     RECT  28.224 17.077 29.712 23.845 ;
     RECT  30.72 20.485 35.496 23.845 ;
     RECT  10.32 23.783 13.224 23.939 ;
     RECT  14.688 17.077 19.08 23.941 ;
     RECT  22.512 23.769 27.144 23.941 ;
     RECT  28.224 23.845 35.496 23.941 ;
     RECT  10.368 23.939 13.224 24.035 ;
     RECT  44.4 14.773 49.368 24.517 ;
     RECT  50.448 21.637 51.576 24.517 ;
     RECT  52.992 23.783 55.56 24.517 ;
     RECT  4.464 15.925 9.048 25.093 ;
     RECT  10.464 24.035 13.224 25.093 ;
     RECT  14.496 23.941 19.272 25.093 ;
     RECT  20.496 23.783 21.096 25.093 ;
     RECT  22.512 23.941 35.496 25.093 ;
     RECT  36.768 23.783 37.512 25.093 ;
     RECT  38.784 17.077 43.368 25.093 ;
     RECT  44.4 24.517 51.576 25.093 ;
     RECT  52.8 24.517 55.56 25.093 ;
     RECT  4.464 25.093 55.944 25.141 ;
     RECT  4.464 25.141 56.136 25.728 ;
     RECT  4.488 25.728 4.608 25.744 ;
     RECT  4.632 25.728 4.8 25.744 ;
     RECT  4.824 25.728 4.992 25.744 ;
     RECT  5.016 25.728 5.184 25.744 ;
     RECT  5.208 25.728 5.376 25.744 ;
     RECT  5.4 25.728 5.52 25.744 ;
     RECT  5.544 25.728 5.712 25.744 ;
     RECT  5.736 25.728 5.904 25.744 ;
     RECT  5.928 25.728 6.096 25.744 ;
     RECT  6.12 25.728 6.288 25.744 ;
     RECT  6.312 25.728 6.432 25.744 ;
     RECT  6.456 25.728 6.624 25.744 ;
     RECT  6.648 25.728 6.816 25.744 ;
     RECT  6.84 25.728 7.008 25.744 ;
     RECT  7.032 25.728 7.2 25.744 ;
     RECT  7.224 25.728 7.344 25.744 ;
     RECT  7.368 25.728 7.536 25.744 ;
     RECT  7.56 25.728 7.728 25.744 ;
     RECT  7.752 25.728 7.92 25.744 ;
     RECT  7.944 25.728 8.112 25.744 ;
     RECT  8.136 25.728 8.256 25.744 ;
     RECT  8.28 25.728 8.448 25.744 ;
     RECT  8.472 25.728 8.64 25.744 ;
     RECT  8.664 25.728 8.832 25.744 ;
     RECT  8.856 25.728 9.024 25.744 ;
     RECT  9.048 25.728 9.168 25.744 ;
     RECT  9.192 25.728 9.36 25.744 ;
     RECT  9.384 25.728 9.552 25.744 ;
     RECT  9.576 25.728 9.744 25.744 ;
     RECT  9.768 25.728 9.936 25.744 ;
     RECT  9.96 25.728 10.08 25.744 ;
     RECT  10.104 25.728 10.272 25.744 ;
     RECT  10.296 25.728 10.464 25.744 ;
     RECT  10.488 25.728 10.656 25.744 ;
     RECT  10.68 25.728 10.848 25.744 ;
     RECT  10.872 25.728 11.04 25.744 ;
     RECT  11.064 25.728 11.184 25.744 ;
     RECT  11.208 25.728 11.376 25.744 ;
     RECT  11.4 25.728 11.568 25.744 ;
     RECT  11.592 25.728 11.76 25.744 ;
     RECT  11.784 25.728 11.952 25.744 ;
     RECT  11.976 25.728 12.096 25.744 ;
     RECT  12.12 25.728 12.288 25.744 ;
     RECT  12.312 25.728 12.48 25.744 ;
     RECT  12.504 25.728 12.672 25.744 ;
     RECT  12.696 25.728 12.864 25.744 ;
     RECT  12.888 25.728 13.008 25.744 ;
     RECT  13.032 25.728 13.2 25.744 ;
     RECT  13.224 25.728 13.392 25.744 ;
     RECT  13.416 25.728 13.584 25.744 ;
     RECT  13.608 25.728 13.776 25.744 ;
     RECT  13.8 25.728 13.92 25.744 ;
     RECT  13.944 25.728 14.112 25.744 ;
     RECT  14.136 25.728 14.304 25.744 ;
     RECT  14.328 25.728 14.496 25.744 ;
     RECT  14.52 25.728 14.688 25.744 ;
     RECT  14.712 25.728 14.832 25.744 ;
     RECT  14.856 25.728 15.024 25.744 ;
     RECT  15.048 25.728 15.216 25.744 ;
     RECT  15.24 25.728 15.408 25.744 ;
     RECT  15.432 25.728 15.6 25.744 ;
     RECT  15.624 25.728 15.744 25.744 ;
     RECT  15.768 25.728 15.936 25.744 ;
     RECT  15.96 25.728 16.128 25.744 ;
     RECT  16.152 25.728 16.32 25.744 ;
     RECT  16.344 25.728 16.512 25.744 ;
     RECT  16.536 25.728 16.656 25.744 ;
     RECT  16.68 25.728 16.848 25.744 ;
     RECT  16.872 25.728 17.04 25.744 ;
     RECT  17.064 25.728 17.232 25.744 ;
     RECT  17.256 25.728 17.424 25.744 ;
     RECT  17.448 25.728 17.568 25.744 ;
     RECT  17.592 25.728 17.76 25.744 ;
     RECT  17.784 25.728 17.952 25.744 ;
     RECT  17.976 25.728 18.144 25.744 ;
     RECT  18.168 25.728 18.336 25.744 ;
     RECT  18.36 25.728 18.48 25.744 ;
     RECT  18.504 25.728 18.672 25.744 ;
     RECT  18.696 25.728 18.864 25.744 ;
     RECT  18.888 25.728 19.056 25.744 ;
     RECT  19.08 25.728 19.248 25.744 ;
     RECT  19.272 25.728 19.392 25.744 ;
     RECT  19.416 25.728 19.584 25.744 ;
     RECT  19.608 25.728 19.776 25.744 ;
     RECT  19.8 25.728 19.968 25.744 ;
     RECT  19.992 25.728 20.16 25.744 ;
     RECT  20.184 25.728 20.304 25.744 ;
     RECT  20.328 25.728 20.496 25.744 ;
     RECT  20.52 25.728 20.688 25.744 ;
     RECT  20.712 25.728 20.88 25.744 ;
     RECT  20.904 25.728 21.072 25.744 ;
     RECT  21.096 25.728 21.216 25.744 ;
     RECT  21.24 25.728 21.408 25.744 ;
     RECT  21.432 25.728 21.6 25.744 ;
     RECT  21.624 25.728 21.792 25.744 ;
     RECT  21.816 25.728 21.984 25.744 ;
     RECT  22.008 25.728 22.128 25.744 ;
     RECT  22.152 25.728 22.32 25.744 ;
     RECT  22.344 25.728 22.512 25.744 ;
     RECT  22.536 25.728 22.704 25.744 ;
     RECT  22.728 25.728 22.896 25.744 ;
     RECT  22.92 25.728 23.04 25.744 ;
     RECT  23.064 25.728 23.232 25.744 ;
     RECT  23.256 25.728 23.424 25.744 ;
     RECT  23.448 25.728 23.616 25.744 ;
     RECT  23.64 25.728 23.808 25.744 ;
     RECT  23.832 25.728 24 25.744 ;
     RECT  24.024 25.728 24.144 25.744 ;
     RECT  24.168 25.728 24.336 25.744 ;
     RECT  24.36 25.728 24.528 25.744 ;
     RECT  24.552 25.728 24.72 25.744 ;
     RECT  24.744 25.728 24.912 25.744 ;
     RECT  24.936 25.728 25.056 25.744 ;
     RECT  25.08 25.728 25.248 25.744 ;
     RECT  25.272 25.728 25.44 25.744 ;
     RECT  25.464 25.728 25.632 25.744 ;
     RECT  25.656 25.728 25.824 25.744 ;
     RECT  25.848 25.728 25.968 25.744 ;
     RECT  25.992 25.728 26.16 25.744 ;
     RECT  26.184 25.728 26.352 25.744 ;
     RECT  26.376 25.728 26.544 25.744 ;
     RECT  26.568 25.728 26.736 25.744 ;
     RECT  26.76 25.728 26.88 25.744 ;
     RECT  26.904 25.728 27.072 25.744 ;
     RECT  27.096 25.728 27.264 25.744 ;
     RECT  27.288 25.728 27.456 25.744 ;
     RECT  27.48 25.728 27.648 25.744 ;
     RECT  27.672 25.728 27.792 25.744 ;
     RECT  27.816 25.728 27.984 25.744 ;
     RECT  28.008 25.728 28.176 25.744 ;
     RECT  28.2 25.728 28.368 25.744 ;
     RECT  28.392 25.728 28.56 25.744 ;
     RECT  28.584 25.728 28.704 25.744 ;
     RECT  28.728 25.728 28.896 25.744 ;
     RECT  28.92 25.728 29.088 25.744 ;
     RECT  29.112 25.728 29.28 25.744 ;
     RECT  29.304 25.728 29.472 25.744 ;
     RECT  29.496 25.728 29.616 25.744 ;
     RECT  29.64 25.728 29.808 25.744 ;
     RECT  29.832 25.728 30 25.744 ;
     RECT  30.024 25.728 30.192 25.744 ;
     RECT  30.216 25.728 30.384 25.744 ;
     RECT  30.408 25.728 30.528 25.744 ;
     RECT  30.552 25.728 30.72 25.744 ;
     RECT  30.744 25.728 30.912 25.744 ;
     RECT  30.936 25.728 31.104 25.744 ;
     RECT  31.128 25.728 31.296 25.744 ;
     RECT  31.32 25.728 31.44 25.744 ;
     RECT  31.464 25.728 31.632 25.744 ;
     RECT  31.656 25.728 31.824 25.744 ;
     RECT  31.848 25.728 32.016 25.744 ;
     RECT  32.04 25.728 32.208 25.744 ;
     RECT  32.232 25.728 32.352 25.744 ;
     RECT  32.376 25.728 32.544 25.744 ;
     RECT  32.568 25.728 32.736 25.744 ;
     RECT  32.76 25.728 32.928 25.744 ;
     RECT  32.952 25.728 33.12 25.744 ;
     RECT  33.144 25.728 33.264 25.744 ;
     RECT  33.288 25.728 33.456 25.744 ;
     RECT  33.48 25.728 33.648 25.744 ;
     RECT  33.672 25.728 33.84 25.744 ;
     RECT  33.864 25.728 34.032 25.744 ;
     RECT  34.056 25.728 34.176 25.744 ;
     RECT  34.2 25.728 34.368 25.744 ;
     RECT  34.392 25.728 34.56 25.744 ;
     RECT  34.584 25.728 34.752 25.744 ;
     RECT  34.776 25.728 34.944 25.744 ;
     RECT  34.968 25.728 35.088 25.744 ;
     RECT  35.112 25.728 35.28 25.744 ;
     RECT  35.304 25.728 35.472 25.744 ;
     RECT  35.496 25.728 35.664 25.744 ;
     RECT  35.688 25.728 35.856 25.744 ;
     RECT  35.88 25.728 36 25.744 ;
     RECT  36.024 25.728 36.192 25.744 ;
     RECT  36.216 25.728 36.384 25.744 ;
     RECT  36.408 25.728 36.576 25.744 ;
     RECT  36.6 25.728 36.768 25.744 ;
     RECT  36.792 25.728 36.96 25.744 ;
     RECT  36.984 25.728 37.104 25.744 ;
     RECT  37.128 25.728 37.296 25.744 ;
     RECT  37.32 25.728 37.488 25.744 ;
     RECT  37.512 25.728 37.68 25.744 ;
     RECT  37.704 25.728 37.872 25.744 ;
     RECT  37.896 25.728 38.016 25.744 ;
     RECT  38.04 25.728 38.208 25.744 ;
     RECT  38.232 25.728 38.4 25.744 ;
     RECT  38.424 25.728 38.592 25.744 ;
     RECT  38.616 25.728 38.784 25.744 ;
     RECT  38.808 25.728 38.928 25.744 ;
     RECT  38.952 25.728 39.12 25.744 ;
     RECT  39.144 25.728 39.312 25.744 ;
     RECT  39.336 25.728 39.504 25.744 ;
     RECT  39.528 25.728 39.696 25.744 ;
     RECT  39.72 25.728 39.84 25.744 ;
     RECT  39.864 25.728 40.032 25.744 ;
     RECT  40.056 25.728 40.224 25.744 ;
     RECT  40.248 25.728 40.416 25.744 ;
     RECT  40.44 25.728 40.608 25.744 ;
     RECT  40.632 25.728 40.752 25.744 ;
     RECT  40.776 25.728 40.944 25.744 ;
     RECT  40.968 25.728 41.136 25.744 ;
     RECT  41.16 25.728 41.328 25.744 ;
     RECT  41.352 25.728 41.52 25.744 ;
     RECT  41.544 25.728 41.664 25.744 ;
     RECT  41.688 25.728 41.856 25.744 ;
     RECT  41.88 25.728 42.048 25.744 ;
     RECT  42.072 25.728 42.24 25.744 ;
     RECT  42.264 25.728 42.432 25.744 ;
     RECT  42.456 25.728 42.576 25.744 ;
     RECT  42.6 25.728 42.768 25.744 ;
     RECT  42.792 25.728 42.96 25.744 ;
     RECT  42.984 25.728 43.152 25.744 ;
     RECT  43.176 25.728 43.344 25.744 ;
     RECT  43.368 25.728 43.488 25.744 ;
     RECT  43.512 25.728 43.68 25.744 ;
     RECT  43.704 25.728 43.872 25.744 ;
     RECT  43.896 25.728 44.064 25.744 ;
     RECT  44.088 25.728 44.256 25.744 ;
     RECT  44.28 25.728 44.4 25.744 ;
     RECT  44.424 25.728 44.592 25.744 ;
     RECT  44.616 25.728 44.784 25.744 ;
     RECT  44.808 25.728 44.976 25.744 ;
     RECT  45 25.728 45.168 25.744 ;
     RECT  45.192 25.728 45.312 25.744 ;
     RECT  45.336 25.728 45.504 25.744 ;
     RECT  45.528 25.728 45.696 25.744 ;
     RECT  45.72 25.728 45.888 25.744 ;
     RECT  45.912 25.728 46.08 25.744 ;
     RECT  46.104 25.728 46.224 25.744 ;
     RECT  46.248 25.728 46.416 25.744 ;
     RECT  46.44 25.728 46.608 25.744 ;
     RECT  46.632 25.728 46.8 25.744 ;
     RECT  46.824 25.728 46.992 25.744 ;
     RECT  47.016 25.728 47.136 25.744 ;
     RECT  47.16 25.728 47.328 25.744 ;
     RECT  47.352 25.728 47.52 25.744 ;
     RECT  47.544 25.728 47.712 25.744 ;
     RECT  47.736 25.728 47.904 25.744 ;
     RECT  47.928 25.728 48.048 25.744 ;
     RECT  48.072 25.728 48.24 25.744 ;
     RECT  48.264 25.728 48.432 25.744 ;
     RECT  48.456 25.728 48.624 25.744 ;
     RECT  48.648 25.728 48.816 25.744 ;
     RECT  48.84 25.728 48.96 25.744 ;
     RECT  48.984 25.728 49.152 25.744 ;
     RECT  49.176 25.728 49.344 25.744 ;
     RECT  49.368 25.728 49.536 25.744 ;
     RECT  49.56 25.728 49.728 25.744 ;
     RECT  49.752 25.728 49.92 25.744 ;
     RECT  49.944 25.728 50.064 25.744 ;
     RECT  50.088 25.728 50.256 25.744 ;
     RECT  50.28 25.728 50.448 25.744 ;
     RECT  50.472 25.728 50.64 25.744 ;
     RECT  50.664 25.728 50.832 25.744 ;
     RECT  50.856 25.728 50.976 25.744 ;
     RECT  51 25.728 51.168 25.744 ;
     RECT  51.192 25.728 51.36 25.744 ;
     RECT  51.384 25.728 51.552 25.744 ;
     RECT  51.576 25.728 51.744 25.744 ;
     RECT  51.768 25.728 51.888 25.744 ;
     RECT  51.912 25.728 52.08 25.744 ;
     RECT  52.104 25.728 52.272 25.744 ;
     RECT  52.296 25.728 52.464 25.744 ;
     RECT  52.488 25.728 52.656 25.744 ;
     RECT  52.68 25.728 52.8 25.744 ;
     RECT  52.824 25.728 52.992 25.744 ;
     RECT  53.016 25.728 53.184 25.744 ;
     RECT  53.208 25.728 53.376 25.744 ;
     RECT  53.4 25.728 53.568 25.744 ;
     RECT  53.592 25.728 53.712 25.744 ;
     RECT  53.736 25.728 53.904 25.744 ;
     RECT  53.928 25.728 54.096 25.744 ;
     RECT  54.12 25.728 54.288 25.744 ;
     RECT  54.312 25.728 54.48 25.744 ;
     RECT  54.504 25.728 54.624 25.744 ;
     RECT  54.648 25.728 54.816 25.744 ;
     RECT  54.84 25.728 55.008 25.744 ;
     RECT  55.032 25.728 55.2 25.744 ;
     RECT  55.224 25.728 55.392 25.744 ;
     RECT  55.416 25.728 55.536 25.744 ;
     RECT  55.56 25.728 55.728 25.744 ;
     RECT  55.752 25.728 55.92 25.744 ;
     RECT  55.944 25.728 56.112 25.744 ;
     RECT  55.32 2.963 56.4 3.443 ;
     RECT  5.592 3.443 6.816 3.683 ;
     RECT  14.232 3.443 15.504 5.699 ;
     RECT  55.272 3.443 56.4 9.779 ;
     RECT  46.968 6.275 48.048 7.475 ;
     RECT  5.412 6.805 6.528 6.853 ;
     RECT  6.552 6.805 7.8 7.379 ;
     RECT  48.792 6.851 50.256 7.475 ;
     RECT  51.48 6.947 52.656 7.427 ;
     RECT  21.612 6.995 22.608 8.579 ;
     RECT  6.312 7.379 7.8 8.485 ;
     RECT  51.432 7.427 52.656 8.579 ;
     RECT  8.952 7.475 10.368 8.579 ;
     RECT  17.112 7.475 18.432 8.627 ;
     RECT  18.912 7.475 20.112 8.579 ;
     RECT  31.032 7.475 32.1 8.485 ;
     RECT  32.952 7.475 33.936 8.869 ;
     RECT  46.968 7.475 48.096 8.003 ;
     RECT  48.792 7.475 50.88 7.909 ;
     RECT  41.304 7.859 42.432 8.579 ;
     RECT  48.792 7.909 49.776 8.051 ;
     RECT  49.8 7.909 50.88 7.955 ;
     RECT  49.8 7.955 51 11.507 ;
     RECT  10.812 8.003 11.808 10.883 ;
     RECT  27.192 8.003 28.368 9.731 ;
     RECT  46.968 8.003 48.3 10.307 ;
     RECT  11.832 8.051 12.816 9.731 ;
     RECT  35.112 8.051 36.24 8.387 ;
     RECT  48.612 8.051 49.776 10.357 ;
     RECT  45.912 8.099 46.944 10.307 ;
     RECT  37.812 8.435 38.976 8.627 ;
     RECT  6.312 8.485 7.344 9.827 ;
     RECT  21.612 8.579 22.848 9.155 ;
     RECT  24.312 8.579 26.592 9.541 ;
     RECT  44.184 8.579 45.6 9.731 ;
     RECT  51.312 8.579 52.656 9.731 ;
     RECT  17.112 8.627 18.6 10.355 ;
     RECT  22.968 8.627 24 9.731 ;
     RECT  21.612 9.155 22.944 9.731 ;
     RECT  29.712 9.203 30.96 10.211 ;
     RECT  54.12 9.203 55.152 9.731 ;
     RECT  24.312 9.541 25.824 13.045 ;
     RECT  11.832 9.731 13.2 10.693 ;
     RECT  23.808 9.731 24 10.309 ;
     RECT  27.192 9.731 27.336 11.125 ;
     RECT  32.412 9.731 33.84 11.365 ;
     RECT  54.12 9.731 55.248 9.779 ;
     RECT  18.144 10.355 18.6 11.317 ;
     RECT  11.832 10.693 13.104 10.883 ;
     RECT  10.812 10.883 13.104 11.893 ;
     RECT  21.072 11.171 21.3 12.517 ;
     RECT  42.48 11.363 42.9 12.325 ;
     RECT  32.568 11.365 33.84 14.533 ;
     RECT  48.612 11.459 49.776 11.507 ;
     RECT  50.448 11.507 51 12.517 ;
     RECT  43.212 11.845 44.4 14.245 ;
     RECT  44.424 11.845 45.6 12.517 ;
     RECT  10.812 11.893 12.096 11.941 ;
     RECT  12.12 11.893 13.104 12.035 ;
     RECT  12.12 12.035 13.2 13.045 ;
     RECT  40.512 12.517 41.52 14.245 ;
     RECT  44.424 12.517 45.504 13.621 ;
     RECT  27.144 13.621 28.224 23.941 ;
     RECT  28.248 13.621 29.4 14.389 ;
     RECT  54.012 13.621 55.536 16.501 ;
     RECT  6.12 13.669 7.2 14.821 ;
     RECT  43.368 14.245 44.4 25.093 ;
     RECT  28.248 14.389 29.28 17.077 ;
     RECT  49.368 14.773 50.448 24.517 ;
     RECT  29.712 15.829 30.72 23.845 ;
     RECT  21.612 15.877 22.704 22.741 ;
     RECT  9.048 15.925 10.5 17.605 ;
     RECT  37.812 15.925 38.784 23.769 ;
     RECT  38.808 15.925 39.84 17.077 ;
     RECT  54.012 16.501 55.392 17.077 ;
     RECT  13.512 17.077 14.688 23.769 ;
     RECT  54.012 17.077 55.2 20.533 ;
     RECT  35.304 17.221 36.768 20.485 ;
     RECT  9.048 17.605 10.368 19.861 ;
     RECT  19.08 17.605 20.496 23.941 ;
     RECT  9.048 19.861 10.32 23.939 ;
     RECT  35.496 20.485 36.768 25.093 ;
     RECT  51.576 21.637 52.992 24.517 ;
     RECT  13.32 23.769 14.688 23.783 ;
     RECT  21.42 23.769 22.512 23.783 ;
     RECT  37.62 23.769 38.784 23.783 ;
     RECT  13.224 23.783 14.688 23.941 ;
     RECT  21.096 23.783 22.512 25.093 ;
     RECT  37.512 23.783 38.784 25.093 ;
     RECT  55.56 23.783 56.136 25.093 ;
     RECT  9.048 23.939 10.368 24.035 ;
     RECT  13.224 23.941 14.496 25.093 ;
     RECT  19.272 23.941 20.496 25.093 ;
     RECT  9.048 24.035 10.464 25.093 ;
     RECT  51.576 24.517 52.8 25.093 ;
     RECT  55.944 25.093 56.136 25.141 ;
  END
END dsfd_stnv_566x1
END LIBRARY
